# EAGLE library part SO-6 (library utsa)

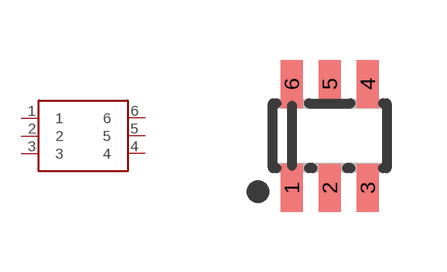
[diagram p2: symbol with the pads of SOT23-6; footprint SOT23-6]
Designator prefix -

## SO-6  [SOT23-6]
1  1
2  2
3  3
4  4
5  5
6  6

## Footprint SOT23-6 (pad centres in mm)
smd 0.55 x 1.2: 1 -0.95,-1.3; 2 0,-1.3; 3 0.95,-1.3; 4 0.95,1.3; 5 0,1.3; 6 -0.95,1.3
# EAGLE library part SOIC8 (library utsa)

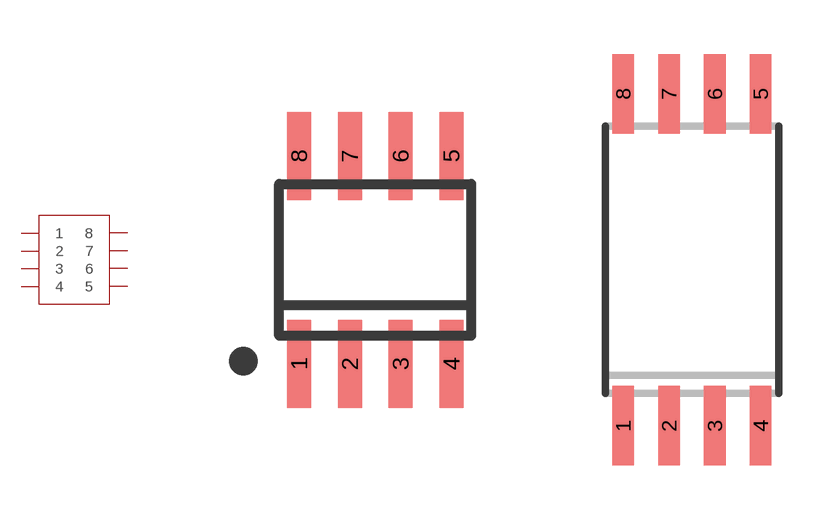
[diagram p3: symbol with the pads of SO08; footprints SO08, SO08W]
Designator prefix -

## SOIC8SO08  [SO08]
1  1
2  2
3  3
4  4
5  5
6  6
7  7
8  8

## SOIC8SO08W  [SO08W]
Pads as for SO08

## Footprint SO08 (pad centres in mm)
SMALL OUTLINE INTEGRATED CIRCUIT body 3.9 mm/JEDEC MS-012AA
smd 0.6 x 2.2: 1 -1.905,-2.6; 2 -0.635,-2.6; 3 0.635,-2.6; 4 1.905,-2.6; 5 1.905,2.6; 6 0.635,2.6; 7 -0.635,2.6; 8 -1.905,2.6

## Footprint SO08W (pad centres in mm)
SMALL OUTLINE INTEGRATED CIRCUIT wide body 7.5 mm/JEDEC MA-012AB
smd 0.6 x 2.2: 1 -1.905,-4.6; 2 -0.635,-4.6; 3 0.635,-4.6; 4 1.905,-4.6; 5 1.905,4.6; 6 0.635,4.6; 7 -0.635,4.6; 8 -1.905,4.6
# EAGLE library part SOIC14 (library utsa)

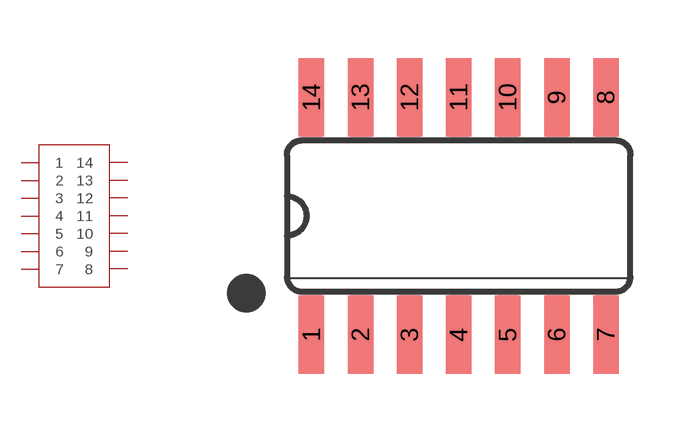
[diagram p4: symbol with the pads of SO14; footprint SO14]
Designator prefix -

## SOIC14  [SO14]
1  1
2  2
3  3
4  4
5  5
6  6
7  7
8  8
9  9
10  10
11  11
12  12
13  13
14  14

## Footprint SO14 (pad centres in mm)
Small Outline package 150 mil
smd 0.66 x 2.032: 1 -3.81,-3.073; 2 -2.54,-3.073; 3 -1.27,-3.073; 4 0,-3.073; 5 1.27,-3.073; 6 2.54,-3.073; 7 3.81,-3.073; 8 3.81,3.073; 9 2.54,3.073; 10 1.27,3.073; 11 0,3.073; 12 -1.27,3.073; 13 -2.54,3.073; 14 -3.81,3.073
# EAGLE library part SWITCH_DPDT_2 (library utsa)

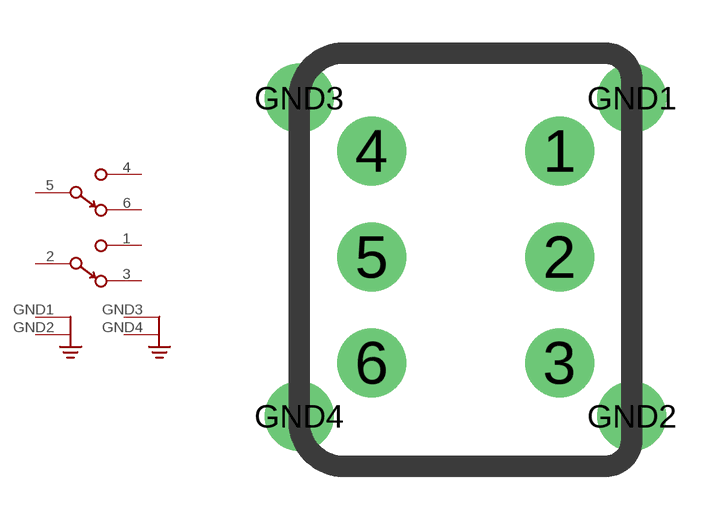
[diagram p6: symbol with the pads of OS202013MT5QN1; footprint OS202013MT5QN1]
Designator prefix -

## SWITCH_DPDT_2  [OS202013MT5QN1]
1  1
2  2
3  3
4  4
5  5
6  6
GND1  GND1
GND2  GND2
GND3  GND3
GND4  GND4

## Footprint OS202013MT5QN1 (pad centres in mm)
drill 1.3: 1 2.653,3.001; 2 2.653,0.004; 3 2.653,-2.993; 4 -2.655,3.001; 5 -2.655,0.004; 6 -2.655,-2.993; GND1 4.698,4.5; GND2 4.698,-4.492; GND3 -4.7,4.5; GND4 -4.7,-4.492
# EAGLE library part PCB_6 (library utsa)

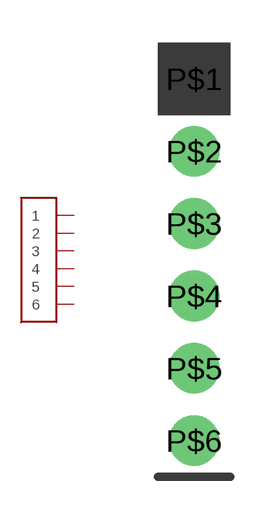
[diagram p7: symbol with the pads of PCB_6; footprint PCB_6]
Designator prefix -

## PCB_6  [PCB_6]
P$1  1
P$2  2
P$3  3
P$4  4
P$5  5
P$6  6

## Footprint PCB_6 (pad centres in mm)
drill 1.1 pad 1.778: P$1 0,0; P$2 0,-2.54; P$3 0,-5.08; P$4 0,-7.62; P$5 0,-10.16; P$6 0,-12.7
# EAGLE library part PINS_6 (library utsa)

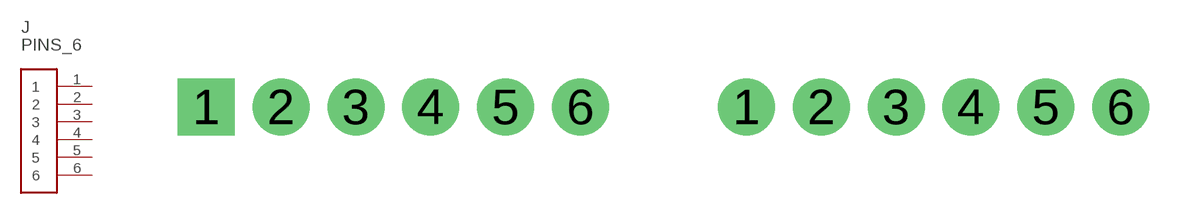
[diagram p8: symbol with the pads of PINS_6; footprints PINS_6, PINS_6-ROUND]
Designator prefix J

## PINS_6SQUARE  [PINS_6]
1  1
2  2
3  3
4  4
5  5
6  6

## PINS_6ROUND  [PINS_6-ROUND]
Pads as for PINS_6

## PINS_6SILK  [PCB_6]
P$1  1
P$2  2
P$3  3
P$4  4
P$5  5
P$6  6

## PINS_6-NANOFIT  [PINS_6_NANOFIT_RA]
Pads as for PINS_6

## PINS_6/1.27  [PINS_6_1MM27]
Pads as for PINS_6

## PINS_6105309-1106  [PINS_6-NANOFIT-V]
Pads as for PINS_6

## Footprint PINS_6 (pad centres in mm)
drill 1.1 pad 1.93 square: 1 0,0
drill 1.1 pad 1.93: 2 2.54,0; 3 5.08,0; 4 7.62,0; 5 10.16,0; 6 12.7,0

## Footprint PINS_6-ROUND (pad centres in mm)
drill 1.1 pad 1.93: 1 0,0; 2 2.54,0; 3 5.08,0; 4 7.62,0; 5 10.16,0; 6 12.7,0

## Footprint PCB_6 (pad centres in mm)
drill 1.1 pad 1.778: P$1 0,0; P$2 0,-2.54; P$3 0,-5.08; P$4 0,-7.62; P$5 0,-10.16; P$6 0,-12.7

## Footprint PINS_6_NANOFIT_RA (pad centres in mm)
drill 1.2 square: 1 2.5,0
drill 1.2: 2 0,0; 3 -2.5,0; 4 2.5,-2.5; 5 0,-2.5; 6 -2.5,-2.5
hole 1.7 at -2.5,-9.68
hole 1.7 at 2.5,-9.68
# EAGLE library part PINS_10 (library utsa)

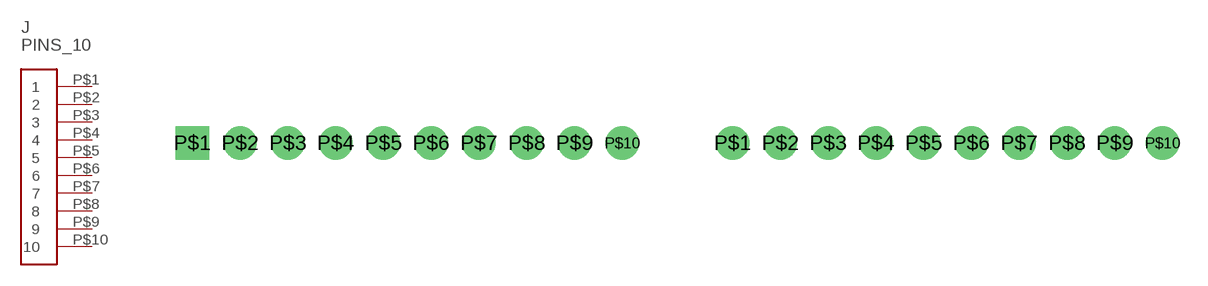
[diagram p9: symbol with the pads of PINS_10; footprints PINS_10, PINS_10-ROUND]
Designator prefix J

## PINS_10SQUARE  [PINS_10]
P$1  1
P$2  2
P$3  3
P$4  4
P$5  5
P$6  6
P$7  7
P$8  8
P$9  9
P$10  10

## PINS_10CIRCLE  [PINS_10-ROUND]
Pads as for PINS_10

## Footprint PINS_10 (pad centres in mm)
drill 1.1 pad 1.778 square: P$1 0,0
drill 1.1 pad 1.778: P$2 2.54,0; P$3 5.08,0; P$4 7.62,0; P$5 10.16,0; P$6 12.7,0; P$7 15.24,0; P$8 17.78,0; P$9 20.32,0; P$10 22.86,0

## Footprint PINS_10-ROUND (pad centres in mm)
drill 1.1 pad 1.778: P$1 0,0; P$2 2.54,0; P$3 5.08,0; P$4 7.62,0; P$5 10.16,0; P$6 12.7,0; P$7 15.24,0; P$8 17.78,0; P$9 20.32,0; P$10 22.86,0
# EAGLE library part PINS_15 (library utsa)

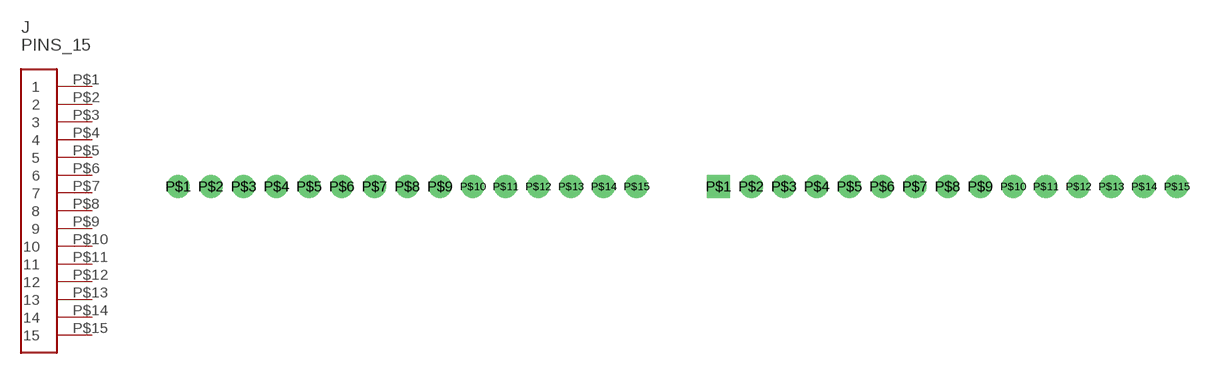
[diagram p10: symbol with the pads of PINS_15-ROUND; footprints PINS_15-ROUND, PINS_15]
Designator prefix J

## PINS_15ROUND  [PINS_15-ROUND]
P$1  1
P$2  2
P$3  3
P$4  4
P$5  5
P$6  6
P$7  7
P$8  8
P$9  9
P$10  10
P$11  11
P$12  12
P$13  13
P$14  14
P$15  15

## PINS_15SQUARE  [PINS_15]
Pads as for PINS_15-ROUND

## Footprint PINS_15-ROUND (pad centres in mm)
drill 1.1 pad 1.778: P$1 0,0; P$2 2.54,0; P$3 5.08,0; P$4 7.62,0; P$5 10.16,0; P$6 12.7,0; P$7 15.24,0; P$8 17.78,0; P$9 20.32,0; P$10 22.86,0; P$11 25.4,0; P$12 27.94,0; P$13 30.48,0; P$14 33.02,0; P$15 35.56,0

## Footprint PINS_15 (pad centres in mm)
drill 1.1 pad 1.778 square: P$1 0,0
drill 1.1 pad 1.778: P$2 2.54,0; P$3 5.08,0; P$4 7.62,0; P$5 10.16,0; P$6 12.7,0; P$7 15.24,0; P$8 17.78,0; P$9 20.32,0; P$10 22.86,0; P$11 25.4,0; P$12 27.94,0; P$13 30.48,0; P$14 33.02,0; P$15 35.56,0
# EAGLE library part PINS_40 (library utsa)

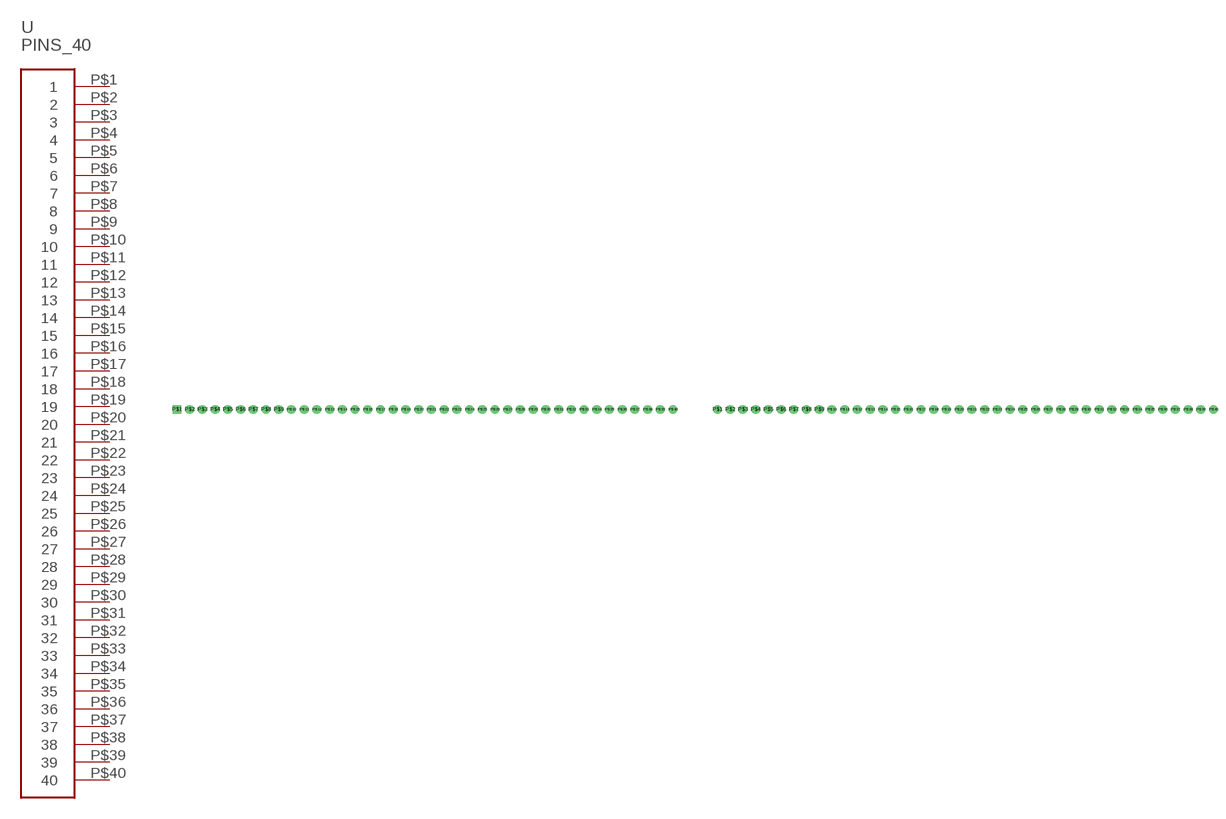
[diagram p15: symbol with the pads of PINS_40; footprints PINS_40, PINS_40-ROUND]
Designator prefix -

## PINS_40SQUARE  [PINS_40]
P$1  1
P$2  2
P$3  3
P$4  4
P$5  5
P$6  6
P$7  7
P$8  8
P$9  9
P$10  10
P$11  11
P$12  12
P$13  13
P$14  14
P$15  15
P$16  16
P$17  17
P$18  18
P$19  19
P$20  20
P$21  21
P$22  22
P$23  23
P$24  24
P$25  25
P$26  26
P$27  27
P$28  28
P$29  29
P$30  30
P$31  31
P$32  32
P$33  33
P$34  34
P$35  35
P$36  36
P$37  37
P$38  38
P$39  39
P$40  40

## PINS_40ROUND  [PINS_40-ROUND]
Pads as for PINS_40

## Footprint PINS_40 (pad centres in mm)
drill 1.1 pad 1.778 square: P$1 0,0
drill 1.1 pad 1.778: P$2 2.54,0; P$3 5.08,0; P$4 7.62,0; P$5 10.16,0; P$6 12.7,0; P$7 15.24,0; P$8 17.78,0; P$9 20.32,0; P$10 22.86,0; P$11 25.4,0; P$12 27.94,0; P$13 30.48,0; P$14 33.02,0; P$15 35.56,0; P$16 38.1,0; P$17 40.64,0; P$18 43.18,0; P$19 45.72,0; P$20 48.26,0; P$21 50.8,0; P$22 53.34,0; P$23 55.88,0; P$24 58.42,0; P$25 60.96,0; P$26 63.5,0; P$27 66.04,0; P$28 68.58,0; P$29 71.12,0; P$30 73.66,0; P$31 76.2,0; P$32 78.74,0; P$33 81.28,0; P$34 83.82,0; P$35 86.36,0; P$36 88.9,0; P$37 91.44,0; P$38 93.98,0; P$39 96.52,0; P$40 99.06,0

## Footprint PINS_40-ROUND (pad centres in mm)
drill 1.1 pad 1.778: P$1 0,0; P$2 2.54,0; P$3 5.08,0; P$4 7.62,0; P$5 10.16,0; P$6 12.7,0; P$7 15.24,0; P$8 17.78,0; P$9 20.32,0; P$10 22.86,0; P$11 25.4,0; P$12 27.94,0; P$13 30.48,0; P$14 33.02,0; P$15 35.56,0; P$16 38.1,0; P$17 40.64,0; P$18 43.18,0; P$19 45.72,0; P$20 48.26,0; P$21 50.8,0; P$22 53.34,0; P$23 55.88,0; P$24 58.42,0; P$25 60.96,0; P$26 63.5,0; P$27 66.04,0; P$28 68.58,0; P$29 71.12,0; P$30 73.66,0; P$31 76.2,0; P$32 78.74,0; P$33 81.28,0; P$34 83.82,0; P$35 86.36,0; P$36 88.9,0; P$37 91.44,0; P$38 93.98,0; P$39 96.52,0; P$40 99.06,0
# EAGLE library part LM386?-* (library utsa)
Low Voltage Audio Power Amplifier Source: http://cache.national.com/ds/LM/LM386.pdf

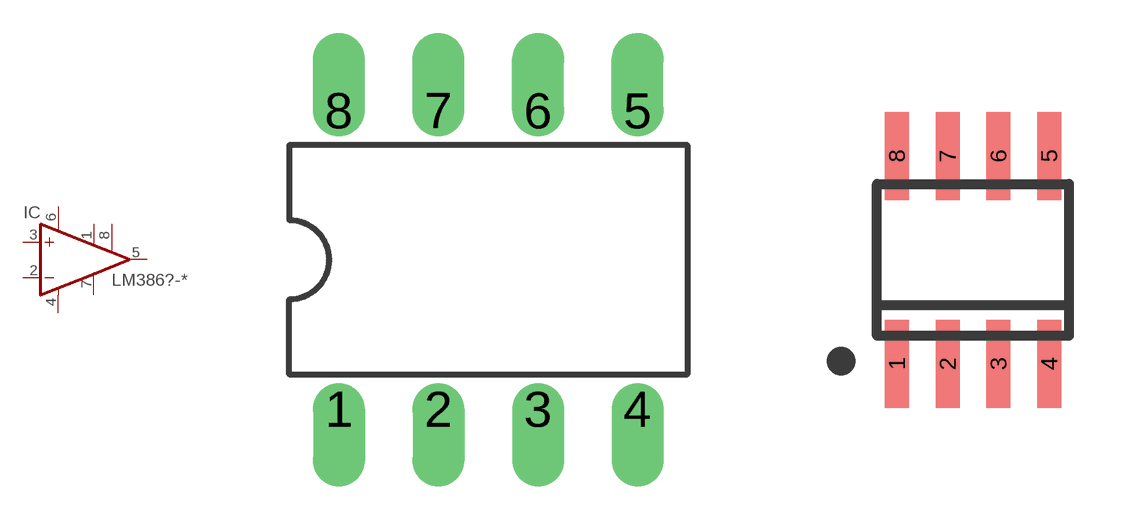
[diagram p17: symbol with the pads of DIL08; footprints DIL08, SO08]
Designator prefix IC

## LM386N-1, LM386N-3, LM386N-4  [DIL08]
1  GAIN  pas
2  -IN  in
3  +IN  in
4  GND  pwr
5  OUT  out
6  VS  pwr
7  BYPASS  pas
8  GAIN  pas

## LM386M-1  [SO08]
Pads as for DIL08

## LM386MM-1  [MMSOP08]
Pads as for DIL08

## Footprint DIL08 (pad centres in mm)
Dual In Line Package
drill 0.813 offset: 1 -3.81,-3.81; 2 -1.27,-3.81; 3 1.27,-3.81; 4 3.81,-3.81; 5 3.81,3.81; 6 1.27,3.81; 7 -1.27,3.81; 8 -3.81,3.81

## Footprint SO08 (pad centres in mm)
SMALL OUTLINE INTEGRATED CIRCUIT body 3.9 mm/JEDEC MS-012AA
smd 0.6 x 2.2: 1 -1.905,-2.6; 2 -0.635,-2.6; 3 0.635,-2.6; 4 1.905,-2.6; 5 1.905,2.6; 6 0.635,2.6; 7 -0.635,2.6; 8 -1.905,2.6

## Footprint MMSOP08 (pad centres in mm)
Molded Mini Small Outline Package 8 - Lead (0.118" Wide) NS Package Number MUA08A Source: http://cache.national.com/ds/LM/LM386.pdf
smd 0.41 x 1.02: 1 -0.975,-2.4; 2 -0.325,-2.4; 3 0.325,-2.4; 4 0.975,-2.4; 5 0.975,2.4; 6 0.325,2.4; 7 -0.325,2.4; 8 -0.975,2.4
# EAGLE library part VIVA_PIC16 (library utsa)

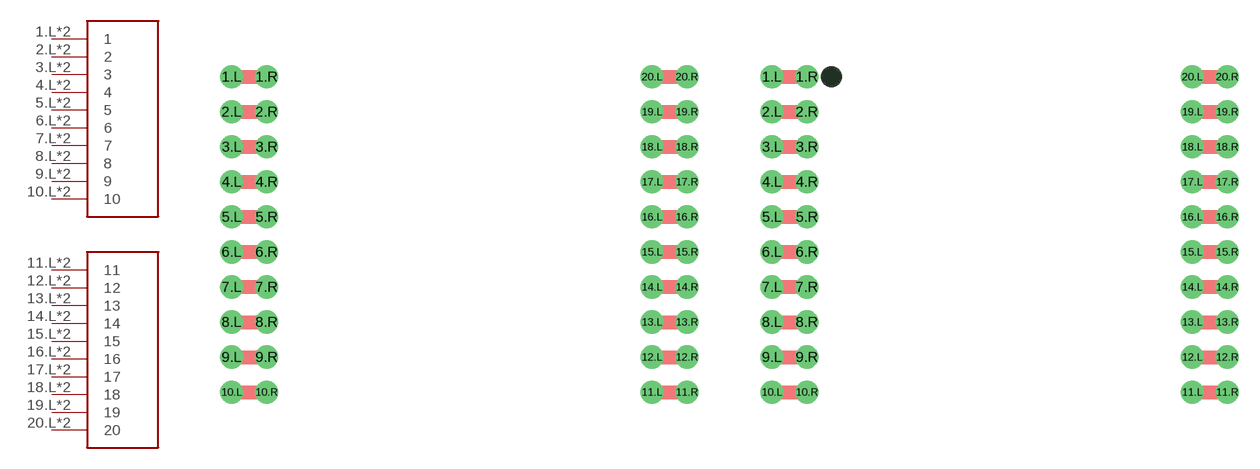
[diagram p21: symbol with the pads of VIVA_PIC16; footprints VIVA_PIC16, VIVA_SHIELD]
Designator prefix -

## VIVA_PIC16BOARD  [VIVA_PIC16]
1.L  1
1.R  1
2.L  2
2.R  2
3.L  3
3.R  3
4.L  4
4.R  4
5.L  5
5.R  5
6.L  6
6.R  6
7.L  7
7.R  7
8.L  8
8.R  8
9.L  9
9.R  9
10.L  10
10.R  10
11.L  11
11.R  11
12.L  12
12.R  12
13.L  13
13.R  13
14.L  14
14.R  14
15.L  15
15.R  15
16.L  16
16.R  16
17.L  17
17.R  17
18.L  18
18.R  18
19.L  19
19.R  19
20.L  20
20.R  20

## VIVA_PIC16SHIELD  [VIVA_SHIELD]
Pads as for VIVA_PIC16

## Footprint VIVA_PIC16 (pad centres in mm)
drill 1.1 pad 1.676: 1.L 0,0; 1.R 2.54,0; 2.L 0,-2.54; 2.R 2.54,-2.54; 3.L 0,-5.08; 3.R 2.54,-5.08; 4.L 0,-7.62; 4.R 2.54,-7.62; 5.L 0,-10.16; 5.R 2.54,-10.16; 6.L 0,-12.7; 6.R 2.54,-12.7; 7.L 0,-15.24; 7.R 2.54,-15.24; 8.L 0,-17.78; 8.R 2.54,-17.78; 9.L 0,-20.32; 9.R 2.54,-20.32; 10.L 0,-22.86; 10.R 2.54,-22.86; 11.L 30.48,-22.86; 11.R 33.02,-22.86; 12.L 30.48,-20.32; 12.R 33.02,-20.32; 13.L 30.48,-17.78; 13.R 33.02,-17.78; 14.L 30.48,-15.24; 14.R 33.02,-15.24; 15.L 30.48,-12.7; 15.R 33.02,-12.7; 16.L 30.48,-10.16; 16.R 33.02,-10.16; 17.L 30.48,-7.62; 17.R 33.02,-7.62; 18.L 30.48,-5.08; 18.R 33.02,-5.08; 19.L 30.48,-2.54; 19.R 33.02,-2.54; 20.L 30.48,0; 20.R 33.02,0

## Footprint VIVA_SHIELD (pad centres in mm)
drill 1.1 pad 1.676: 1.L 0,22.86; 1.R 2.54,22.86; 2.L 0,20.32; 2.R 2.54,20.32; 3.L 0,17.78; 3.R 2.54,17.78; 4.L 0,15.24; 4.R 2.54,15.24; 5.L 0,12.7; 5.R 2.54,12.7; 6.L 0,10.16; 6.R 2.54,10.16; 7.L 0,7.62; 7.R 2.54,7.62; 8.L 0,5.08; 8.R 2.54,5.08; 9.L 0,2.54; 9.R 2.54,2.54; 10.L 0,0; 10.R 2.54,0; 11.L 30.48,0; 11.R 33.02,0; 12.L 30.48,2.54; 12.R 33.02,2.54; 13.L 30.48,5.08; 13.R 33.02,5.08; 14.L 30.48,7.62; 14.R 33.02,7.62; 15.L 30.48,10.16; 15.R 33.02,10.16; 16.L 30.48,12.7; 16.R 33.02,12.7; 17.L 30.48,15.24; 17.R 33.02,15.24; 18.L 30.48,17.78; 18.R 33.02,17.78; 19.L 30.48,20.32; 19.R 33.02,20.32; 20.L 30.48,22.86; 20.R 33.02,22.86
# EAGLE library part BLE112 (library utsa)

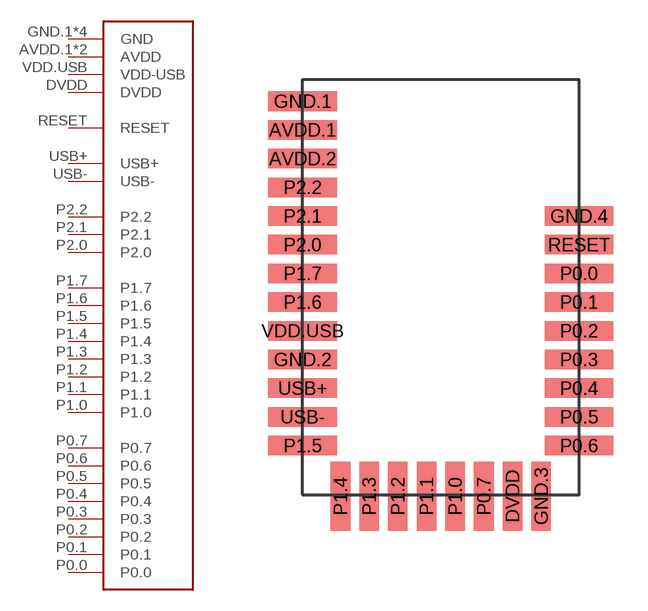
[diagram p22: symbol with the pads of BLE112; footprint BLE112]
Designator prefix -

## BLE112  [BLE112]
AVDD.1  AVDD
AVDD.2  AVDD
DVDD  DVDD
GND.1  GND
GND.2  GND
GND.3  GND
GND.4  GND
P0.0  P0.0
P0.1  P0.1
P0.2  P0.2
P0.3  P0.3
P0.4  P0.4
P0.5  P0.5
P0.6  P0.6
P0.7  P0.7
P1.0  P1.0
P1.1  P1.1
P1.2  P1.2
P1.3  P1.3
P1.4  P1.4
P1.5  P1.5
P1.6  P1.6
P1.7  P1.7
P2.0  P2.0
P2.1  P2.1
P2.2  P2.2
RESET  RESET
USB+  USB+
USB-  USB-
VDD.USB  VDD-USB

## Footprint BLE112 (pad centres in mm)
smd 3 x 0.85: AVDD.1 -5.8,7; AVDD.2 -5.8,5.75; GND.1 -5.8,8.25; GND.2 -5.8,-3; GND.4 6.25,3.25; P0.0 6.25,0.75; P0.1 6.25,-0.5; P0.2 6.25,-1.75; P0.3 6.25,-3; P0.4 6.25,-4.25; P0.5 6.25,-5.5; P0.6 6.25,-6.75; P1.5 -5.8,-6.75; P1.6 -5.8,-0.5; P1.7 -5.8,0.75; P2.0 -5.8,2; P2.1 -5.8,3.25; P2.2 -5.8,4.5; RESET 6.25,2; USB+ -5.8,-4.25; USB- -5.8,-5.5; VDD.USB -5.8,-1.75
smd 0.85 x 3: DVDD 3.35,-8.95; GND.3 4.6,-8.95; P0.7 2.1,-8.95; P1.0 0.85,-8.95; P1.1 -0.4,-8.95; P1.2 -1.65,-8.95; P1.3 -2.9,-8.95; P1.4 -4.15,-8.95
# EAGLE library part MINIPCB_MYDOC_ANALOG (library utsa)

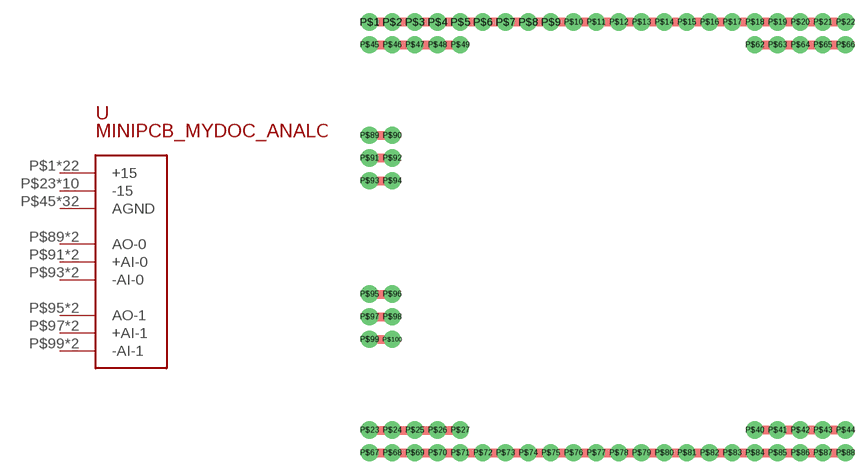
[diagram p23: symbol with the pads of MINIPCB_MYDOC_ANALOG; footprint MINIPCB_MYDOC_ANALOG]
Designator prefix -

## MINIPCB_MYDOC_ANALOG  [MINIPCB_MYDOC_ANALOG]
P$1  +15
P$2  +15
P$3  +15
P$4  +15
P$5  +15
P$6  +15
P$7  +15
P$8  +15
P$9  +15
P$10  +15
P$11  +15
P$12  +15
P$13  +15
P$14  +15
P$15  +15
P$16  +15
P$17  +15
P$18  +15
P$19  +15
P$20  +15
P$21  +15
P$22  +15
P$23  -15
P$24  -15
P$25  -15
P$26  -15
P$27  -15
P$40  -15
P$41  -15
P$42  -15
P$43  -15
P$44  -15
P$45  AGND
P$46  AGND
P$47  AGND
P$48  AGND
P$49  AGND
P$62  AGND
P$63  AGND
P$64  AGND
P$65  AGND
P$66  AGND
P$67  AGND
P$68  AGND
P$69  AGND
P$70  AGND
P$71  AGND
P$72  AGND
P$73  AGND
P$74  AGND
P$75  AGND
P$76  AGND
P$77  AGND
P$78  AGND
P$79  AGND
P$80  AGND
P$81  AGND
P$82  AGND
P$83  AGND
P$84  AGND
P$85  AGND
P$86  AGND
P$87  AGND
P$88  AGND
P$89  AO-0
P$90  AO-0
P$91  +AI-0
P$92  +AI-0
P$93  -AI-0
P$94  -AI-0
P$95  AO-1
P$96  AO-1
P$97  +AI-1
P$98  +AI-1
P$99  -AI-1
P$100  -AI-1

## Footprint MINIPCB_MYDOC_ANALOG (pad centres in mm)
drill 1.1 pad 1.93: P$1 0,45.72; P$2 2.54,45.72; P$3 5.08,45.72; P$4 7.62,45.72; P$5 10.16,45.72; P$6 12.7,45.72; P$7 15.24,45.72; P$8 17.78,45.72; P$9 20.32,45.72; P$10 22.86,45.72; P$11 25.4,45.72; P$12 27.94,45.72; P$13 30.48,45.72; P$14 33.02,45.72; P$15 35.56,45.72; P$16 38.1,45.72; P$17 40.64,45.72; P$18 43.18,45.72; P$19 45.72,45.72; P$20 48.26,45.72; P$21 50.8,45.72; P$22 53.34,45.72; P$23 0,0; P$24 2.54,0; P$25 5.08,0; P$26 7.62,0; P$27 10.16,0; P$40 43.18,0; P$41 45.72,0; P$42 48.26,0; P$43 50.8,0; P$44 53.34,0; P$45 0,43.18; P$46 2.54,43.18; P$47 5.08,43.18; P$48 7.62,43.18; P$49 10.16,43.18; P$62 43.18,43.18; P$63 45.72,43.18; P$64 48.26,43.18; P$65 50.8,43.18; P$66 53.34,43.18; P$67 0,-2.54; P$68 2.54,-2.54; P$69 5.08,-2.54; P$70 7.62,-2.54; P$71 10.16,-2.54; P$72 12.7,-2.54; P$73 15.24,-2.54; P$74 17.78,-2.54; P$75 20.32,-2.54; P$76 22.86,-2.54; P$77 25.4,-2.54; P$78 27.94,-2.54; P$79 30.48,-2.54; P$80 33.02,-2.54; P$81 35.56,-2.54; P$82 38.1,-2.54; P$83 40.64,-2.54; P$84 43.18,-2.54; P$85 45.72,-2.54; P$86 48.26,-2.54; P$87 50.8,-2.54; P$88 53.34,-2.54; P$89 0,33.02; P$90 2.54,33.02; P$91 0,30.48; P$92 2.54,30.48; P$93 0,27.94; P$94 2.54,27.94; P$95 0,15.24; P$96 2.54,15.24; P$97 0,12.7; P$98 2.54,12.7; P$99 0,10.16; P$100 2.54,10.16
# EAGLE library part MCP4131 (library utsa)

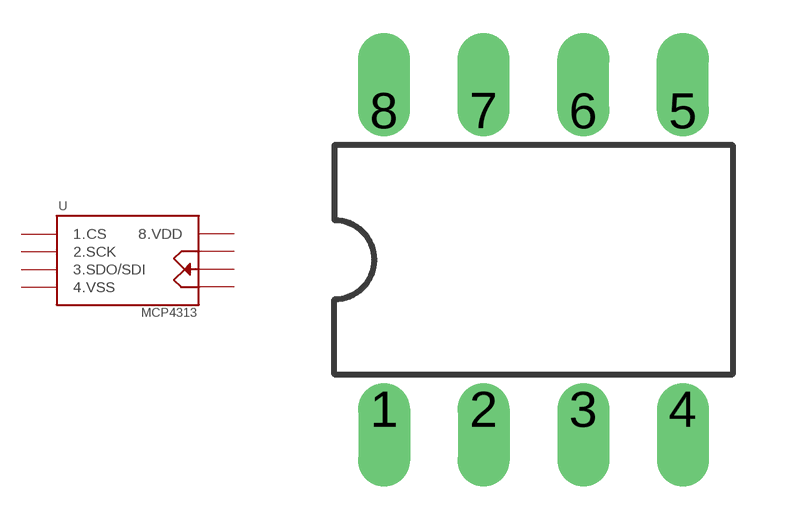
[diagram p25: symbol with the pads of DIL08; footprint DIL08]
Designator prefix -

## MCP4131  [DIL08]
1  1.CS
2  2.SCK
3  3.SDO/SDI
4  4.VSS
5  5.P0A
6  6.P0W
7  7.P0B
8  8.VDD

## Footprint DIL08 (pad centres in mm)
Dual In Line Package
drill 0.813 offset: 1 -3.81,-3.81; 2 -1.27,-3.81; 3 1.27,-3.81; 4 3.81,-3.81; 5 3.81,3.81; 6 1.27,3.81; 7 -1.27,3.81; 8 -3.81,3.81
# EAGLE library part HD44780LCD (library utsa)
HD44780 LCD Standard character type LCDs, available in sizes from 8x1 to 40x4!

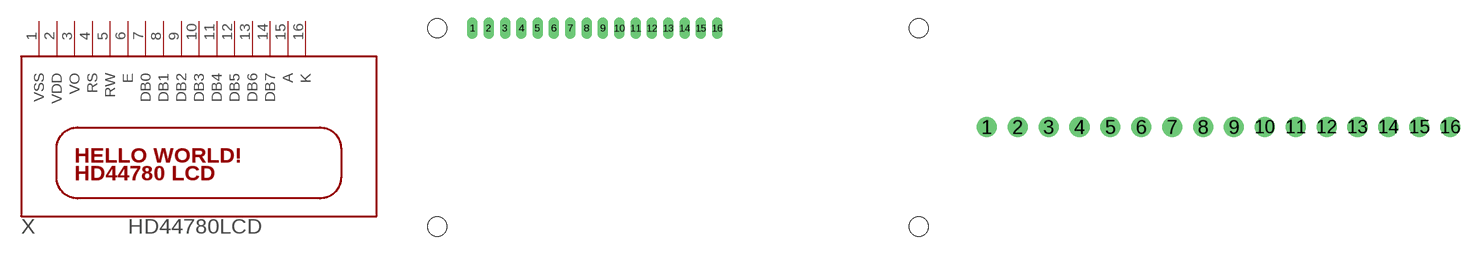
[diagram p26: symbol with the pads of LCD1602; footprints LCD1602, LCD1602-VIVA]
Designator prefix X

## HD44780LCD-1602  [LCD1602]
1  VSS  sup
2  VDD  sup
3  VO  in
4  RS  in
5  RW  in
6  E  in
7  DB0
8  DB1
9  DB2
10  DB3
11  DB4
12  DB5
13  DB6
14  DB7
15  A  in
16  K  in

## HD44780LCD-VIVA  [LCD1602-VIVA]
Pads as for LCD1602

## Footprint LCD1602 (pad centres in mm)
drill 1.1 long: 1 8,33.46; 2 10.54,33.46; 3 13.08,33.46; 4 15.62,33.46; 5 18.16,33.46; 6 20.7,33.46; 7 23.24,33.46; 8 25.78,33.46; 9 28.32,33.46; 10 30.86,33.46; 11 33.4,33.46; 12 35.94,33.46; 13 38.48,33.46; 14 41.02,33.46; 15 43.56,33.46; 16 46.1,33.46
hole 3 at 2.54,2.54
hole 3 at 2.54,33.46
hole 3 at 77.46,33.46
hole 3 at 77.46,2.54

## Footprint LCD1602-VIVA (pad centres in mm)
drill 1.1: 1 8,33.46; 2 10.54,33.46; 3 13.08,33.46; 4 15.62,33.46; 5 18.16,33.46; 6 20.7,33.46; 7 23.24,33.46; 8 25.78,33.46; 9 28.32,33.46; 10 30.86,33.46; 11 33.4,33.46; 12 35.94,33.46; 13 38.48,33.46; 14 41.02,33.46; 15 43.56,33.46; 16 46.1,33.46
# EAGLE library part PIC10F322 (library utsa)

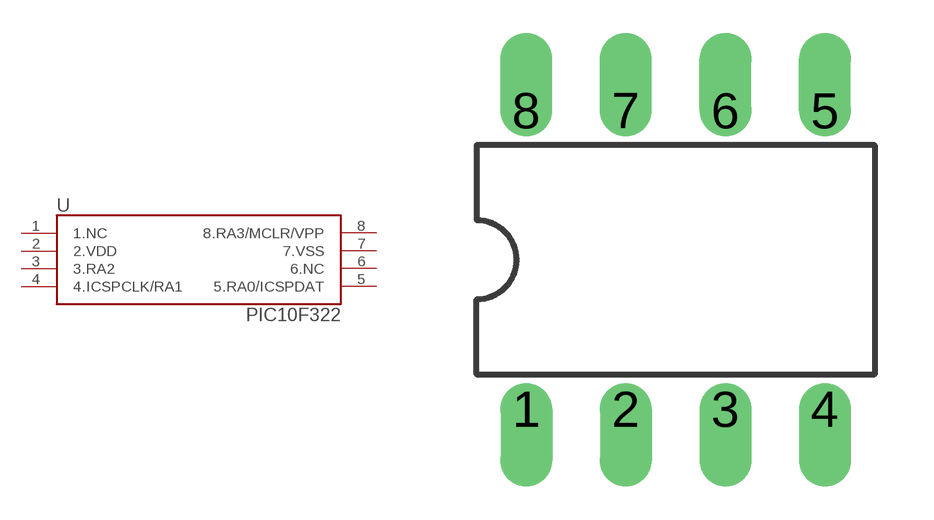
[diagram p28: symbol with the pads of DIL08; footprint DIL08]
Designator prefix -

## PIC10F322DIP  [DIL08]
1  1.NC
2  2.VDD
3  3.RA2
4  4.ICSPCLK/RA1
5  5.RA0/ICSPDAT
6  6.NC
7  7.VSS
8  8.RA3/MCLR/VPP

## Footprint DIL08 (pad centres in mm)
Dual In Line Package
drill 0.813 offset: 1 -3.81,-3.81; 2 -1.27,-3.81; 3 1.27,-3.81; 4 3.81,-3.81; 5 3.81,3.81; 6 1.27,3.81; 7 -1.27,3.81; 8 -3.81,3.81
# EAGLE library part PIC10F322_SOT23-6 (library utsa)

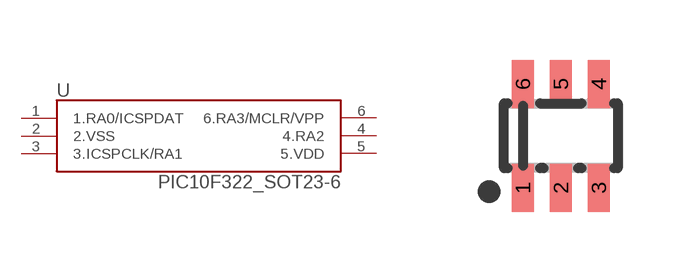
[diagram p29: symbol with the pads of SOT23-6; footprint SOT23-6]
Designator prefix -

## PIC10F322_SOT23-6  [SOT23-6]
1  1.RA0/ICSPDAT
2  2.VSS
3  3.ICSPCLK/RA1
4  4.RA2
5  5.VDD
6  6.RA3/MCLR/VPP

## Footprint SOT23-6 (pad centres in mm)
smd 0.55 x 1.2: 1 -0.95,-1.3; 2 0,-1.3; 3 0.95,-1.3; 4 0.95,1.3; 5 0,1.3; 6 -0.95,1.3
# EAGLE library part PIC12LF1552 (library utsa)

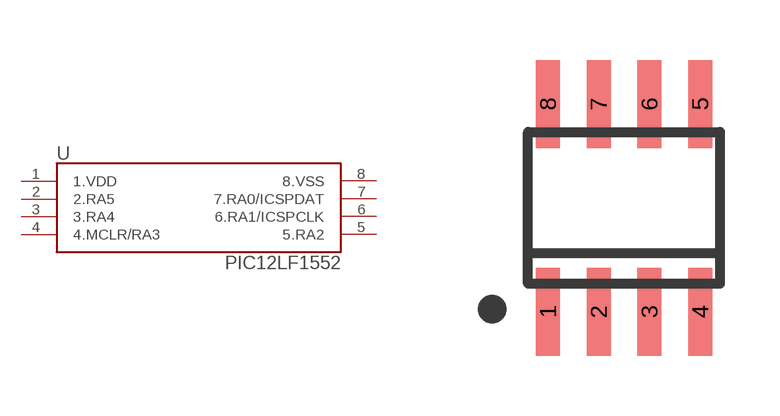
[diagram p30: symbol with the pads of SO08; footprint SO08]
Designator prefix -

## PIC12LF1552  [SO08]
1  1.VDD
2  2.RA5
3  3.RA4
4  4.MCLR/RA3
5  5.RA2
6  6.RA1/ICSPCLK
7  7.RA0/ICSPDAT
8  8.VSS

## Footprint SO08 (pad centres in mm)
SMALL OUTLINE INTEGRATED CIRCUIT body 3.9 mm/JEDEC MS-012AA
smd 0.6 x 2.2: 1 -1.905,-2.6; 2 -0.635,-2.6; 3 0.635,-2.6; 4 1.905,-2.6; 5 1.905,2.6; 6 0.635,2.6; 7 -0.635,2.6; 8 -1.905,2.6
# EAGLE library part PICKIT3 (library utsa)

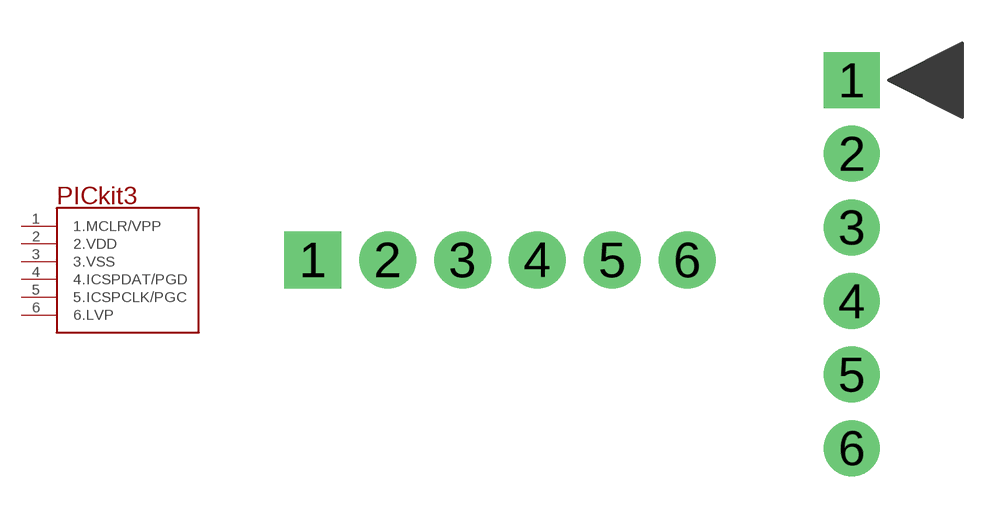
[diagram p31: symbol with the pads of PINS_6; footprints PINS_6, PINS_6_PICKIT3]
Designator prefix -

## PICKIT3PLAIN  [PINS_6]
1  1.MCLR/VPP
2  2.VDD
3  3.VSS
4  4.ICSPDAT/PGD
5  5.ICSPCLK/PGC
6  6.LVP

## PICKIT3ARROW  [PINS_6_PICKIT3]
Pads as for PINS_6

## PICKIT3TEXT  [PINS_6_PICKIT3_TEXT]
Pads as for PINS_6

## PICKIT3SMALL  [PINS_6_PICKIT3-SMALL]
Pads as for PINS_6

## PICKIT3/1.27  [PINS_6_1MM27]
Pads as for PINS_6

## Footprint PINS_6 (pad centres in mm)
drill 1.1 pad 1.93 square: 1 0,0
drill 1.1 pad 1.93: 2 2.54,0; 3 5.08,0; 4 7.62,0; 5 10.16,0; 6 12.7,0

## Footprint PINS_6_PICKIT3 (pad centres in mm)
drill 1.1 pad 1.93 square: 1 0,0
drill 1.1 pad 1.93: 2 0,-2.54; 3 0,-5.08; 4 0,-7.62; 5 0,-10.16; 6 0,-12.7

## Footprint PINS_6_PICKIT3_TEXT (pad centres in mm)
drill 1.1 pad 1.93 square: 1 0,0
drill 1.1 pad 1.93: 2 0,-2.54; 3 0,-5.08; 4 0,-7.62; 5 0,-10.16; 6 0,-12.7

## Footprint PINS_6_PICKIT3-SMALL (pad centres in mm)
drill 0.9 square: 1 0,0
drill 0.9: 2 0,-2.54; 3 0,-5.08; 4 0,-7.62; 5 0,-10.16; 6 0,-12.7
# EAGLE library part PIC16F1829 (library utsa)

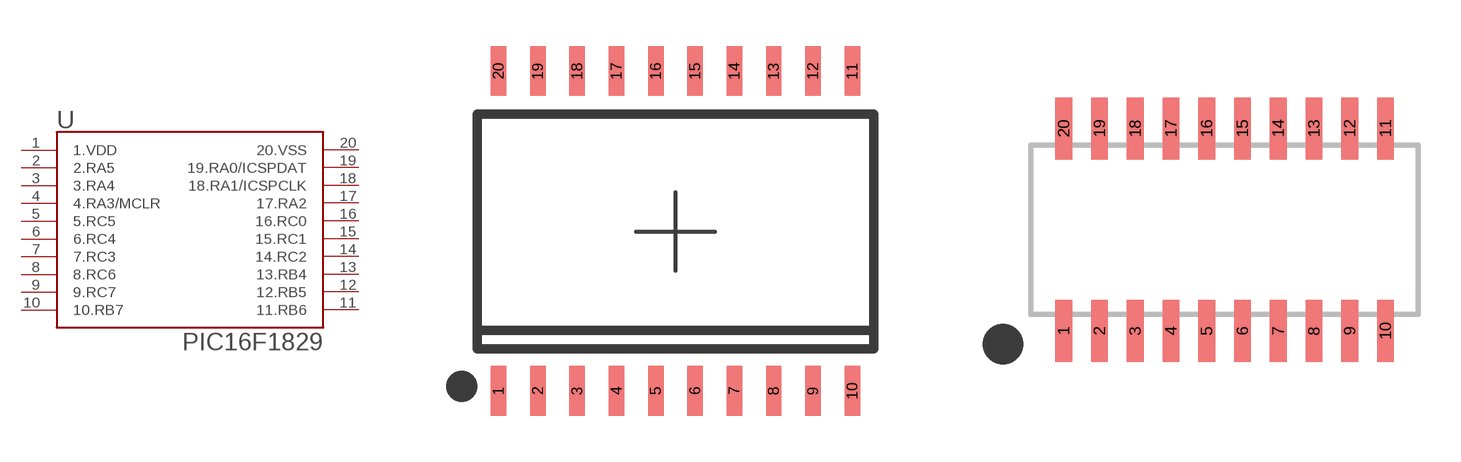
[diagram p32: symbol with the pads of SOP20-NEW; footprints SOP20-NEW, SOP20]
Designator prefix U

## PIC16F1829300  [SOP20-NEW]
1  1.VDD
2  2.RA5
3  3.RA4
4  4.RA3/MCLR
5  5.RC5
6  6.RC4
7  7.RC3
8  8.RC6
9  9.RC7
10  10.RB7
11  11.RB6
12  12.RB5
13  13.RB4
14  14.RC2
15  15.RC1
16  16.RC0
17  17.RA2
18  18.RA1/ICSPCLK
19  19.RA0/ICSPDAT
20  20.VSS

## PIC16F1829150  [SOP20]
Pads as for SOP20-NEW

## Footprint SOP20-NEW (pad centres in mm)
smd 0.5 x 1.6: 1 -5.715,-5.152; 2 -4.445,-5.152; 3 -3.175,-5.152; 4 -1.905,-5.152; 5 -0.635,-5.152; 6 0.635,-5.152; 7 1.905,-5.152; 8 3.175,-5.152; 9 4.445,-5.152; 10 5.715,-5.152; 11 5.715,5.188; 12 4.445,5.188; 13 3.175,5.188; 14 1.905,5.188; 15 0.635,5.188; 16 -0.635,5.188; 17 -1.905,5.188; 18 -3.175,5.188; 19 -4.445,5.188; 20 -5.715,5.188

## Footprint SOP20 (pad centres in mm)
SMALL OUTLINE PACKAGE
smd 0.6 x 2.2: 1 -5.715,-3.6; 2 -4.445,-3.6; 3 -3.175,-3.6; 4 -1.905,-3.6; 5 -0.635,-3.6; 6 0.635,-3.6; 7 1.905,-3.6; 8 3.175,-3.6; 9 4.445,-3.6; 10 5.715,-3.6; 11 5.715,3.6; 12 4.445,3.6; 13 3.175,3.6; 14 1.905,3.6; 15 0.635,3.6; 16 -0.635,3.6; 17 -1.905,3.6; 18 -3.175,3.6; 19 -4.445,3.6; 20 -5.715,3.6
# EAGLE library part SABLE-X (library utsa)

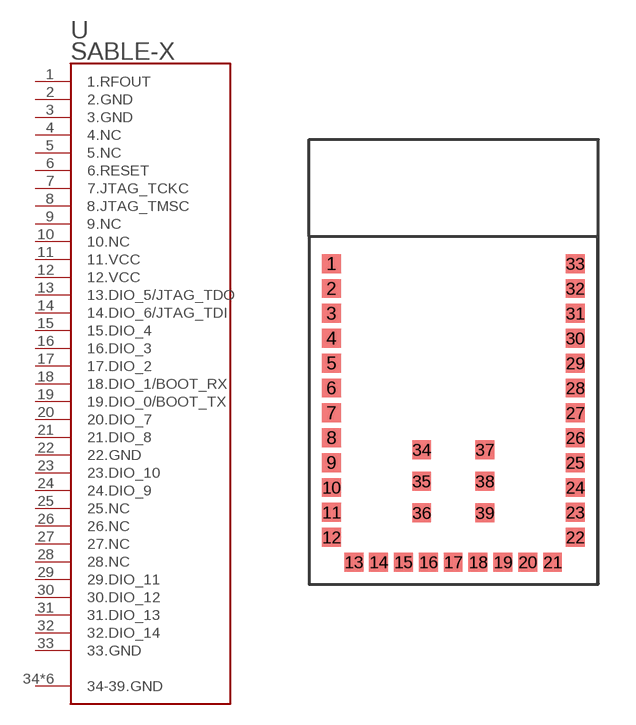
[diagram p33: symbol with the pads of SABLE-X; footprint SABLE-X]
Designator prefix -

## SABLE-X  [SABLE-X]
1  1.RFOUT
2  2.GND
3  3.GND
4  4.NC
5  5.NC
6  6.RESET
7  7.JTAG_TCKC
8  8.JTAG_TMSC
9  9.NC
10  10.NC
11  11.VCC
12  12.VCC
13  13.DIO_5/JTAG_TDO
14  14.DIO_6/JTAG_TDI
15  15.DIO_4
16  16.DIO_3
17  17.DIO_2
18  18.DIO_1/BOOT_RX
19  19.DIO_0/BOOT_TX
20  20.DIO_7
21  21.DIO_8
22  22.GND
23  23.DIO_10
24  24.DIO_9
25  25.NC
26  26.NC
27  27.NC
28  28.NC
29  29.DIO_11
30  30.DIO_12
31  31.DIO_13
32  32.DIO_14
33  33.GND
34  34-39.GND
35  34-39.GND
36  34-39.GND
37  34-39.GND
38  34-39.GND
39  34-39.GND

## Footprint SABLE-X (pad centres in mm)
smd 0.76 x 0.76: 1 0,0; 2 0,-1; 3 0,-2; 4 0,-3; 5 0,-4; 6 0,-5; 7 0,-6; 8 0,-7; 9 0,-8; 10 0,-9; 11 0,-10; 12 0,-11; 13 0.9,-12; 14 1.9,-12; 15 2.9,-12; 16 3.9,-12; 17 4.9,-12; 18 5.9,-12; 19 6.9,-12; 20 7.9,-12; 21 8.9,-12; 22 9.81,-11; 23 9.81,-10; 24 9.81,-9; 25 9.81,-8; 26 9.81,-7; 27 9.81,-6; 28 9.81,-5; 29 9.81,-4; 30 9.81,-3; 31 9.81,-2; 32 9.81,-1; 33 9.81,0; 34 3.63,-7.48; 35 3.63,-8.75; 36 3.63,-10.02; 37 6.17,-7.48; 38 6.17,-8.75; 39 6.17,-10.02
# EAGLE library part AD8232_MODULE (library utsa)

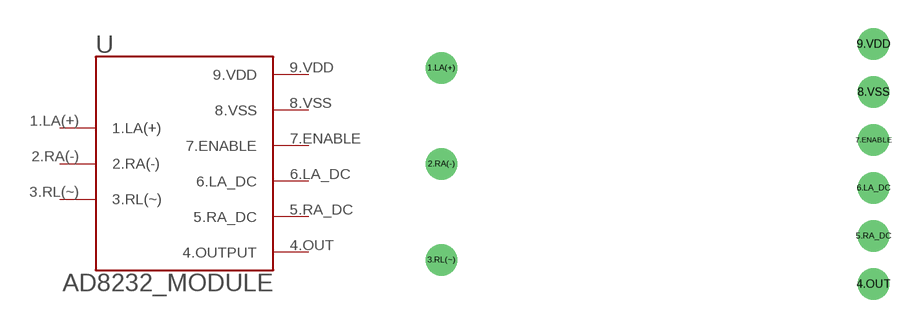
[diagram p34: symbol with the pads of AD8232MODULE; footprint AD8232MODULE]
Designator prefix -

## AD8232_MODULE  [AD8232MODULE]
1.LA(+)  1.LA(+)
2.RA(-)  2.RA(-)
3.RL(~)  3.RL(~)
4.OUT  4.OUTPUT
5.RA_DC  5.RA_DC
6.LA_DC  6.LA_DC
7.ENABLE  7.ENABLE
8.VSS  8.VSS
9.VDD  9.VDD

## Footprint AD8232MODULE (pad centres in mm)
drill 1.1: 1.LA(+) 0,0; 2.RA(-) 0,-5.08; 3.RL(~) 0,-10.16; 4.OUT 22.86,-11.43; 5.RA_DC 22.86,-8.89; 6.LA_DC 22.86,-6.35; 7.ENABLE 22.86,-3.81; 8.VSS 22.86,-1.27; 9.VDD 22.86,1.27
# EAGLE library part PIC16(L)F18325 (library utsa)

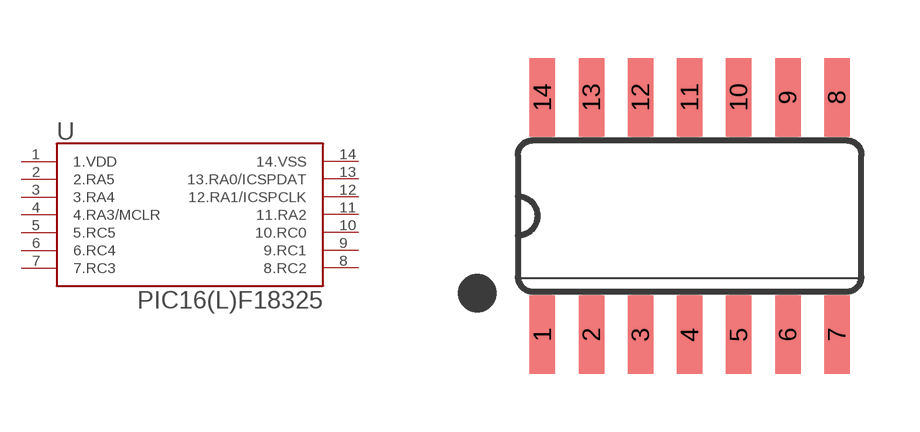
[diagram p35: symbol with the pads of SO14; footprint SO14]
Designator prefix U

## PIC16(L)F18325  [SO14]
1  1.VDD
2  2.RA5
3  3.RA4
4  4.RA3/MCLR
5  5.RC5
6  6.RC4
7  7.RC3
8  8.RC2
9  9.RC1
10  10.RC0
11  11.RA2
12  12.RA1/ICSPCLK
13  13.RA0/ICSPDAT
14  14.VSS

## Footprint SO14 (pad centres in mm)
Small Outline package 150 mil
smd 0.66 x 2.032: 1 -3.81,-3.073; 2 -2.54,-3.073; 3 -1.27,-3.073; 4 0,-3.073; 5 1.27,-3.073; 6 2.54,-3.073; 7 3.81,-3.073; 8 3.81,3.073; 9 2.54,3.073; 10 1.27,3.073; 11 0,3.073; 12 -1.27,3.073; 13 -2.54,3.073; 14 -3.81,3.073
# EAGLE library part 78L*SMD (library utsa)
Positive VOLTAGE REGULATOR

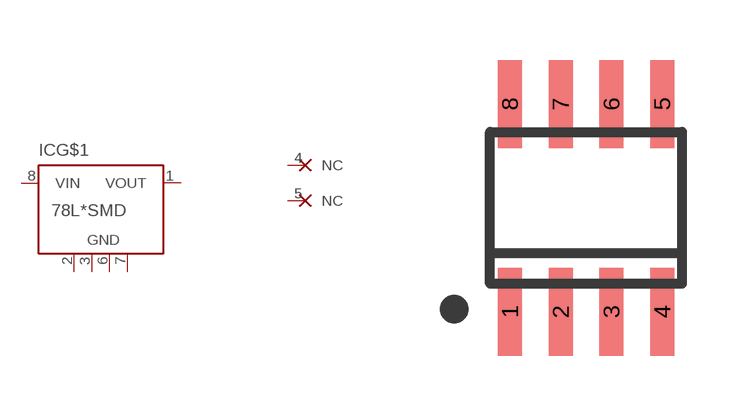
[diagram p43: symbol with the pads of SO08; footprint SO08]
Designator prefix IC; gates G$1=LM78LXX NC4=NC NC5=NC

## 78L05SMD, 78L06SMD, 78L08SMD, 78L12SMD, 78L15SMD, 78L18SMD, 78L24SMD  [SO08]
1  G$1:VOUT  out
2  G$1:GND  pwr
3  G$1:GND  pwr
4  NC4:NC  nc
5  NC5:NC  nc
6  G$1:GND  pwr
7  G$1:GND  pwr
8  G$1:VIN  pas

## Footprint SO08 (pad centres in mm)
SMALL OUTLINE INTEGRATED CIRCUIT body 3.9 mm/JEDEC MS-012AA
smd 0.6 x 2.2: 1 -1.905,-2.6; 2 -0.635,-2.6; 3 0.635,-2.6; 4 1.905,-2.6; 5 1.905,2.6; 6 0.635,2.6; 7 -0.635,2.6; 8 -1.905,2.6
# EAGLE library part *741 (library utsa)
OP AMP

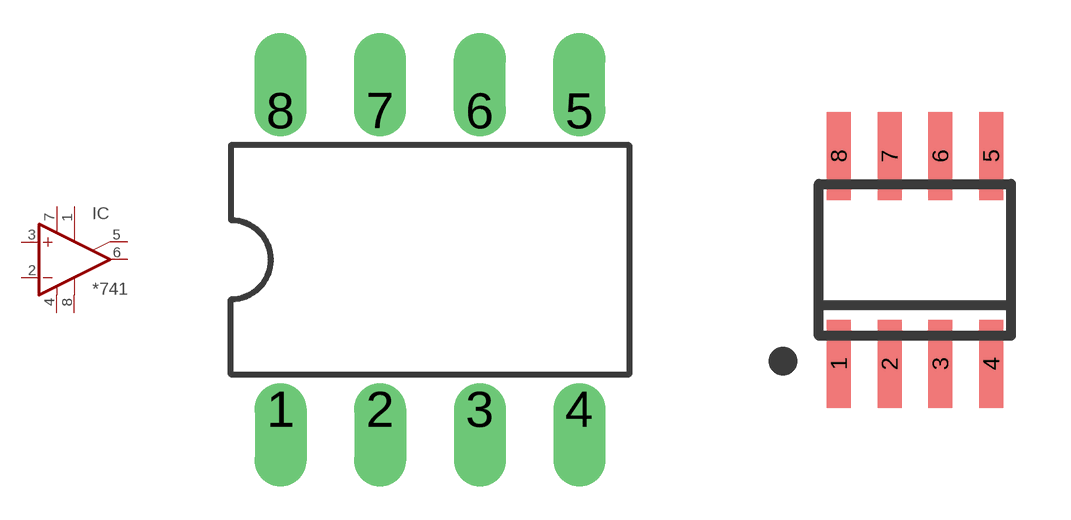
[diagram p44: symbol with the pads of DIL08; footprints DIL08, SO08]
Designator prefix IC

## LM741P, UA741P  [DIL08]
1  ON1  pas
2  -IN  in
3  +IN  in
4  V-  pwr
5  ON2  pas
6  OUT  out
7  V+  pwr
8  OPT  pas

## LM741D, UA741D  [SO08]
Pads as for DIL08

## Footprint DIL08 (pad centres in mm)
Dual In Line Package
drill 0.813 offset: 1 -3.81,-3.81; 2 -1.27,-3.81; 3 1.27,-3.81; 4 3.81,-3.81; 5 3.81,3.81; 6 1.27,3.81; 7 -1.27,3.81; 8 -3.81,3.81

## Footprint SO08 (pad centres in mm)
SMALL OUTLINE INTEGRATED CIRCUIT body 3.9 mm/JEDEC MS-012AA
smd 0.6 x 2.2: 1 -1.905,-2.6; 2 -0.635,-2.6; 3 0.635,-2.6; 4 1.905,-2.6; 5 1.905,2.6; 6 0.635,2.6; 7 -0.635,2.6; 8 -1.905,2.6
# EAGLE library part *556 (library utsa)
Dual TIMER

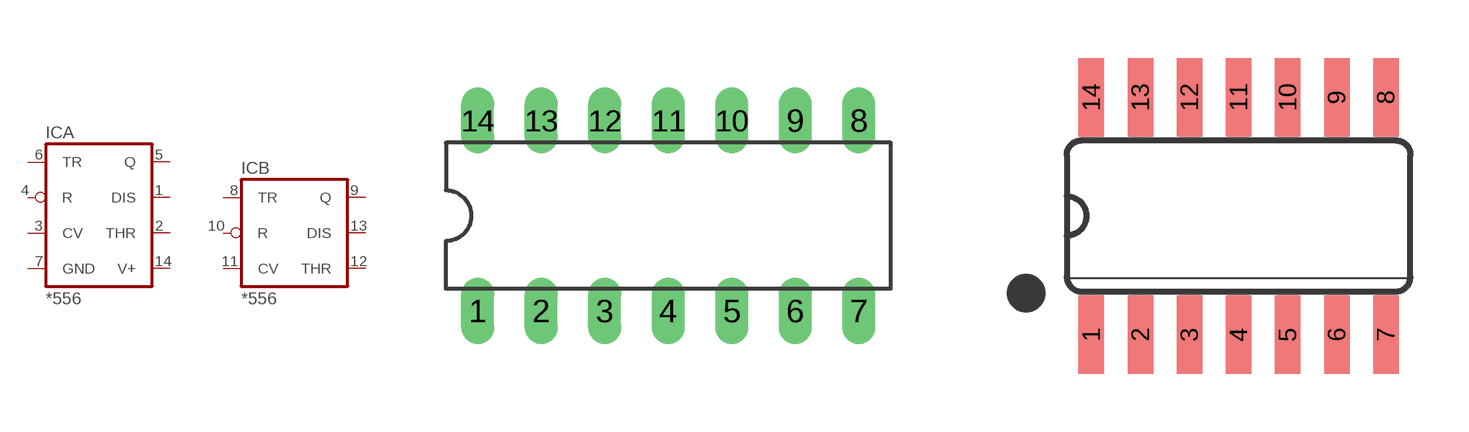
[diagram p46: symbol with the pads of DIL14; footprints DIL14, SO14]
Designator prefix IC; gates A=555 B=556

## LM556N, NE556N, SE556N  [DIL14]
1  A:DIS  in
2  A:THR  in
3  A:CV  in
4  A:R  in
5  A:Q  out
6  A:TR  in
7  A:GND  pwr
8  B:TR  in
9  B:Q  out
10  B:R  in
11  B:CV  in
12  B:THR  in
13  B:DIS  in
14  A:V+  pwr

## LM556D, NE556D, SE556D, UA556D  [SO14]
Pads as for DIL14

## Footprint DIL14 (pad centres in mm)
Dual In Line Package
drill 0.813 long: 1 -7.62,-3.81; 2 -5.08,-3.81; 3 -2.54,-3.81; 4 0,-3.81; 5 2.54,-3.81; 6 5.08,-3.81; 7 7.62,-3.81; 8 7.62,3.81; 9 5.08,3.81; 10 2.54,3.81; 11 0,3.81; 12 -2.54,3.81; 13 -5.08,3.81; 14 -7.62,3.81

## Footprint SO14 (pad centres in mm)
Small Outline package 150 mil
smd 0.66 x 2.032: 1 -3.81,-3.073; 2 -2.54,-3.073; 3 -1.27,-3.073; 4 0,-3.073; 5 1.27,-3.073; 6 2.54,-3.073; 7 3.81,-3.073; 8 3.81,3.073; 9 2.54,3.073; 10 1.27,3.073; 11 0,3.073; 12 -1.27,3.073; 13 -2.54,3.073; 14 -3.81,3.073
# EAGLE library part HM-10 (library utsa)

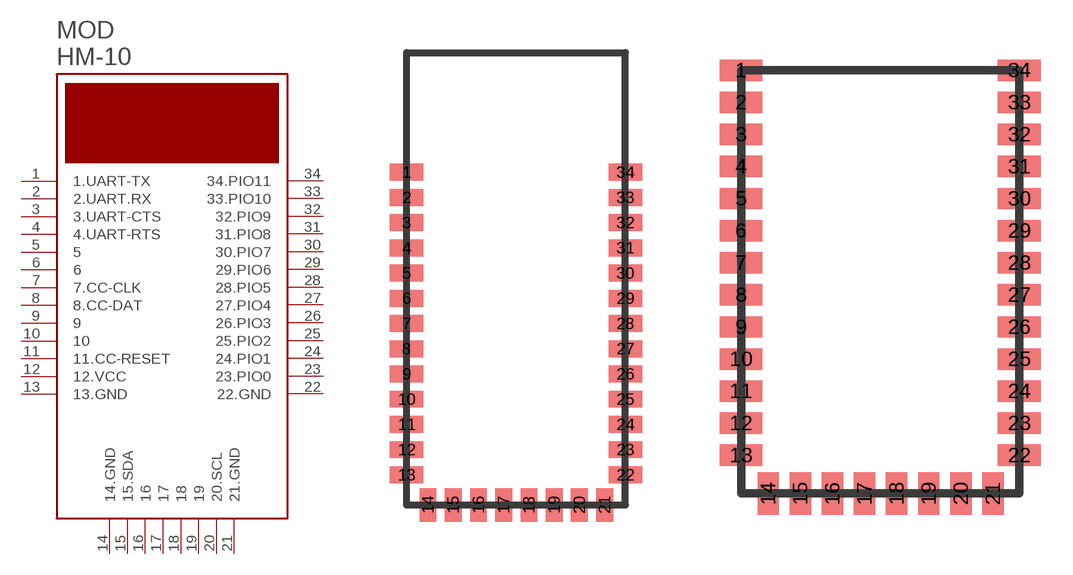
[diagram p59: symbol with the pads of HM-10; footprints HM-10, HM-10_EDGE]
Designator prefix MOD

## HM-10SMD  [HM-10]
1  1.UART-TX
2  2.UART.RX
3  3.UART-CTS
4  4.UART-RTS
5  5
6  6
7  7.CC-CLK
8  8.CC-DAT
9  9
10  10
11  11.CC-RESET
12  12.VCC
13  13.GND
14  14.GND
15  15.SDA
16  16
17  17
18  18
19  19
20  20.SCL
21  21.GND
22  22.GND
23  23.PIO0
24  24.PIO1
25  25.PIO2
26  26.PIO3
27  27.PIO4
28  28.PIO5
29  29.PIO6
30  30.PIO7
31  31.PIO8
32  32.PIO9
33  33.PIO10
34  34.PIO11

## HM-10EDGE  [HM-10_EDGE]
Pads as for HM-10

## Footprint HM-10 (pad centres in mm)
smd 2 x 1: 1 -6.5,6.34; 2 -6.5,4.84; 3 -6.5,3.34; 4 -6.5,1.84; 5 -6.5,0.34; 6 -6.5,-1.16; 7 -6.5,-2.66; 8 -6.5,-4.16; 9 -6.5,-5.66; 10 -6.5,-7.16; 11 -6.5,-8.66; 12 -6.5,-10.16; 13 -6.5,-11.66; 22 6.5,-11.66; 23 6.5,-10.16; 24 6.5,-8.66; 25 6.5,-7.16; 26 6.5,-5.66; 27 6.5,-4.16; 28 6.5,-2.66; 29 6.5,-1.16; 30 6.5,0.34; 31 6.5,1.84; 32 6.5,3.34; 33 6.5,4.84; 34 6.5,6.34
smd 1 x 2: 14 -5.23,-13.45; 15 -3.73,-13.45; 16 -2.23,-13.45; 17 -0.73,-13.45; 18 0.77,-13.45; 19 2.27,-13.45; 20 3.77,-13.45; 21 5.27,-13.45

## Footprint HM-10_EDGE (pad centres in mm)
smd 2 x 1: 1 -6.5,6.34; 2 -6.5,4.84; 3 -6.5,3.34; 4 -6.5,1.84; 5 -6.5,0.34; 6 -6.5,-1.16; 7 -6.5,-2.66; 8 -6.5,-4.16; 9 -6.5,-5.66; 10 -6.5,-7.16; 11 -6.5,-8.66; 12 -6.5,-10.16; 13 -6.5,-11.66; 22 6.5,-11.66; 23 6.5,-10.16; 24 6.5,-8.66; 25 6.5,-7.16; 26 6.5,-5.66; 27 6.5,-4.16; 28 6.5,-2.66; 29 6.5,-1.16; 30 6.5,0.34; 31 6.5,1.84; 32 6.5,3.34; 33 6.5,4.84; 34 6.5,6.34
smd 1 x 2: 14 -5.23,-13.45; 15 -3.73,-13.45; 16 -2.23,-13.45; 17 -0.73,-13.45; 18 0.77,-13.45; 19 2.27,-13.45; 20 3.77,-13.45; 21 5.27,-13.45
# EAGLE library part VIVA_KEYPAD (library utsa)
Capacitance keypad for the VIVA PIC16

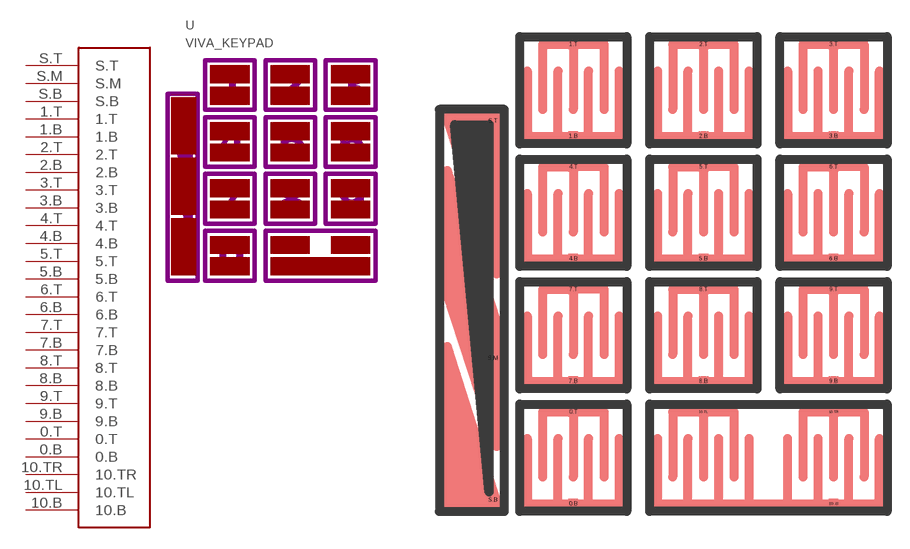
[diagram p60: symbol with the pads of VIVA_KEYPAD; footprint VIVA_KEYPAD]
Designator prefix -

## VIVA_KEYPAD  [VIVA_KEYPAD]
0.B  0.B
0.T  0.T
1.B  1.B
1.T  1.T
2.B  2.B
2.T  2.T
3.B  3.B
3.T  3.T
4.B  4.B
4.T  4.T
5.B  5.B
5.T  5.T
6.B  6.B
6.T  6.T
7.B  7.B
7.T  7.T
8.B  8.B
8.T  8.T
9.B  9.B
9.T  9.T
10.B  10.B
10.TL  10.TL
10.TR  10.TR
S.B  S.B
S.M  S.M
S.T  S.T

## Footprint VIVA_KEYPAD (pad centres in mm)
smd 0.635 x 0.635: 0.B 8.89,0.254; 0.T 8.89,6.35; 1.B 8.89,24.638; 1.T 8.89,30.734; 2.B 17.526,24.638; 2.T 17.526,30.734; 3.B 26.162,24.638; 3.T 26.162,30.734; 4.B 8.89,16.51; 4.T 8.89,22.606; 5.B 17.526,16.51; 5.T 17.526,22.606; 6.B 26.162,16.51; 6.T 26.162,22.606; 7.B 8.89,8.382; 7.T 8.89,14.478; 8.B 17.526,8.382; 8.T 17.526,14.478; 9.B 26.162,8.382; 9.T 26.162,14.478; 10.B 26.162,0.254; 10.TL 17.526,6.35; 10.TR 26.162,6.35; S.B 3.556,0.508; S.M 3.556,9.906; S.T 3.556,25.654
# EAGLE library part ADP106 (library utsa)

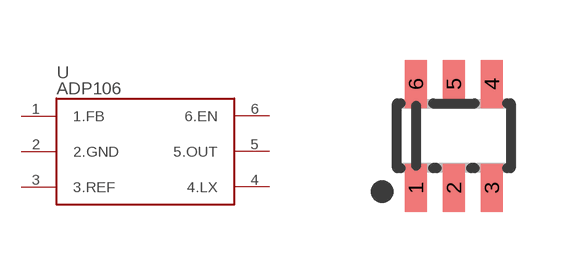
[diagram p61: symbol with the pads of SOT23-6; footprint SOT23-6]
Designator prefix U

## ADP106  [SOT23-6]
1  1.FB
2  2.GND
3  3.REF
4  4.LX
5  5.OUT
6  6.EN

## Footprint SOT23-6 (pad centres in mm)
smd 0.55 x 1.2: 1 -0.95,-1.3; 2 0,-1.3; 3 0.95,-1.3; 4 0.95,1.3; 5 0,1.3; 6 -0.95,1.3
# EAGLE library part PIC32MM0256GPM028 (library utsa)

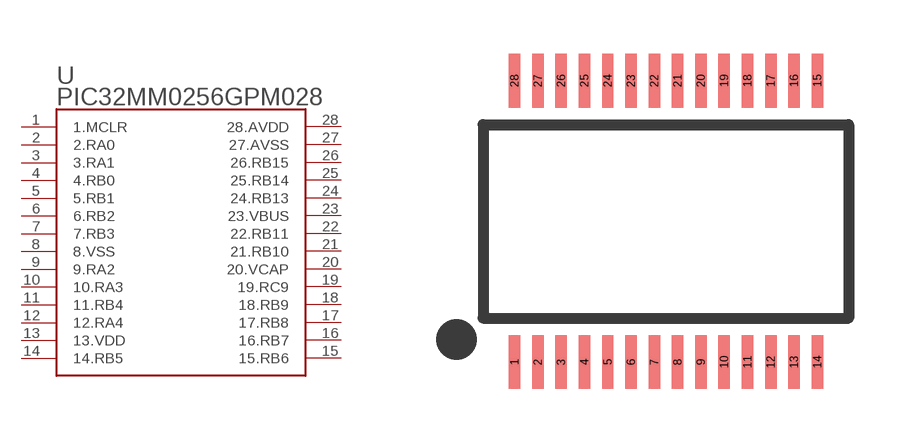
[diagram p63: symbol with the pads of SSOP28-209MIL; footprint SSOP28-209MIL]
Designator prefix -

## PIC32MM0256GPM028  [SSOP28-209MIL]
1  1.MCLR
2  2.RA0
3  3.RA1
4  4.RB0
5  5.RB1
6  6.RB2
7  7.RB3
8  8.VSS
9  9.RA2
10  10.RA3
11  11.RB4
12  12.RA4
13  13.VDD
14  14.RB5
15  15.RB6
16  16.RB7
17  17.RB8
18  18.RB9
19  19.RC9
20  20.VCAP
21  21.RB10
22  22.RB11
23  23.VBUS
24  24.RB13
25  25.RB14
26  26.RB15
27  27.AVSS
28  28.AVDD

## Footprint SSOP28-209MIL (pad centres in mm)
smd 0.32 x 1.5: 1 -4.225,-3.925; 2 -3.575,-3.925; 3 -2.925,-3.925; 4 -2.275,-3.925; 5 -1.625,-3.925; 6 -0.975,-3.925; 7 -0.325,-3.925; 8 0.325,-3.925; 9 0.975,-3.925; 10 1.625,-3.925; 11 2.275,-3.925; 12 2.925,-3.925; 13 3.575,-3.925; 14 4.225,-3.925; 15 4.225,3.925; 16 3.575,3.925; 17 2.925,3.925; 18 2.275,3.925; 19 1.625,3.925; 20 0.975,3.925; 21 0.325,3.925; 22 -0.325,3.925; 23 -0.975,3.925; 24 -1.625,3.925; 25 -2.275,3.925; 26 -2.925,3.925; 27 -3.575,3.925; 28 -4.225,3.925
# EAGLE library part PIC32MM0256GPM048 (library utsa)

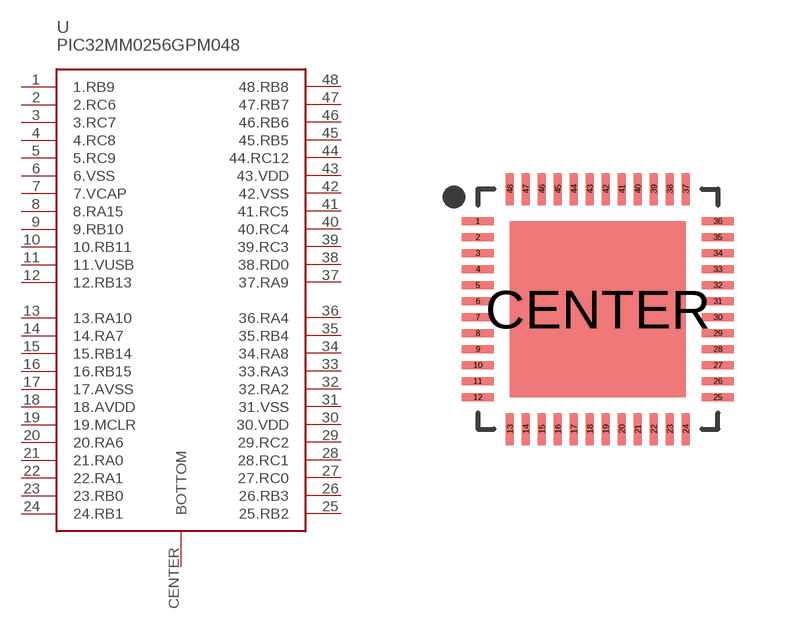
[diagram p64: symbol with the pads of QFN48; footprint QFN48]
Designator prefix -

## PIC32MM0256GPM048  [QFN48]
1  1.RB9
2  2.RC6
3  3.RC7
4  4.RC8
5  5.RC9
6  6.VSS
7  7.VCAP
8  8.RA15
9  9.RB10
10  10.RB11
11  11.VUSB
12  12.RB13
13  13.RA10
14  14.RA7
15  15.RB14
16  16.RB15
17  17.AVSS
18  18.AVDD
19  19.MCLR
20  20.RA6
21  21.RA0
22  22.RA1
23  23.RB0
24  24.RB1
25  25.RB2
26  26.RB3
27  27.RC0
28  28.RC1
29  29.RC2
30  30.VDD
31  31.VSS
32  32.RA2
33  33.RA3
34  34.RA8
35  35.RB4
36  36.RA4
37  37.RA9
38  38.RD0
39  39.RC3
40  40.RC4
41  41.RC5
42  42.VSS
43  43.VDD
44  44.RC12
45  45.RB5
46  46.RB6
47  47.RB7
48  48.RB8
CENTER  BOTTOM

## Footprint QFN48 (pad centres in mm)
smd 0.8 x 0.2: 1 -3,2.2; 2 -3,1.8; 3 -3,1.4; 4 -3,1; 5 -3,0.6; 6 -3,0.2; 7 -3,-0.2; 8 -3,-0.6; 9 -3,-1; 10 -3,-1.4; 11 -3,-1.8; 12 -3,-2.2; 25 3,-2.2; 26 3,-1.8; 27 3,-1.4; 28 3,-1; 29 3,-0.6; 30 3,-0.2; 31 3,0.2; 32 3,0.6; 33 3,1; 34 3,1.4; 35 3,1.8; 36 3,2.2
smd 0.2 x 0.8: 13 -2.2,-3; 14 -1.8,-3; 15 -1.4,-3; 16 -1,-3; 17 -0.6,-3; 18 -0.2,-3; 19 0.2,-3; 20 0.6,-3; 21 1,-3; 22 1.4,-3; 23 1.8,-3; 24 2.2,-3; 37 2.2,3; 38 1.8,3; 39 1.4,3; 40 1,3; 41 0.6,3; 42 0.2,3; 43 -0.2,3; 44 -0.6,3; 45 -1,3; 46 -1.4,3; 47 -1.8,3; 48 -2.2,3
smd 4.4 x 4.4: CENTER 0,0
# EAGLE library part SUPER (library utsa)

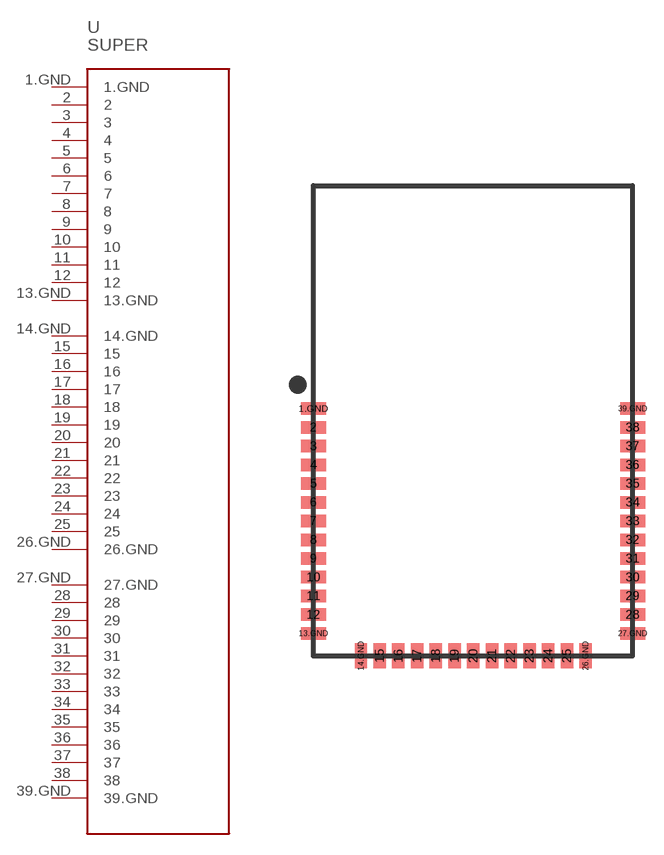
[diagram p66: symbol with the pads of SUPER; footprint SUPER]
Designator prefix -

## SUPER  [SUPER]
1.GND  1.GND
2  2
3  3
4  4
5  5
6  6
7  7
8  8
9  9
10  10
11  11
12  12
13.GND  13.GND
14.GND  14.GND
15  15
16  16
17  17
18  18
19  19
20  20
21  21
22  22
23  23
24  24
25  25
26.GND  26.GND
27.GND  27.GND
28  28
29  29
30  30
31  31
32  32
33  33
34  34
35  35
36  36
37  37
38  38
39.GND  39.GND

## Footprint SUPER (pad centres in mm)
smd 2 x 1: 1.GND -12.79,8.59; 2 -12.79,7.09; 3 -12.79,5.59; 4 -12.79,4.09; 5 -12.79,2.59; 6 -12.79,1.09; 7 -12.79,-0.41; 8 -12.79,-1.91; 9 -12.79,-3.41; 10 -12.79,-4.91; 11 -12.79,-6.41; 12 -12.79,-7.91; 13.GND -12.79,-9.41; 27.GND 12.79,-9.41; 28 12.79,-7.91; 29 12.79,-6.41; 30 12.79,-4.91; 31 12.79,-3.41; 32 12.79,-1.91; 33 12.79,-0.41; 34 12.79,1.09; 35 12.79,2.59; 36 12.79,4.09; 37 12.79,5.59; 38 12.79,7.09; 39.GND 12.79,8.59
smd 1 x 2: 14.GND -8.98,-11.2; 15 -7.48,-11.2; 16 -5.98,-11.2; 17 -4.48,-11.2; 18 -2.98,-11.2; 19 -1.48,-11.2; 20 0.02,-11.2; 21 1.52,-11.2; 22 3.02,-11.2; 23 4.52,-11.2; 24 6.02,-11.2; 25 7.52,-11.2; 26.GND 9.02,-11.2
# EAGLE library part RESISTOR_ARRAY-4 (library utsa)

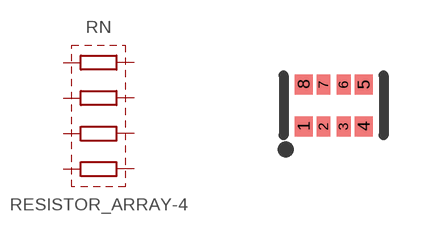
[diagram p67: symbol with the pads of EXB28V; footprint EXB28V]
Designator prefix RN

## RESISTOR_ARRAY-4  [EXB28V]
1  1
2  2
3  3
4  4
5  5
6  6
7  7
8  8

## Footprint EXB28V (pad centres in mm)
smd 0.45 x 0.5: 1 -0.75,-0.525; 4 0.75,-0.525; 5 0.75,0.525; 8 -0.75,0.525
smd 0.35 x 0.5: 2 -0.25,-0.525; 3 0.25,-0.525; 6 0.25,0.525; 7 -0.25,0.525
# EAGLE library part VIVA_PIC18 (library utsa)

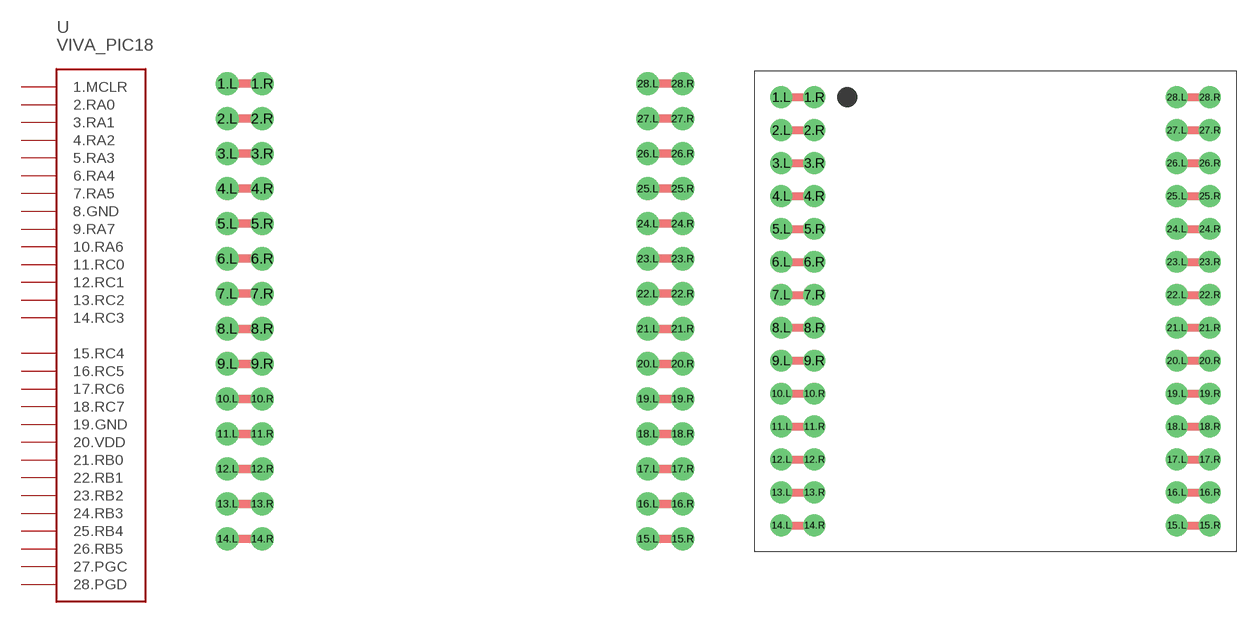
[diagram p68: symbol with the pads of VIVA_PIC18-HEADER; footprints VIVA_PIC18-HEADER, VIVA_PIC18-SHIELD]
Designator prefix -

## VIVA_PIC18BRD  [VIVA_PIC18-HEADER]
1.L  1.MCLR
1.R  1.MCLR
2.L  2.RA0
2.R  2.RA0
3.L  3.RA1
3.R  3.RA1
4.L  4.RA2
4.R  4.RA2
5.L  5.RA3
5.R  5.RA3
6.L  6.RA4
6.R  6.RA4
7.L  7.RA5
7.R  7.RA5
8.L  8.GND
8.R  8.GND
9.L  9.RA7
9.R  9.RA7
10.L  10.RA6
10.R  10.RA6
11.L  11.RC0
11.R  11.RC0
12.L  12.RC1
12.R  12.RC1
13.L  13.RC2
13.R  13.RC2
14.L  14.RC3
14.R  14.RC3
15.L  15.RC4
15.R  15.RC4
16.L  16.RC5
16.R  16.RC5
17.L  17.RC6
17.R  17.RC6
18.L  18.RC7
18.R  18.RC7
19.L  19.GND
19.R  19.GND
20.L  20.VDD
20.R  20.VDD
21.L  21.RB0
21.R  21.RB0
22.L  22.RB1
22.R  22.RB1
23.L  23.RB2
23.R  23.RB2
24.L  24.RB3
24.R  24.RB3
25.L  25.RB4
25.R  25.RB4
26.L  26.RB5
26.R  26.RB5
27.L  27.PGC
27.R  27.PGC
28.L  28.PGD
28.R  28.PGD

## VIVA_PIC18SHD  [VIVA_PIC18-SHIELD]
Pads as for VIVA_PIC18-HEADER

## Footprint VIVA_PIC18-HEADER (pad centres in mm)
drill 1.1 pad 1.676: 1.L -2.54,0; 1.R 0,0; 2.L -2.54,-2.54; 2.R 0,-2.54; 3.L -2.54,-5.08; 3.R 0,-5.08; 4.L -2.54,-7.62; 4.R 0,-7.62; 5.L -2.54,-10.16; 5.R 0,-10.16; 6.L -2.54,-12.7; 6.R 0,-12.7; 7.L -2.54,-15.24; 7.R 0,-15.24; 8.L -2.54,-17.78; 8.R 0,-17.78; 9.L -2.54,-20.32; 9.R 0,-20.32; 10.L -2.54,-22.86; 10.R 0,-22.86; 11.L -2.54,-25.4; 11.R 0,-25.4; 12.L -2.54,-27.94; 12.R 0,-27.94; 13.L -2.54,-30.48; 13.R 0,-30.48; 14.L -2.54,-33.02; 14.R 0,-33.02; 15.L 27.94,-33.02; 15.R 30.48,-33.02; 16.L 27.94,-30.48; 16.R 30.48,-30.48; 17.L 27.94,-27.94; 17.R 30.48,-27.94; 18.L 27.94,-25.4; 18.R 30.48,-25.4; 19.L 27.94,-22.86; 19.R 30.48,-22.86; 20.L 27.94,-20.32; 20.R 30.48,-20.32; 21.L 27.94,-17.78; 21.R 30.48,-17.78; 22.L 27.94,-15.24; 22.R 30.48,-15.24; 23.L 27.94,-12.7; 23.R 30.48,-12.7; 24.L 27.94,-10.16; 24.R 30.48,-10.16; 25.L 27.94,-7.62; 25.R 30.48,-7.62; 26.L 27.94,-5.08; 26.R 30.48,-5.08; 27.L 27.94,-2.54; 27.R 30.48,-2.54; 28.L 27.94,0; 28.R 30.48,0

## Footprint VIVA_PIC18-SHIELD (pad centres in mm)
drill 1.1 pad 1.676: 1.L -2.54,0; 1.R 0,0; 2.L -2.54,-2.54; 2.R 0,-2.54; 3.L -2.54,-5.08; 3.R 0,-5.08; 4.L -2.54,-7.62; 4.R 0,-7.62; 5.L -2.54,-10.16; 5.R 0,-10.16; 6.L -2.54,-12.7; 6.R 0,-12.7; 7.L -2.54,-15.24; 7.R 0,-15.24; 8.L -2.54,-17.78; 8.R 0,-17.78; 9.L -2.54,-20.32; 9.R 0,-20.32; 10.L -2.54,-22.86; 10.R 0,-22.86; 11.L -2.54,-25.4; 11.R 0,-25.4; 12.L -2.54,-27.94; 12.R 0,-27.94; 13.L -2.54,-30.48; 13.R 0,-30.48; 14.L -2.54,-33.02; 14.R 0,-33.02; 15.L 27.94,-33.02; 15.R 30.48,-33.02; 16.L 27.94,-30.48; 16.R 30.48,-30.48; 17.L 27.94,-27.94; 17.R 30.48,-27.94; 18.L 27.94,-25.4; 18.R 30.48,-25.4; 19.L 27.94,-22.86; 19.R 30.48,-22.86; 20.L 27.94,-20.32; 20.R 30.48,-20.32; 21.L 27.94,-17.78; 21.R 30.48,-17.78; 22.L 27.94,-15.24; 22.R 30.48,-15.24; 23.L 27.94,-12.7; 23.R 30.48,-12.7; 24.L 27.94,-10.16; 24.R 30.48,-10.16; 25.L 27.94,-7.62; 25.R 30.48,-7.62; 26.L 27.94,-5.08; 26.R 30.48,-5.08; 27.L 27.94,-2.54; 27.R 30.48,-2.54; 28.L 27.94,0; 28.R 30.48,0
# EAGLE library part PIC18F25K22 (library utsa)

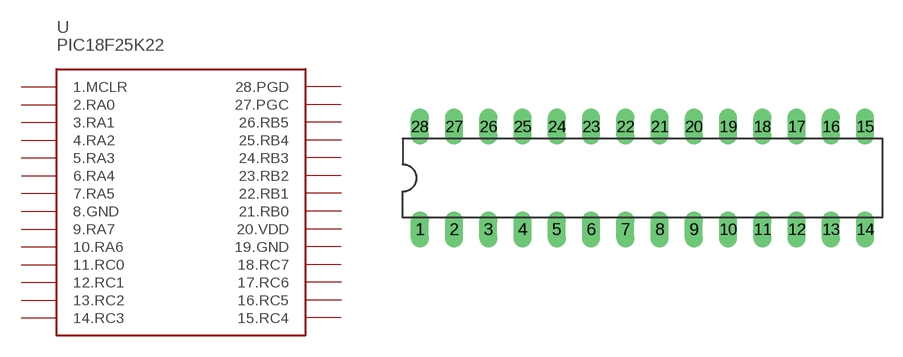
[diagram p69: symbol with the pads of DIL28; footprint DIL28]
Designator prefix -

## PIC18F25K22  [DIL28]
1  1.MCLR
2  2.RA0
3  3.RA1
4  4.RA2
5  5.RA3
6  6.RA4
7  7.RA5
8  8.GND
9  9.RA7
10  10.RA6
11  11.RC0
12  12.RC1
13  13.RC2
14  14.RC3
15  15.RC4
16  16.RC5
17  17.RC6
18  18.RC7
19  19.GND
20  20.VDD
21  21.RB0
22  22.RB1
23  23.RB2
24  24.RB3
25  25.RB4
26  26.RB5
27  27.PGC
28  28.PGD

## Footprint DIL28 (pad centres in mm)
drill 0.813 long: 1 -16.51,-3.81; 2 -13.97,-3.81; 3 -11.43,-3.81; 4 -8.89,-3.81; 5 -6.35,-3.81; 6 -3.81,-3.81; 7 -1.27,-3.81; 8 1.27,-3.81; 9 3.81,-3.81; 10 6.35,-3.81; 11 8.89,-3.81; 12 11.43,-3.81; 13 13.97,-3.81; 14 16.51,-3.81; 15 16.51,3.81; 16 13.97,3.81; 17 11.43,3.81; 18 8.89,3.81; 19 6.35,3.81; 20 3.81,3.81; 21 1.27,3.81; 22 -1.27,3.81; 23 -3.81,3.81; 24 -6.35,3.81; 25 -8.89,3.81; 26 -11.43,3.81; 27 -13.97,3.81; 28 -16.51,3.81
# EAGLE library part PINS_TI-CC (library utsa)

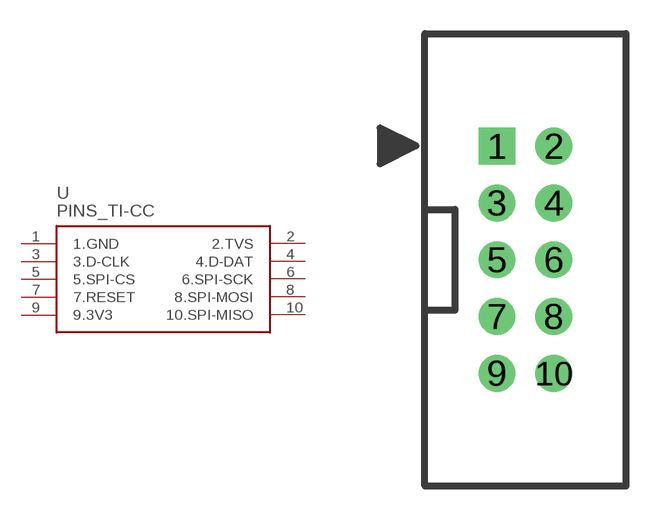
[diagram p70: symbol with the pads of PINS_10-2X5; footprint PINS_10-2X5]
Designator prefix -

## PINS_TI-CC  [PINS_10-2X5]
1  1.GND
2  2.TVS
3  3.D-CLK
4  4.D-DAT
5  5.SPI-CS
6  6.SPI-SCK
7  7.RESET
8  8.SPI-MOSI
9  9.3V3
10  10.SPI-MISO

## Footprint PINS_10-2X5 (pad centres in mm)
drill 1.1 square: 1 -1.27,5.08
drill 1.1: 2 1.27,5.08; 3 -1.27,2.54; 4 1.27,2.54; 5 -1.27,0; 6 1.27,0; 7 -1.27,-2.54; 8 1.27,-2.54; 9 -1.27,-5.08; 10 1.27,-5.08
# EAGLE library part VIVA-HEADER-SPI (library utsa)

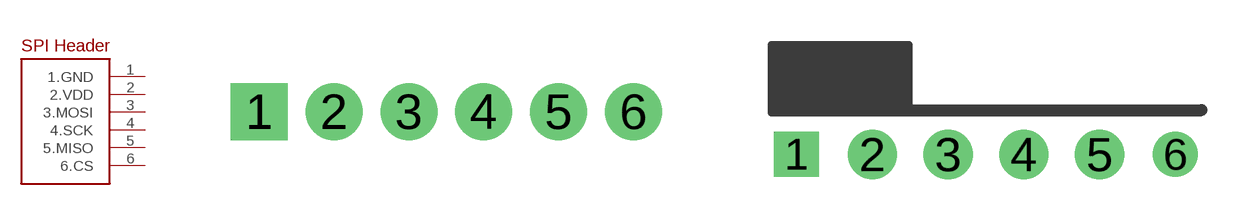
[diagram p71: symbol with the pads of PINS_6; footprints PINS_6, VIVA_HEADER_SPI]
Designator prefix -

## VIVA-HEADER-SPI-XS  [PINS_6]
1  1.GND
2  2.VDD
3  3.MOSI
4  4.SCK
5  5.MISO
6  6.CS

## VIVA-HEADER-SPI-S  [VIVA_HEADER_SPI]
Pads as for PINS_6

## VIVA-HEADER-SPI-RA  [VIVA-HEADER-SPI-RA]
Pads as for PINS_6

## Footprint PINS_6 (pad centres in mm)
drill 1.1 pad 1.93 square: 1 0,0
drill 1.1 pad 1.93: 2 2.54,0; 3 5.08,0; 4 7.62,0; 5 10.16,0; 6 12.7,0

## Footprint VIVA_HEADER_SPI (pad centres in mm)
drill 1 square: 1 0,0
drill 1.1: 2 2.54,0; 3 5.08,0; 4 7.62,0; 5 10.16,0
drill 1: 6 12.7,0

## Footprint VIVA-HEADER-SPI-RA (pad centres in mm)
drill 1 square: 1 0,0
drill 1.1: 2 2.54,0; 3 5.08,0; 4 7.62,0; 5 10.16,0
drill 1: 6 12.7,0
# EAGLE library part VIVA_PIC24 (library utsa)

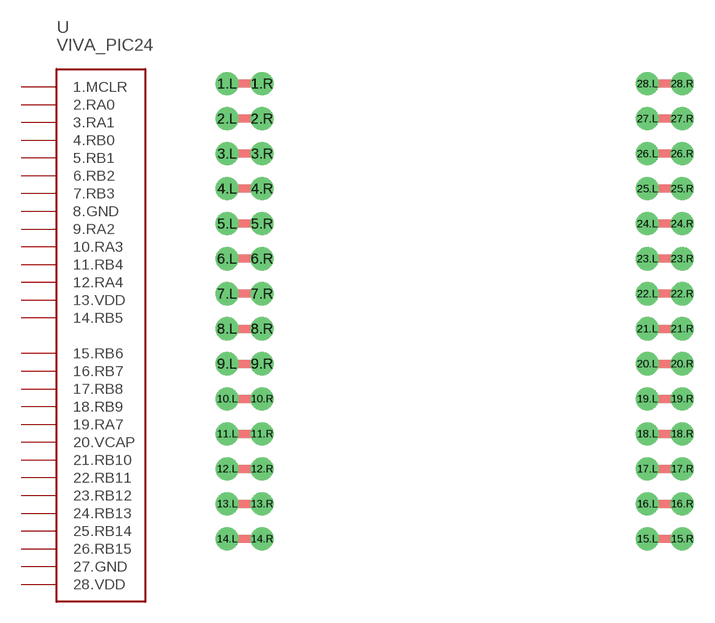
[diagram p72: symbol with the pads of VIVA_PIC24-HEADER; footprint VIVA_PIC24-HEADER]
Designator prefix -

## VIVA_PIC24  [VIVA_PIC24-HEADER]
1.L  1.MCLR
1.R  1.MCLR
2.L  2.RA0
2.R  2.RA0
3.L  3.RA1
3.R  3.RA1
4.L  4.RB0
4.R  4.RB0
5.L  5.RB1
5.R  5.RB1
6.L  6.RB2
6.R  6.RB2
7.L  7.RB3
7.R  7.RB3
8.L  8.GND
8.R  8.GND
9.L  9.RA2
9.R  9.RA2
10.L  10.RA3
10.R  10.RA3
11.L  11.RB4
11.R  11.RB4
12.L  12.RA4
12.R  12.RA4
13.L  13.VDD
13.R  13.VDD
14.L  14.RB5
14.R  14.RB5
15.L  15.RB6
15.R  15.RB6
16.L  16.RB7
16.R  16.RB7
17.L  17.RB8
17.R  17.RB8
18.L  18.RB9
18.R  18.RB9
19.L  19.RA7
19.R  19.RA7
20.L  20.VCAP
20.R  20.VCAP
21.L  21.RB10
21.R  21.RB10
22.L  22.RB11
22.R  22.RB11
23.L  23.RB12
23.R  23.RB12
24.L  24.RB13
24.R  24.RB13
25.L  25.RB14
25.R  25.RB14
26.L  26.RB15
26.R  26.RB15
27.L  27.GND
27.R  27.GND
28.L  28.VDD
28.R  28.VDD

## Footprint VIVA_PIC24-HEADER (pad centres in mm)
drill 1.1 pad 1.676: 1.L -2.54,0; 1.R 0,0; 2.L -2.54,-2.54; 2.R 0,-2.54; 3.L -2.54,-5.08; 3.R 0,-5.08; 4.L -2.54,-7.62; 4.R 0,-7.62; 5.L -2.54,-10.16; 5.R 0,-10.16; 6.L -2.54,-12.7; 6.R 0,-12.7; 7.L -2.54,-15.24; 7.R 0,-15.24; 8.L -2.54,-17.78; 8.R 0,-17.78; 9.L -2.54,-20.32; 9.R 0,-20.32; 10.L -2.54,-22.86; 10.R 0,-22.86; 11.L -2.54,-25.4; 11.R 0,-25.4; 12.L -2.54,-27.94; 12.R 0,-27.94; 13.L -2.54,-30.48; 13.R 0,-30.48; 14.L -2.54,-33.02; 14.R 0,-33.02; 15.L 27.94,-33.02; 15.R 30.48,-33.02; 16.L 27.94,-30.48; 16.R 30.48,-30.48; 17.L 27.94,-27.94; 17.R 30.48,-27.94; 18.L 27.94,-25.4; 18.R 30.48,-25.4; 19.L 27.94,-22.86; 19.R 30.48,-22.86; 20.L 27.94,-20.32; 20.R 30.48,-20.32; 21.L 27.94,-17.78; 21.R 30.48,-17.78; 22.L 27.94,-15.24; 22.R 30.48,-15.24; 23.L 27.94,-12.7; 23.R 30.48,-12.7; 24.L 27.94,-10.16; 24.R 30.48,-10.16; 25.L 27.94,-7.62; 25.R 30.48,-7.62; 26.L 27.94,-5.08; 26.R 30.48,-5.08; 27.L 27.94,-2.54; 27.R 30.48,-2.54; 28.L 27.94,0; 28.R 30.48,0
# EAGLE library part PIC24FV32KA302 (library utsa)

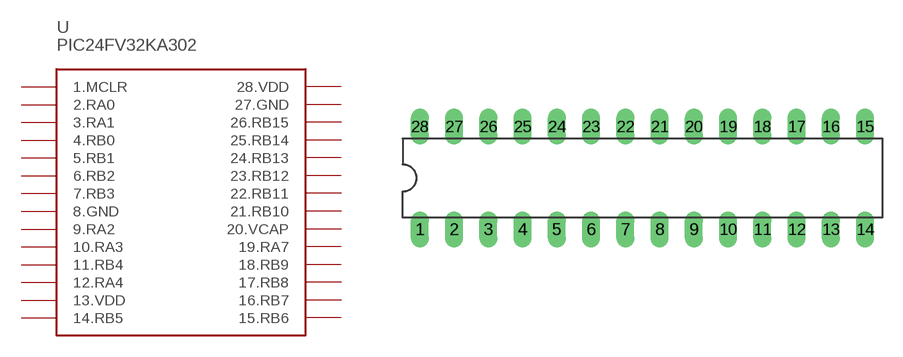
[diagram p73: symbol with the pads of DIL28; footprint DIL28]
Designator prefix -

## PIC24FV32KA302  [DIL28]
1  1.MCLR
2  2.RA0
3  3.RA1
4  4.RB0
5  5.RB1
6  6.RB2
7  7.RB3
8  8.GND
9  9.RA2
10  10.RA3
11  11.RB4
12  12.RA4
13  13.VDD
14  14.RB5
15  15.RB6
16  16.RB7
17  17.RB8
18  18.RB9
19  19.RA7
20  20.VCAP
21  21.RB10
22  22.RB11
23  23.RB12
24  24.RB13
25  25.RB14
26  26.RB15
27  27.GND
28  28.VDD

## Footprint DIL28 (pad centres in mm)
drill 0.813 long: 1 -16.51,-3.81; 2 -13.97,-3.81; 3 -11.43,-3.81; 4 -8.89,-3.81; 5 -6.35,-3.81; 6 -3.81,-3.81; 7 -1.27,-3.81; 8 1.27,-3.81; 9 3.81,-3.81; 10 6.35,-3.81; 11 8.89,-3.81; 12 11.43,-3.81; 13 13.97,-3.81; 14 16.51,-3.81; 15 16.51,3.81; 16 13.97,3.81; 17 11.43,3.81; 18 8.89,3.81; 19 6.35,3.81; 20 3.81,3.81; 21 1.27,3.81; 22 -1.27,3.81; 23 -3.81,3.81; 24 -6.35,3.81; 25 -8.89,3.81; 26 -11.43,3.81; 27 -13.97,3.81; 28 -16.51,3.81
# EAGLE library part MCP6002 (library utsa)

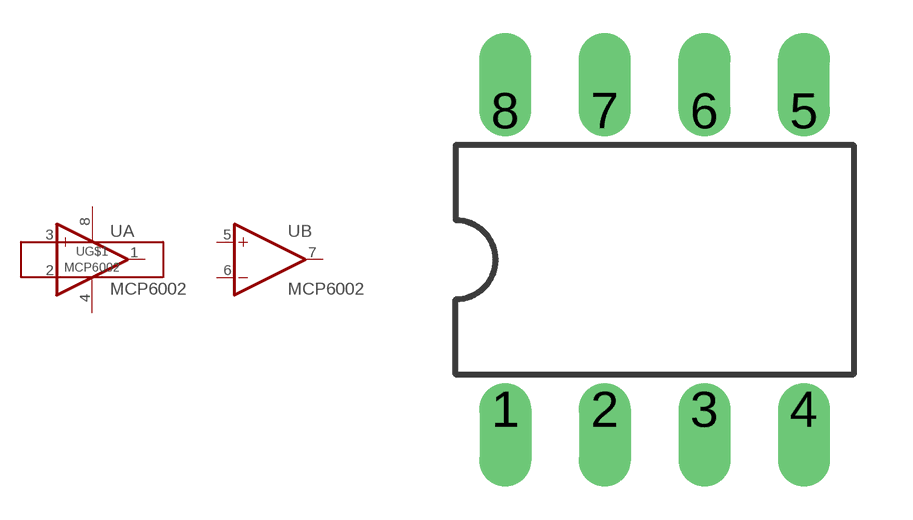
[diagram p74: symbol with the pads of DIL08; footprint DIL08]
Designator prefix -; gates A=OPAMP B=OPAMP G$1=PWR+-

## MCP6002  [DIL08]
1  A:OUT  out
2  A:-IN  in
3  A:+IN  in
4  G$1:V-  pwr
5  B:+IN  in
6  B:-IN  in
7  B:OUT  out
8  G$1:V+  pwr

## Footprint DIL08 (pad centres in mm)
Dual In Line Package
drill 0.813 offset: 1 -3.81,-3.81; 2 -1.27,-3.81; 3 1.27,-3.81; 4 3.81,-3.81; 5 3.81,3.81; 6 1.27,3.81; 7 -1.27,3.81; 8 -3.81,3.81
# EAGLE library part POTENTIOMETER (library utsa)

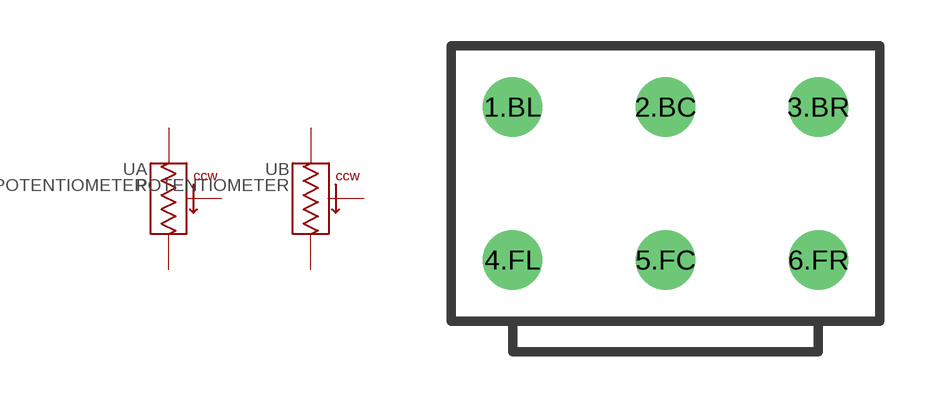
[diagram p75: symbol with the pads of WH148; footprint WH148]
Designator prefix -; gates A=POT B=POT

## POTENTIOMETER  [WH148]
1.BL  B:1.L
2.BC  B:2.C
3.BR  B:3.R
4.FL  A:1.L
5.FC  A:2.C
6.FR  A:3.R

## Footprint WH148 (pad centres in mm)
drill 1.3: 1.BL -5,5; 2.BC 0,5; 3.BR 5,5; 4.FL -5,0; 5.FC 0,0; 6.FR 5,0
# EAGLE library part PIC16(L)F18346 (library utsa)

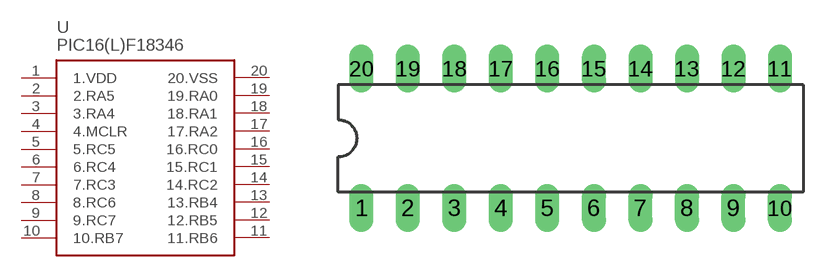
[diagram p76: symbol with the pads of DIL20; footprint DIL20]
Designator prefix -

## PIC16(L)F18346  [DIL20]
1  1.VDD
2  2.RA5
3  3.RA4
4  4.MCLR
5  5.RC5
6  6.RC4
7  7.RC3
8  8.RC6
9  9.RC7
10  10.RB7
11  11.RB6
12  12.RB5
13  13.RB4
14  14.RC2
15  15.RC1
16  16.RC0
17  17.RA2
18  18.RA1
19  19.RA0
20  20.VSS

## Footprint DIL20 (pad centres in mm)
drill 0.813 long: 1 -11.43,-3.81; 2 -8.89,-3.81; 3 -6.35,-3.81; 4 -3.81,-3.81; 5 -1.27,-3.81; 6 1.27,-3.81; 7 3.81,-3.81; 8 6.35,-3.81; 9 8.89,-3.81; 10 11.43,-3.81; 11 11.43,3.81; 12 8.89,3.81; 13 6.35,3.81; 14 3.81,3.81; 15 1.27,3.81; 16 -1.27,3.81; 17 -3.81,3.81; 18 -6.35,3.81; 19 -8.89,3.81; 20 -11.43,3.81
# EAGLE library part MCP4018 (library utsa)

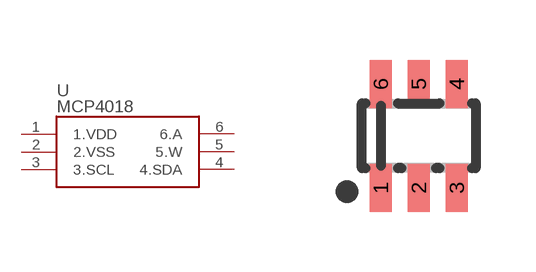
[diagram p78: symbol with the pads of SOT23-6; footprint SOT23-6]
Designator prefix -

## MCP4018  [SOT23-6]
1  1.VDD
2  2.VSS
3  3.SCL
4  4.SDA
5  5.W
6  6.A

## Footprint SOT23-6 (pad centres in mm)
smd 0.55 x 1.2: 1 -0.95,-1.3; 2 0,-1.3; 3 0.95,-1.3; 4 0.95,1.3; 5 0,1.3; 6 -0.95,1.3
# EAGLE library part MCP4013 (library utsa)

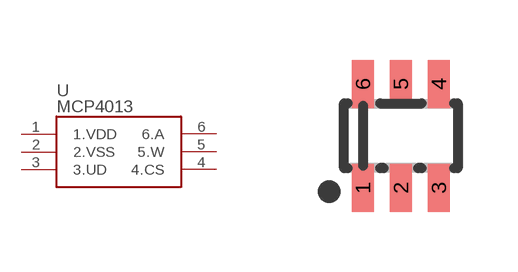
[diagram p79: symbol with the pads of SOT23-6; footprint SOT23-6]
Designator prefix -

## MCP4013  [SOT23-6]
1  1.VDD
2  2.VSS
3  3.UD
4  4.CS
5  5.W
6  6.A

## Footprint SOT23-6 (pad centres in mm)
smd 0.55 x 1.2: 1 -0.95,-1.3; 2 0,-1.3; 3 0.95,-1.3; 4 0.95,1.3; 5 0,1.3; 6 -0.95,1.3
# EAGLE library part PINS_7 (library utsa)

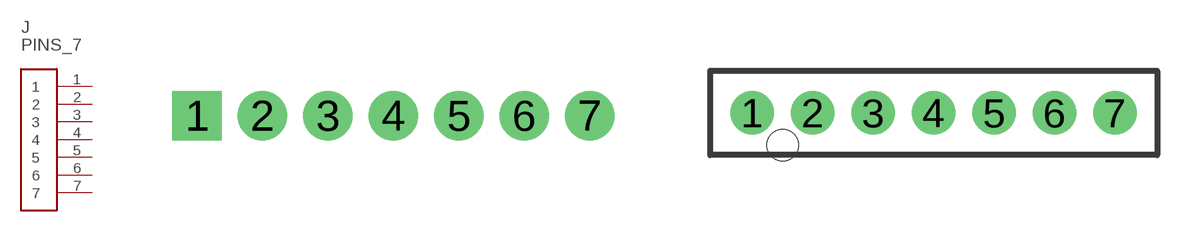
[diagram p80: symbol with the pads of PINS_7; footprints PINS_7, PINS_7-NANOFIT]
Designator prefix J

## PINS_70100  [PINS_7]
1  1
2  2
3  3
4  4
5  5
6  6
7  7

## PINS_7105309-1107  [PINS_7-NANOFIT]
Pads as for PINS_7

## Footprint PINS_7 (pad centres in mm)
drill 1.1 pad 1.93 square: 1 0,0
drill 1.1 pad 1.93: 2 2.54,0; 3 5.08,0; 4 7.62,0; 5 10.16,0; 6 12.7,0; 7 15.24,0

## Footprint PINS_7-NANOFIT (pad centres in mm)
drill 1.2: 1 -7.5,0; 2 -5,0; 3 -2.5,0; 4 0,0; 5 2.5,0; 6 5,0; 7 7.5,0
hole 1.3 at -6.25,-1.34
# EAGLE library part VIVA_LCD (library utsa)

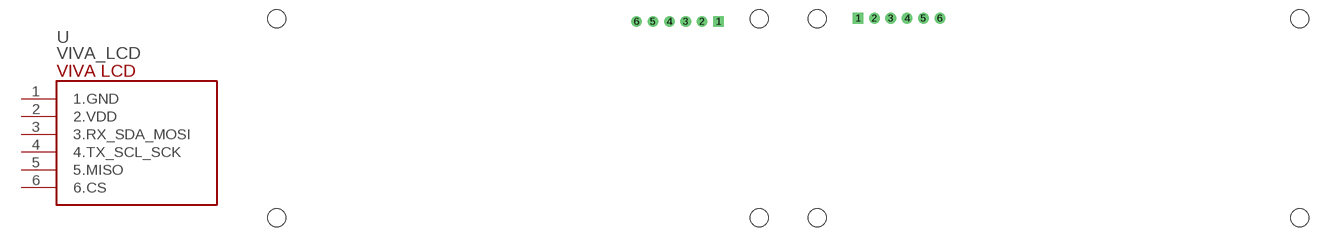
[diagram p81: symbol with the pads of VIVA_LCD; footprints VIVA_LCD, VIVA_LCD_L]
Designator prefix -

## VIVA_LCDR  [VIVA_LCD]
1  1.GND
2  2.VDD
3  3.RX_SDA_MOSI
4  4.TX_SCL_SCK
5  5.MISO
6  6.CS

## VIVA_LCD  [VIVA_LCD_L]
Pads as for VIVA_LCD

## Footprint VIVA_LCD (pad centres in mm)
drill 1.1 square: 1 68.58,30.48
drill 1.1: 2 66.04,30.48; 3 63.5,30.48; 4 60.96,30.48; 5 58.42,30.48; 6 55.88,30.48
hole 2.8 at 0,0
hole 2.8 at 0,30.92
hole 2.8 at 74.92,30.92
hole 2.8 at 74.92,0

## Footprint VIVA_LCD_L (pad centres in mm)
drill 1.1 square: 1 6.35,30.988
drill 1.1: 2 8.89,30.988; 3 11.43,30.988; 4 13.97,30.988; 5 16.51,30.988; 6 19.05,30.988
hole 2.8 at 0,0
hole 2.8 at 0,30.92
hole 2.8 at 74.92,30.92
hole 2.8 at 74.92,0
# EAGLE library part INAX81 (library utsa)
INAx181 Bidirectional, Low- and High-Side Voltage Output, Current-Sense Amplifier

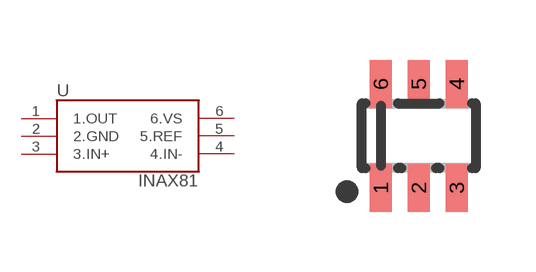
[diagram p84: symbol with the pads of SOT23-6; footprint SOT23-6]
Designator prefix U

## INAX81  [SOT23-6]
1  1.OUT
2  2.GND
3  3.IN+
4  4.IN-
5  5.REF
6  6.VS

## Footprint SOT23-6 (pad centres in mm)
smd 0.55 x 1.2: 1 -0.95,-1.3; 2 0,-1.3; 3 0.95,-1.3; 4 0.95,1.3; 5 0,1.3; 6 -0.95,1.3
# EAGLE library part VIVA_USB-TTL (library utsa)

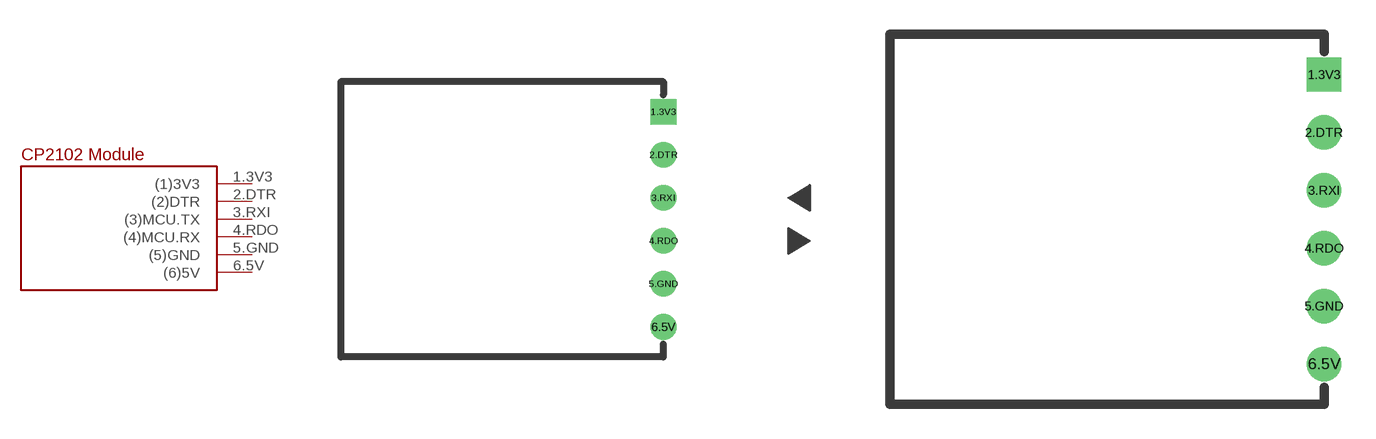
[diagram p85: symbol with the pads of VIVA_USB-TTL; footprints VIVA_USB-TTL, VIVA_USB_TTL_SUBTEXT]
Designator prefix -

## VIVA_USB-TTLTEXT  [VIVA_USB-TTL]
1.3V3  (1)3V3
2.DTR  (2)DTR
3.RXI  (3)MCU.TX
4.RDO  (4)MCU.RX
5.GND  (5)GND
6.5V  (6)5V

## VIVA_USB-TTL  [VIVA_USB_TTL_SUBTEXT]
Pads as for VIVA_USB-TTL

## Footprint VIVA_USB-TTL (pad centres in mm)
drill 1 square: 1.3V3 0,0
drill 1: 2.DTR 0,-2.54; 3.RXI 0,-5.08; 4.RDO 0,-7.62; 5.GND 0,-10.16; 6.5V 0,-12.7

## Footprint VIVA_USB_TTL_SUBTEXT (pad centres in mm)
drill 1 square: 1.3V3 0,0
drill 1: 2.DTR 0,-2.54; 3.RXI 0,-5.08; 4.RDO 0,-7.62; 5.GND 0,-10.16; 6.5V 0,-12.7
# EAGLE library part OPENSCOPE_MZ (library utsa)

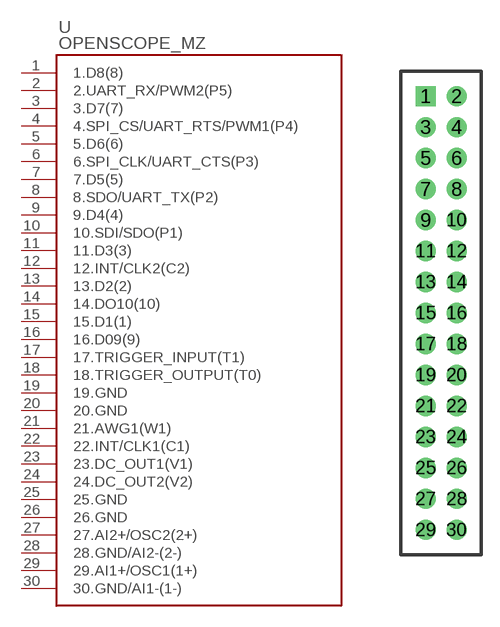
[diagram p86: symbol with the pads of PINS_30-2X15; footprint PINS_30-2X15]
Designator prefix -

## OPENSCOPE_MZ  [PINS_30-2X15]
1  1.D8(8)
2  2.UART_RX/PWM2(P5)
3  3.D7(7)
4  4.SPI_CS/UART_RTS/PWM1(P4)
5  5.D6(6)
6  6.SPI_CLK/UART_CTS(P3)
7  7.D5(5)
8  8.SDO/UART_TX(P2)
9  9.D4(4)
10  10.SDI/SDO(P1)
11  11.D3(3)
12  12.INT/CLK2(C2)
13  13.D2(2)
14  14.DO10(10)
15  15.D1(1)
16  16.D09(9)
17  17.TRIGGER_INPUT(T1)
18  18.TRIGGER_OUTPUT(T0)
19  19.GND
20  20.GND
21  21.AWG1(W1)
22  22.INT/CLK1(C1)
23  23.DC_OUT1(V1)
24  24.DC_OUT2(V2)
25  25.GND
26  26.GND
27  27.AI2+/OSC2(2+)
28  28.GND/AI2-(2-)
29  29.AI1+/OSC1(1+)
30  30.GND/AI1-(1-)

## Footprint PINS_30-2X15 (pad centres in mm)
drill 1.1 square: 1 0,0
drill 1.1: 2 2.54,0; 3 0,-2.54; 4 2.54,-2.54; 5 0,-5.08; 6 2.54,-5.08; 7 0,-7.62; 8 2.54,-7.62; 9 0,-10.16; 10 2.54,-10.16; 11 0,-12.7; 12 2.54,-12.7; 13 0,-15.24; 14 2.54,-15.24; 15 0,-17.78; 16 2.54,-17.78; 17 0,-20.32; 18 2.54,-20.32; 19 0,-22.86; 20 2.54,-22.86; 21 0,-25.4; 22 2.54,-25.4; 23 0,-27.94; 24 2.54,-27.94; 25 0,-30.48; 26 2.54,-30.48; 27 0,-33.02; 28 2.54,-33.02; 29 0,-35.56; 30 2.54,-35.56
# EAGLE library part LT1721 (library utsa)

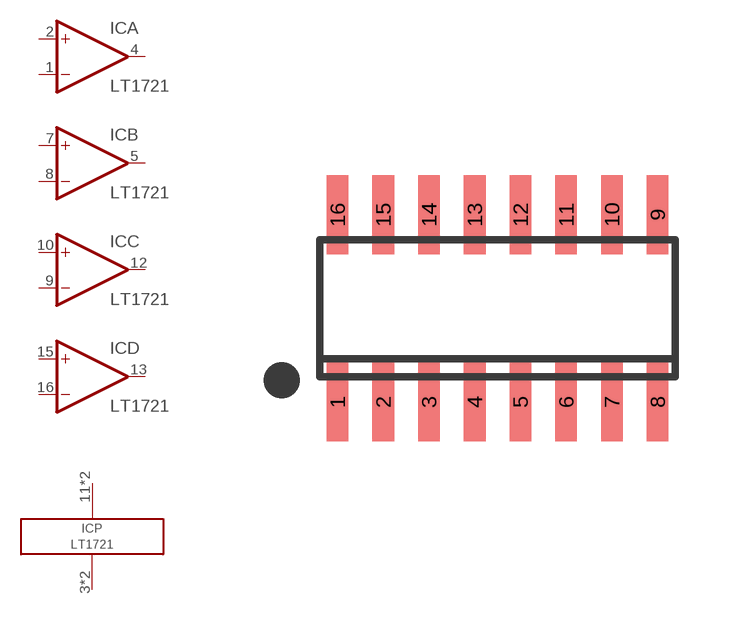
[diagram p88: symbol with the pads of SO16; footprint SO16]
Designator prefix IC; gates A=COMPARATOR B=COMPARATOR C=COMPARATOR D=COMPARATOR P=PWR+-

## LT1721  [SO16]
1  A:-IN  in
2  A:+IN  in
3  P:V-  pwr
4  A:OUT  out
5  B:OUT  out
6  P:V-  pwr
7  B:+IN  in
8  B:-IN  in
9  C:-IN  in
10  C:+IN  in
11  P:V+  pwr
12  C:OUT  out
13  D:OUT  out
14  P:V+  pwr
15  D:+IN  in
16  D:-IN  in

## Footprint SO16 (pad centres in mm)
SMALL OUTLINE INTEGRATED CIRCUIT body 3.9 mm/JEDEC MS-012AC
smd 0.6 x 2.2: 1 -4.445,-2.6; 2 -3.175,-2.6; 3 -1.905,-2.6; 4 -0.635,-2.6; 5 0.635,-2.6; 6 1.905,-2.6; 7 3.175,-2.6; 8 4.445,-2.6; 9 4.445,2.6; 10 3.175,2.6; 11 1.905,2.6; 12 0.635,2.6; 13 -0.635,2.6; 14 -1.905,2.6; 15 -3.175,2.6; 16 -4.445,2.6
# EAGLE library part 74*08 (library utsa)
Quad 2-input AND gate

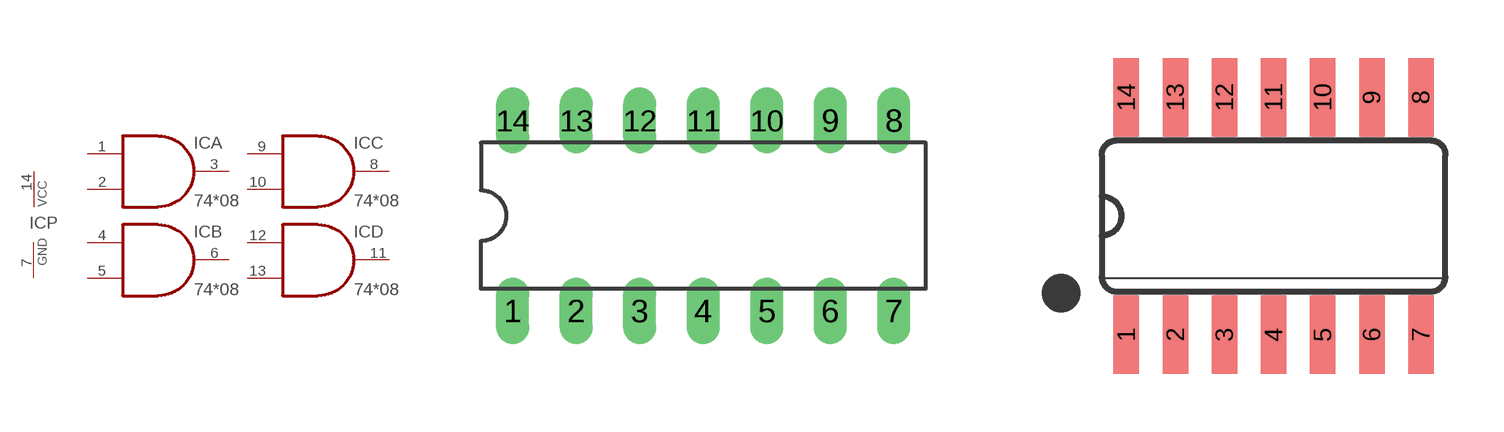
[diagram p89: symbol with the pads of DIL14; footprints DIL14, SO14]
Designator prefix IC; gates A=7408 B=7408 C=7408 D=7408 P=PWRN

## 74AC08N, 74ACT08N, 74ALS08N, 74AS08N, 74HC08N, 74HCT08N, 74LS08N, 74S08N  [DIL14]
1  A:A0  in
2  A:B0  in
3  A:Y0  out
4  B:A0  in
5  B:B0  in
6  B:Y0  out
7  P:GND  pwr
8  C:Y0  out
9  C:A0  in
10  C:B0  in
11  D:Y0  out
12  D:A0  in
13  D:B0  in
14  P:VCC  pwr

## 74AC08D, 74ACT08D, 74ALS08D, 74AS08D, 74HC08D, 74HCT08D, 74LS08D, 74S08D  [SO14]
Pads as for DIL14

## 74AC08FK, 74ACT08FK, 74ALS08FK, 74AS08FK, 74HC08FK, 74HCT08FK, 74LS08FK, 74S08FK  [LCC20]
2  A:A0  in
3  A:B0  in
4  A:Y0  out
6  B:A0  in
8  B:B0  in
9  B:Y0  out
10  P:GND  pwr
12  C:Y0  out
13  C:A0  in
14  C:B0  in
16  D:Y0  out
18  D:A0  in
19  D:B0  in
20  P:VCC  pwr

## Footprint DIL14 (pad centres in mm)
Dual In Line Package
drill 0.813 long: 1 -7.62,-3.81; 2 -5.08,-3.81; 3 -2.54,-3.81; 4 0,-3.81; 5 2.54,-3.81; 6 5.08,-3.81; 7 7.62,-3.81; 8 7.62,3.81; 9 5.08,3.81; 10 2.54,3.81; 11 0,3.81; 12 -2.54,3.81; 13 -5.08,3.81; 14 -7.62,3.81

## Footprint SO14 (pad centres in mm)
Small Outline package 150 mil
smd 0.66 x 2.032: 1 -3.81,-3.073; 2 -2.54,-3.073; 3 -1.27,-3.073; 4 0,-3.073; 5 1.27,-3.073; 6 2.54,-3.073; 7 3.81,-3.073; 8 3.81,3.073; 9 2.54,3.073; 10 1.27,3.073; 11 0,3.073; 12 -1.27,3.073; 13 -2.54,3.073; 14 -3.81,3.073

## Footprint LCC20 (pad centres in mm)
Leadless Chip Carrier Ceramic Package
smd 0.8 x 3.4: 1 0,3.8
smd 0.8 x 2: 2 -1.27,4.5; 3 -2.54,4.5; 9 -2.54,-4.5; 10 -1.27,-4.5; 11 0,-4.5; 12 1.27,-4.5; 13 2.54,-4.5; 19 2.54,4.5; 20 1.27,4.5
smd 2 x 0.8: 4 -4.5,2.54; 5 -4.5,1.27; 6 -4.5,0; 7 -4.5,-1.27; 8 -4.5,-2.54; 14 4.5,-2.54; 15 4.5,-1.27; 16 4.5,0; 17 4.5,1.27; 18 4.5,2.54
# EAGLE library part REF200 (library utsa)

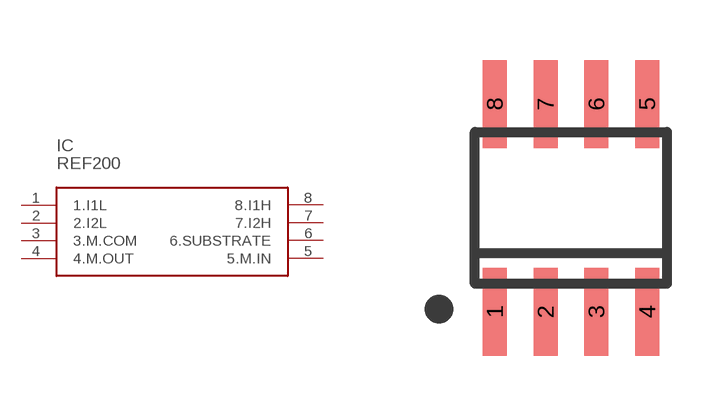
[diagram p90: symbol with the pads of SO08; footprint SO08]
Designator prefix IC

## REF200  [SO08]
1  1.I1L
2  2.I2L
3  3.M.COM
4  4.M.OUT
5  5.M.IN
6  6.SUBSTRATE
7  7.I2H
8  8.I1H

## Footprint SO08 (pad centres in mm)
SMALL OUTLINE INTEGRATED CIRCUIT body 3.9 mm/JEDEC MS-012AA
smd 0.6 x 2.2: 1 -1.905,-2.6; 2 -0.635,-2.6; 3 0.635,-2.6; 4 1.905,-2.6; 5 1.905,2.6; 6 0.635,2.6; 7 -0.635,2.6; 8 -1.905,2.6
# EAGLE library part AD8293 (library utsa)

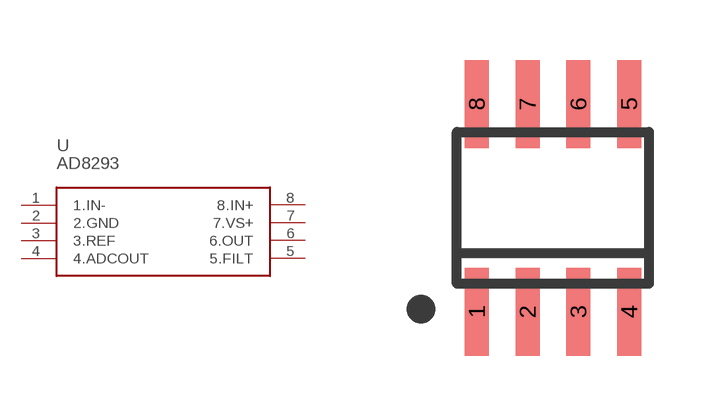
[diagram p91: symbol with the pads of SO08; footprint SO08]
Designator prefix -

## AD8293  [SO08]
1  1.IN-
2  2.GND
3  3.REF
4  4.ADCOUT
5  5.FILT
6  6.OUT
7  7.VS+
8  8.IN+

## Footprint SO08 (pad centres in mm)
SMALL OUTLINE INTEGRATED CIRCUIT body 3.9 mm/JEDEC MS-012AA
smd 0.6 x 2.2: 1 -1.905,-2.6; 2 -0.635,-2.6; 3 0.635,-2.6; 4 1.905,-2.6; 5 1.905,2.6; 6 0.635,2.6; 7 -0.635,2.6; 8 -1.905,2.6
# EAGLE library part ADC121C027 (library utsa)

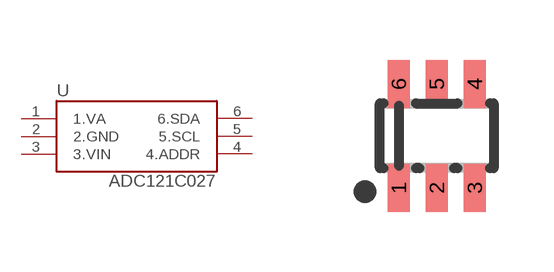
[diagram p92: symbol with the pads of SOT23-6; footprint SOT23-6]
Designator prefix U

## ADC121C027CIMK  [SOT23-6]
1  1.VA
2  2.GND
3  3.VIN
4  4.ADDR
5  5.SCL
6  6.SDA

## Footprint SOT23-6 (pad centres in mm)
smd 0.55 x 1.2: 1 -0.95,-1.3; 2 0,-1.3; 3 0.95,-1.3; 4 0.95,1.3; 5 0,1.3; 6 -0.95,1.3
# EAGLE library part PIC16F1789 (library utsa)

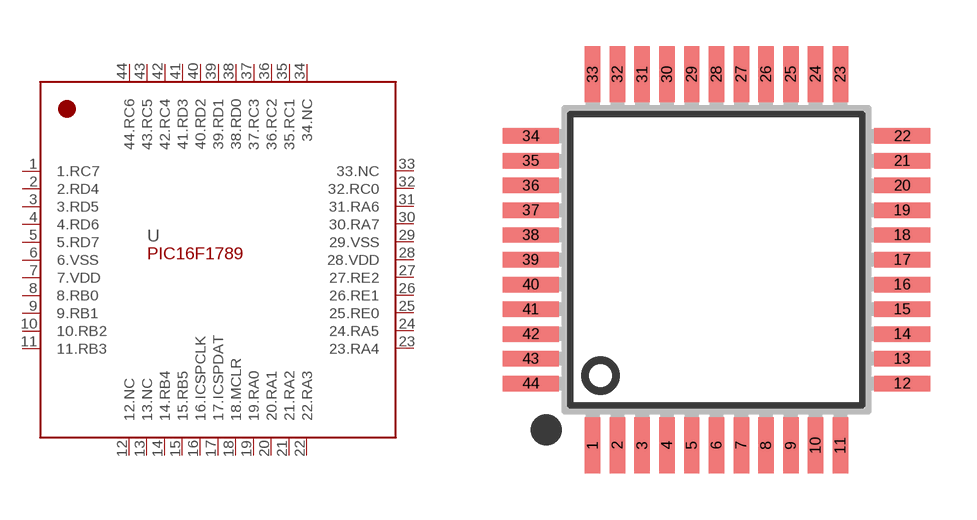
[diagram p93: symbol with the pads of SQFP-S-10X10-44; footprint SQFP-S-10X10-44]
Designator prefix -

## PIC16F1789  [SQFP-S-10X10-44]
1  1.RC7
2  2.RD4
3  3.RD5
4  4.RD6
5  5.RD7
6  6.VSS
7  7.VDD
8  8.RB0
9  9.RB1
10  10.RB2
11  11.RB3
12  12.NC
13  13.NC
14  14.RB4
15  15.RB5
16  16.ICSPCLK
17  17.ICSPDAT
18  18.MCLR
19  19.RA0
20  20.RA1
21  21.RA2
22  22.RA3
23  23.RA4
24  24.RA5
25  25.RE0
26  26.RE1
27  27.RE2
28  28.VDD
29  29.VSS
30  30.RA7
31  31.RA6
32  32.RC0
33  33.NC
34  34.NC
35  35.RC1
36  36.RC2
37  37.RC3
38  38.RD0
39  39.RD1
40  40.RD2
41  41.RD3
42  42.RC4
43  43.RC5
44  44.RC6

## Footprint SQFP-S-10X10-44 (pad centres in mm)
QFP44 shrink quad flat pack, square
smd 0.5 x 1.8: 1 -4,-6; 2 -3.2,-6; 3 -2.4,-6; 4 -1.6,-6; 5 -0.8,-6; 6 0,-6; 7 0.8,-6; 8 1.6,-6; 9 2.4,-6; 10 3.2,-6; 11 4,-6; 23 4,6; 24 3.2,6; 25 2.4,6; 26 1.6,6; 27 0.8,6; 28 0,6; 29 -0.8,6; 30 -1.6,6; 31 -2.4,6; 32 -3.2,6; 33 -4,6
smd 1.8 x 0.5: 12 6,-4; 13 6,-3.2; 14 6,-2.4; 15 6,-1.6; 16 6,-0.8; 17 6,0; 18 6,0.8; 19 6,1.6; 20 6,2.4; 21 6,3.2; 22 6,4; 34 -6,4; 35 -6,3.2; 36 -6,2.4; 37 -6,1.6; 38 -6,0.8; 39 -6,0; 40 -6,-0.8; 41 -6,-1.6; 42 -6,-2.4; 43 -6,-3.2; 44 -6,-4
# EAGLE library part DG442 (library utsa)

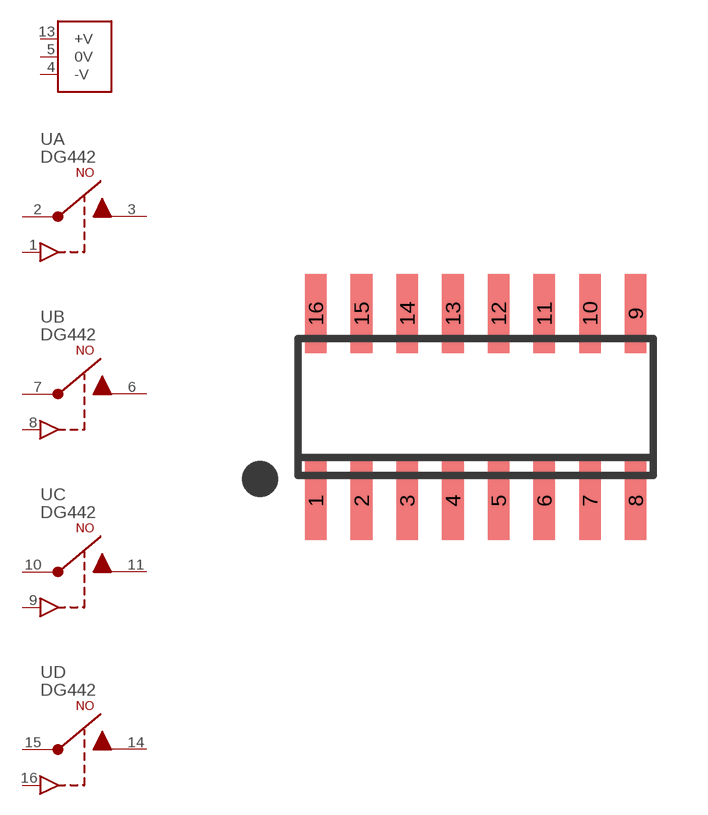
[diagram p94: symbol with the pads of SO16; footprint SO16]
Designator prefix U; gates A=DG442 B=DG442 C=DG442 D=DG442 G$5=PWR-GND-NEG

## DG442  [SO16]
1  A:IN
2  A:A
3  A:B
4  G$5:-V
5  G$5:0V
6  B:B
7  B:A
8  B:IN
9  C:IN
10  C:A
11  C:B
13  G$5:+V
14  D:B
15  D:A
16  D:IN

## Footprint SO16 (pad centres in mm)
SMALL OUTLINE INTEGRATED CIRCUIT body 3.9 mm/JEDEC MS-012AC
smd 0.6 x 2.2: 1 -4.445,-2.6; 2 -3.175,-2.6; 3 -1.905,-2.6; 4 -0.635,-2.6; 5 0.635,-2.6; 6 1.905,-2.6; 7 3.175,-2.6; 8 4.445,-2.6; 9 4.445,2.6; 10 3.175,2.6; 11 1.905,2.6; 12 0.635,2.6; 13 -0.635,2.6; 14 -1.905,2.6; 15 -3.175,2.6; 16 -4.445,2.6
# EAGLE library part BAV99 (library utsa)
Dual high-speed switching diode

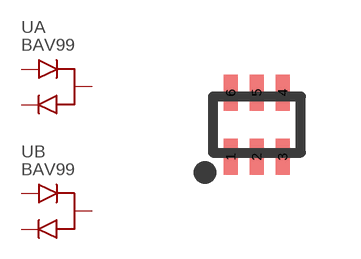
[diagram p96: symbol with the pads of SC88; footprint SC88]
Designator prefix -; gates A=BAV99 B=BAV99

## BAV99"  [SC88]
1  A:A(+)  pas
2  A:BC(-)  pas
3  B:AC(-)BA(+)  pas
4  B:A(+)  pas
5  B:BC(-)  pas
6  A:AC(-)BA(+)  pas

## Footprint SC88 (pad centres in mm)
smd 0.35 x 0.9: 1 -0.65,-0.8; 2 0,-0.8; 3 0.65,-0.8; 4 0.65,0.8; 5 0,0.8; 6 -0.65,0.8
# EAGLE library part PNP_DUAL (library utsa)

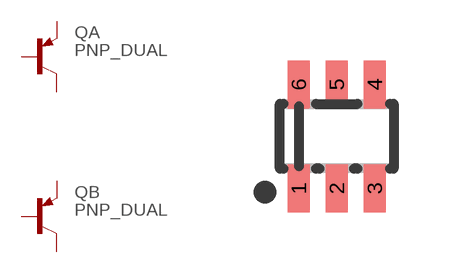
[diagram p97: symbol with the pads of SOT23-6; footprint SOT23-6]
Designator prefix Q; gates A=PNP-1 B=PNP-1

## PNP_DUAL  [SOT23-6]
1  A:C  pas
2  A:B  pas
3  B:B  pas
4  B:C  pas
5  B:E  pas
6  A:E  pas

## Footprint SOT23-6 (pad centres in mm)
smd 0.55 x 1.2: 1 -0.95,-1.3; 2 0,-1.3; 3 0.95,-1.3; 4 0.95,1.3; 5 0,1.3; 6 -0.95,1.3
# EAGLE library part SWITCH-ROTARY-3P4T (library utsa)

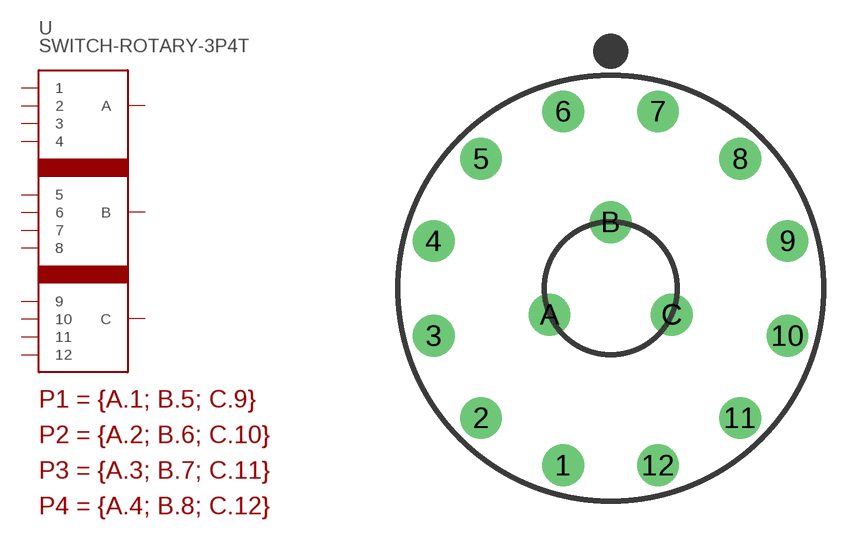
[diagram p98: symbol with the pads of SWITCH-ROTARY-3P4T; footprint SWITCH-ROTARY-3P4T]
Designator prefix -

## SWITCH-ROTARY-3P4T  [SWITCH-ROTARY-3P4T]
1  1
2  2
3  3
4  4
5  5
6  6
7  7
8  8
9  9
10  10
11  11
12  12
A  A
B  B
C  C

## Footprint SWITCH-ROTARY-3P4T (pad centres in mm)
drill 1.6: 1 -2.718,-10.142; 2 -7.425,-7.425; 3 -10.142,-2.718; 4 -10.142,2.718; 5 -7.425,7.425; 6 -2.718,10.142; 7 2.718,10.142; 8 7.425,7.425; 9 10.142,2.718; 10 10.142,-2.718; 11 7.425,-7.425; 12 2.718,-10.142; A -3.5,-1.5; B 0,3.8; C 3.5,-1.5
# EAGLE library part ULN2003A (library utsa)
DRIVER ARRAY

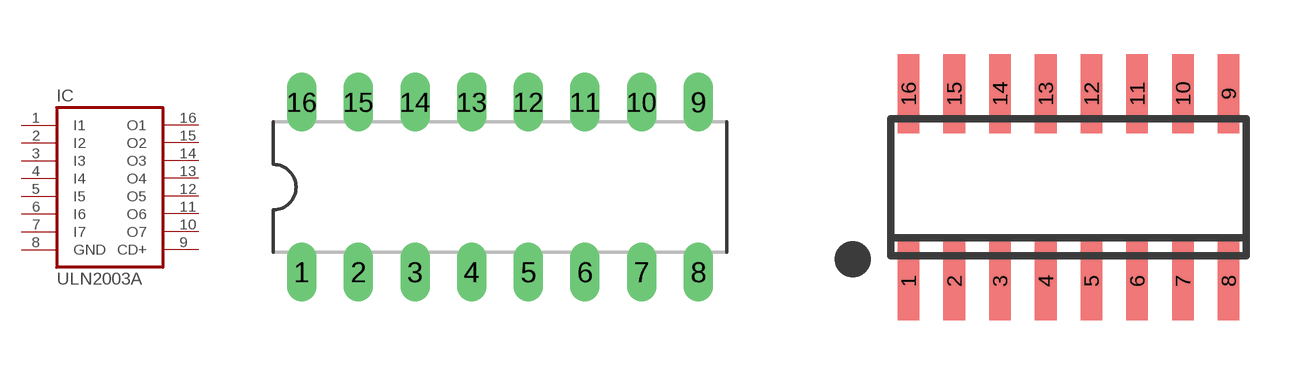
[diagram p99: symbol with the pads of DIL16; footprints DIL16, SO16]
Designator prefix IC

## ULN2003AN  [DIL16]
1  I1  in
2  I2  in
3  I3  in
4  I4  in
5  I5  in
6  I6  in
7  I7  in
8  GND  pwr
9  CD+  pas
10  O7  oc
11  O6  oc
12  O5  oc
13  O4  oc
14  O3  oc
15  O2  oc
16  O1  oc

## ULN2003AD  [SO16]
Pads as for DIL16

## Footprint DIL16 (pad centres in mm)
Dual In Line Package
drill 0.813 long: 1 -8.89,-3.81; 2 -6.35,-3.81; 3 -3.81,-3.81; 4 -1.27,-3.81; 5 1.27,-3.81; 6 3.81,-3.81; 7 6.35,-3.81; 8 8.89,-3.81; 9 8.89,3.81; 10 6.35,3.81; 11 3.81,3.81; 12 1.27,3.81; 13 -1.27,3.81; 14 -3.81,3.81; 15 -6.35,3.81; 16 -8.89,3.81

## Footprint SO16 (pad centres in mm)
SMALL OUTLINE INTEGRATED CIRCUIT body 3.9 mm/JEDEC MS-012AC
smd 0.6 x 2.2: 1 -4.445,-2.6; 2 -3.175,-2.6; 3 -1.905,-2.6; 4 -0.635,-2.6; 5 0.635,-2.6; 6 1.905,-2.6; 7 3.175,-2.6; 8 4.445,-2.6; 9 4.445,2.6; 10 3.175,2.6; 11 1.905,2.6; 12 0.635,2.6; 13 -0.635,2.6; 14 -1.905,2.6; 15 -3.175,2.6; 16 -4.445,2.6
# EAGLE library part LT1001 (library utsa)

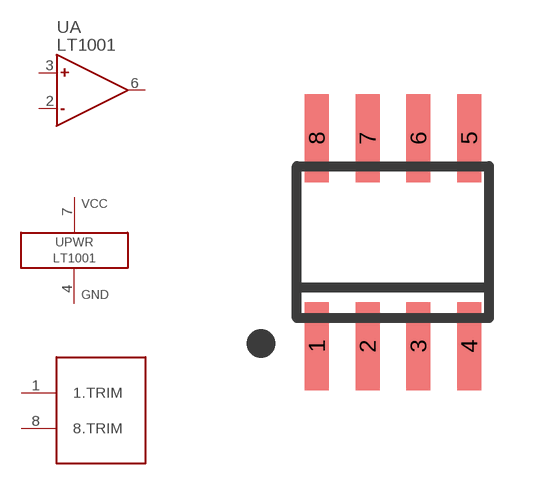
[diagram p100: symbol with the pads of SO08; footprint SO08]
Designator prefix U; gates A=OPAMP-1 PWR=PWRN-1 TRIM=LT1001

## LT1001  [SO08]
1  TRIM:1.TRIM
2  A:-
3  A:+
4  PWR:GND  pwr
6  A:OUT
7  PWR:VCC  pwr
8  TRIM:8.TRIM

## Footprint SO08 (pad centres in mm)
SMALL OUTLINE INTEGRATED CIRCUIT body 3.9 mm/JEDEC MS-012AA
smd 0.6 x 2.2: 1 -1.905,-2.6; 2 -0.635,-2.6; 3 0.635,-2.6; 4 1.905,-2.6; 5 1.905,2.6; 6 0.635,2.6; 7 -0.635,2.6; 8 -1.905,2.6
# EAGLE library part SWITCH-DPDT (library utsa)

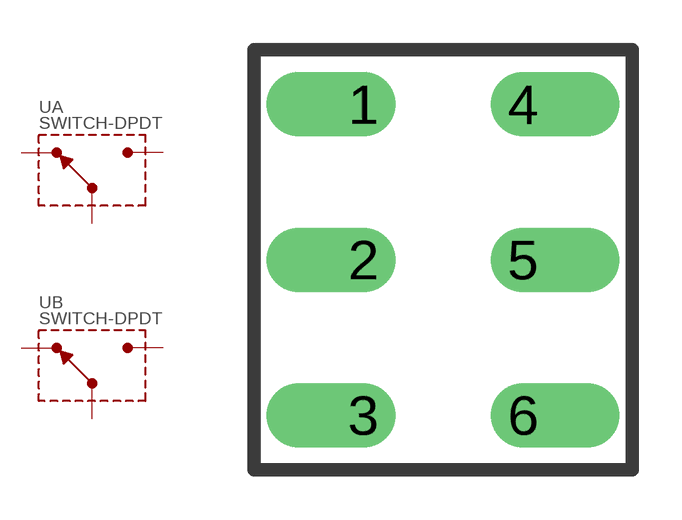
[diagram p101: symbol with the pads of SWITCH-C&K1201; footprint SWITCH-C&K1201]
Designator prefix -; gates A=SWITCH-SPST-2 B=SWITCH-SPST-2

## SWITCH-DPDT  [SWITCH-C&K1201]
1  A:1
2  A:2
3  A:3
4  B:1
5  B:2
6  B:3

## Footprint SWITCH-C&K1201 (pad centres in mm)
drill 1.3 offset: 1 0,4.699; 2 0,0; 3 0,-4.699; 4 4.826,4.699; 5 4.826,0; 6 4.826,-4.699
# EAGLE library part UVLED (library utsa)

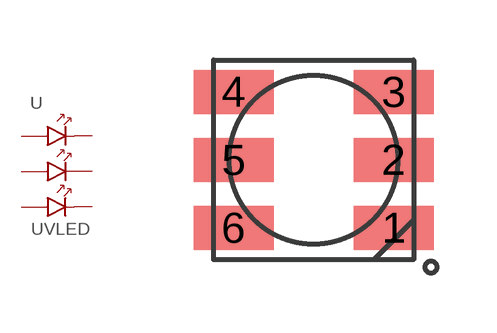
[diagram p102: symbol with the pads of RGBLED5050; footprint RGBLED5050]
Designator prefix -

## UVLED5050  [RGBLED5050]
1  A.C
2  B.C
3  C.C
4  C.A
5  B.A
6  A.A

## Footprint RGBLED5050 (pad centres in mm)
smd 2 x 1.1: 1 2,-1.7; 2 2,0; 3 2,1.7; 4 -2,1.7; 5 -2,0; 6 -2,-1.7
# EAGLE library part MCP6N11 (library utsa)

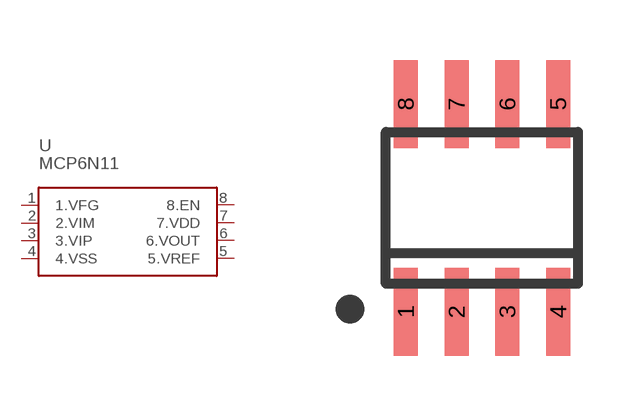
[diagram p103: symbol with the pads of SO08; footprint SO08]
Designator prefix -

## MCP6N11  [SO08]
1  1.VFG
2  2.VIM
3  3.VIP
4  4.VSS
5  5.VREF
6  6.VOUT
7  7.VDD
8  8.EN

## Footprint SO08 (pad centres in mm)
SMALL OUTLINE INTEGRATED CIRCUIT body 3.9 mm/JEDEC MS-012AA
smd 0.6 x 2.2: 1 -1.905,-2.6; 2 -0.635,-2.6; 3 0.635,-2.6; 4 1.905,-2.6; 5 1.905,2.6; 6 0.635,2.6; 7 -0.635,2.6; 8 -1.905,2.6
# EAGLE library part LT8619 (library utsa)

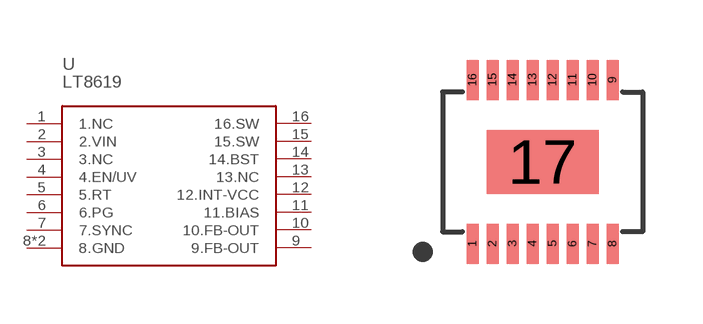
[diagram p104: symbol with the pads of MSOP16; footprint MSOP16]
Designator prefix -

## LT8619  [MSOP16]
1  1.NC
2  2.VIN
3  3.NC
4  4.EN/UV
5  5.RT
6  6.PG
7  7.SYNC
8  8.GND
9  9.FB-OUT
10  10.FB-OUT
11  11.BIAS
12  12.INT-VCC
13  13.NC
14  14.BST
15  15.SW
16  16.SW
17  8.GND

## Footprint MSOP16 (pad centres in mm)
smd 0.3 x 1: 1 -1.75,-2.05; 2 -1.25,-2.05; 3 -0.75,-2.05; 4 -0.25,-2.05; 5 0.25,-2.05; 6 0.75,-2.05; 7 1.25,-2.05; 8 1.75,-2.05; 9 1.75,2.05; 10 1.25,2.05; 11 0.75,2.05; 12 0.25,2.05; 13 -0.25,2.05; 14 -0.75,2.05; 15 -1.25,2.05; 16 -1.75,2.05
smd 2.8 x 1.6: 17 0,0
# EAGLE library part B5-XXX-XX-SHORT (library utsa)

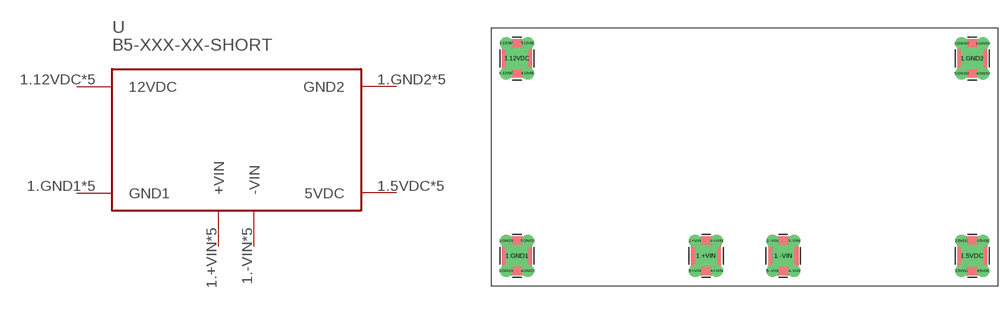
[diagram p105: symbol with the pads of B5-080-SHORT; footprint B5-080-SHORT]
Designator prefix -

## B5-XXX-XX-SHORT  [B5-080-SHORT]
1.5VDC  5VDC
1.12VDC  12VDC
1.+VIN  +VIN
1.-VIN  -VIN
1.GND1  GND1
1.GND2  GND2
2.5VDC  5VDC
2.12VDC  12VDC
2.+VIN  +VIN
2.-VIN  -VIN
2.GND1  GND1
2.GND2  GND2
3.5VDC  5VDC
3.12VDC  12VDC
3.+VIN  +VIN
3.-VIN  -VIN
3.GND1  GND1
3.GND2  GND2
4.5VDC  5VDC
4.12VDC  12VDC
4.+VIN  +VIN
4.-VIN  -VIN
4.GND1  GND1
4.GND2  GND2
5.5VDC  5VDC
5.12VDC  12VDC
5.+VIN  +VIN
5.-VIN  -VIN
5.GND1  GND1
5.GND2  GND2

## Footprint B5-080-SHORT (pad centres in mm)
drill 4 square: 1.5VDC 112,7; 1.12VDC 6,53; 1.+VIN 50,7; 1.-VIN 68,7; 1.GND1 6,7; 1.GND2 112,53
drill 1.9: 2.5VDC 109.5,10.5; 2.12VDC 3.5,56.5; 2.+VIN 47.5,10.5; 2.-VIN 65.5,10.5; 2.GND1 3.5,10.5; 2.GND2 109.5,56.5; 3.5VDC 114.5,10.5; 3.12VDC 8.5,56.5; 3.+VIN 52.5,10.5; 3.-VIN 70.5,10.5; 3.GND1 8.5,10.5; 3.GND2 114.5,56.5; 4.5VDC 114.5,3.5; 4.12VDC 8.5,49.5; 4.+VIN 52.5,3.5; 4.-VIN 70.5,3.5; 4.GND1 8.5,3.5; 4.GND2 114.5,49.5; 5.5VDC 109.5,3.5; 5.12VDC 3.5,49.5; 5.+VIN 47.5,3.5; 5.-VIN 65.5,3.5; 5.GND1 3.5,3.5; 5.GND2 109.5,49.5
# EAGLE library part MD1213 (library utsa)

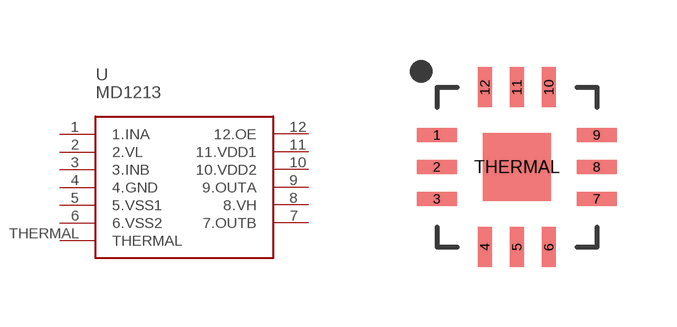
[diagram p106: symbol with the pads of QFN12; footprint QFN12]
Designator prefix -

## MD1213  [QFN12]
1  1.INA
2  2.VL
3  3.INB
4  4.GND
5  5.VSS1
6  6.VSS2
7  7.OUTB
8  8.VH
9  9.OUTA
10  10.VDD2
11  11.VDD1
12  12.OE
THERMAL  THERMAL

## Footprint QFN12 (pad centres in mm)
smd 1 x 0.35: 1 -2,0.8; 2 -2,0; 3 -2,-0.8; 7 2,-0.8; 8 2,0; 9 2,0.8
smd 0.35 x 1: 4 -0.8,-2; 5 0,-2; 6 0.8,-2; 10 0.8,2; 11 0,2; 12 -0.8,2
smd 1.7 x 1.7: THERMAL 0,0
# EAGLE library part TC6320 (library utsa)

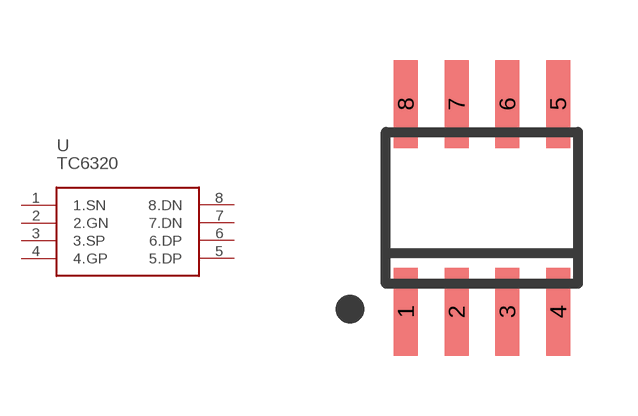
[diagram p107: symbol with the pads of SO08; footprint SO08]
Designator prefix -

## TC6320  [SO08]
1  1.SN
2  2.GN
3  3.SP
4  4.GP
5  5.DP
6  6.DP
7  7.DN
8  8.DN

## Footprint SO08 (pad centres in mm)
SMALL OUTLINE INTEGRATED CIRCUIT body 3.9 mm/JEDEC MS-012AA
smd 0.6 x 2.2: 1 -1.905,-2.6; 2 -0.635,-2.6; 3 0.635,-2.6; 4 1.905,-2.6; 5 1.905,2.6; 6 0.635,2.6; 7 -0.635,2.6; 8 -1.905,2.6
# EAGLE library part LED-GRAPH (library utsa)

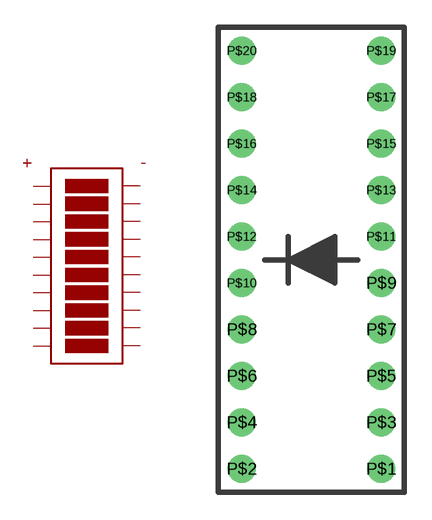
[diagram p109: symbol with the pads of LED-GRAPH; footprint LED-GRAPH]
Designator prefix -

## LED-GRAPH  [LED-GRAPH]
P$1  P$1
P$2  P$2
P$3  P$3
P$4  P$4
P$5  P$5
P$6  P$6
P$7  P$7
P$8  P$8
P$9  P$9
P$10  P$10
P$11  P$11
P$12  P$12
P$13  P$13
P$14  P$14
P$15  P$15
P$16  P$16
P$17  P$17
P$18  P$18
P$19  P$19
P$20  P$20

## Footprint LED-GRAPH (pad centres in mm)
drill 1: P$1 3.81,-11.43; P$2 -3.81,-11.43; P$3 3.81,-8.89; P$4 -3.81,-8.89; P$5 3.81,-6.35; P$6 -3.81,-6.35; P$7 3.81,-3.81; P$8 -3.81,-3.81; P$9 3.81,-1.27; P$10 -3.81,-1.27; P$11 3.81,1.27; P$12 -3.81,1.27; P$13 3.81,3.81; P$14 -3.81,3.81; P$15 3.81,6.35; P$16 -3.81,6.35; P$17 3.81,8.89; P$18 -3.81,8.89; P$19 3.81,11.43; P$20 -3.81,11.43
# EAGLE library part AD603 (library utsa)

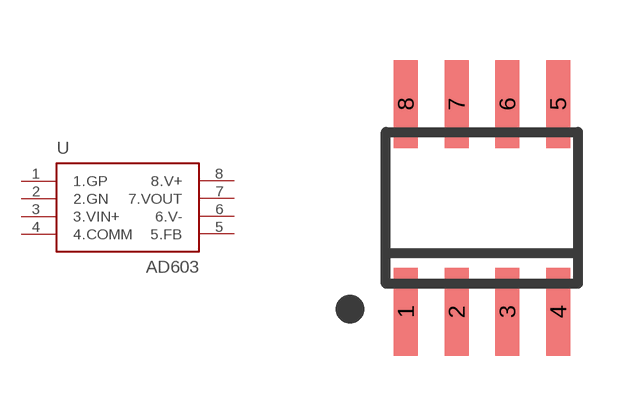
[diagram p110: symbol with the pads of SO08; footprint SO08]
Designator prefix -

## AD603AR  [SO08]
1  1.GP
2  2.GN
3  3.VIN+
4  4.COMM
5  5.FB
6  6.V-
7  7.VOUT
8  8.V+

## Footprint SO08 (pad centres in mm)
SMALL OUTLINE INTEGRATED CIRCUIT body 3.9 mm/JEDEC MS-012AA
smd 0.6 x 2.2: 1 -1.905,-2.6; 2 -0.635,-2.6; 3 0.635,-2.6; 4 1.905,-2.6; 5 1.905,2.6; 6 0.635,2.6; 7 -0.635,2.6; 8 -1.905,2.6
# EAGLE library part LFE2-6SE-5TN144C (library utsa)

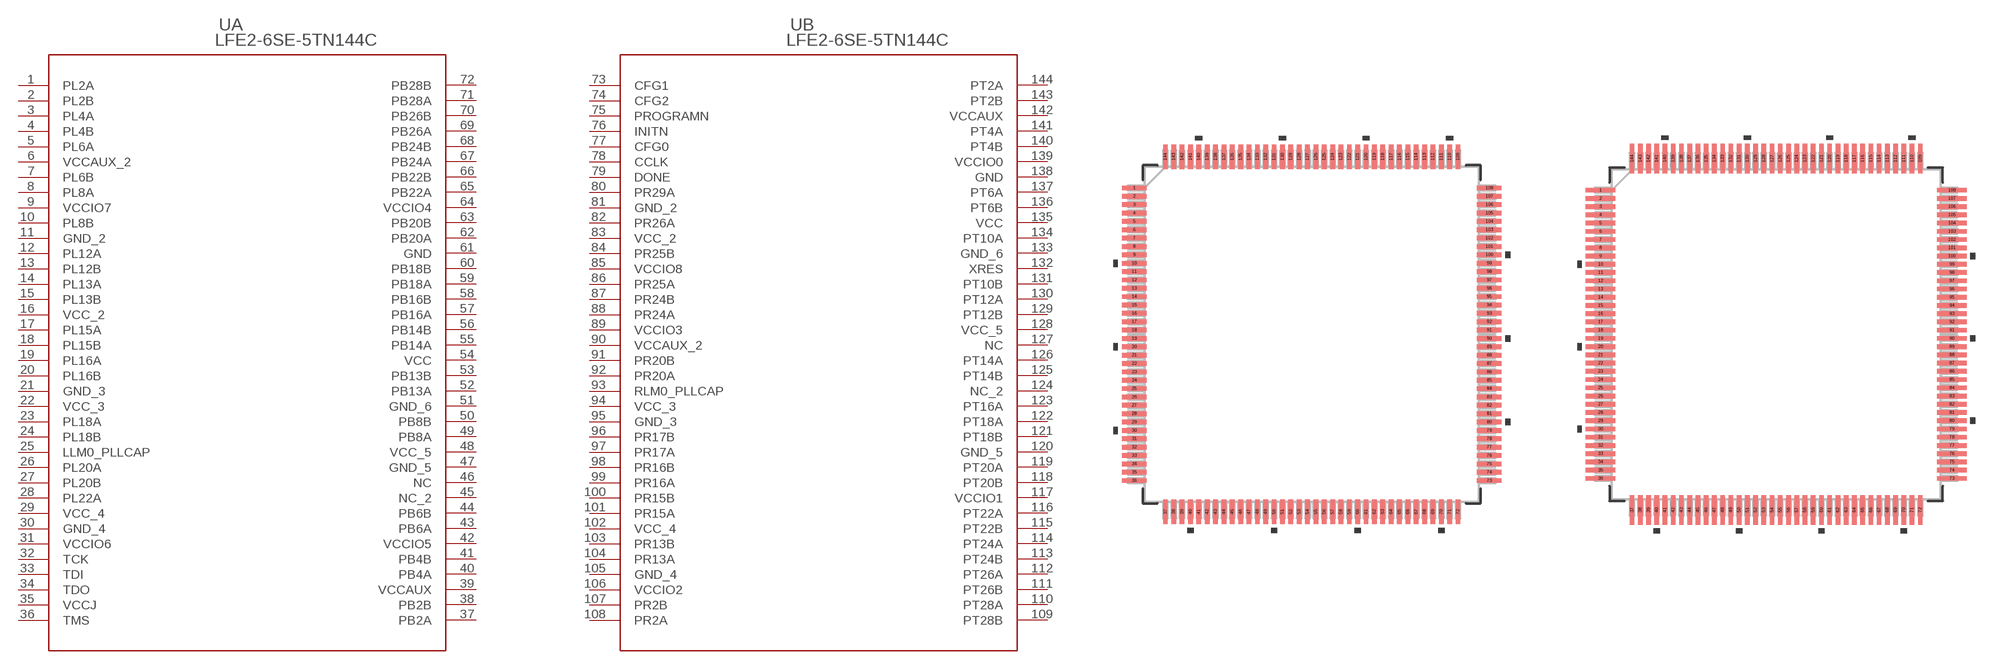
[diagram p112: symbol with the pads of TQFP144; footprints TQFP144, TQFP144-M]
Designator prefix U; gates A=LFE2-6SE-5TN144C_A B=LFE2-6SE-5TN144C_B

## LFE2-6SE-5TN144C (MANUFACTURER_PART_NUMBER: LFE26SE5TN144C; VENDOR: Lattice)  [TQFP144]
1  A:PL2A  pas
2  A:PL2B  pas
3  A:PL4A  pas
4  A:PL4B  pas
5  A:PL6A  pas
6  A:VCCAUX_2  pwr
7  A:PL6B  pas
8  A:PL8A  pas
9  A:VCCIO7  pwr
10  A:PL8B  pas
11  A:GND_2  pwr
12  A:PL12A  pas
13  A:PL12B  pas
14  A:PL13A  pas
15  A:PL13B  pas
16  A:VCC_2  pwr
17  A:PL15A  pas
18  A:PL15B  pas
19  A:PL16A  pas
20  A:PL16B  pas
21  A:GND_3  pwr
22  A:VCC_3  pwr
23  A:PL18A  pas
24  A:PL18B  pas
25  A:LLM0_PLLCAP  pas
26  A:PL20A  pas
27  A:PL20B  pas
28  A:PL22A  pas
29  A:VCC_4  pwr
30  A:GND_4  pwr
31  A:VCCIO6  pwr
32  A:TCK  pas
33  A:TDI  pas
34  A:TDO  pas
35  A:VCCJ  pwr
36  A:TMS  pas
37  A:PB2A  pas
38  A:PB2B  pas
39  A:VCCAUX  pwr
40  A:PB4A  pas
41  A:PB4B  pas
42  A:VCCIO5  pwr
43  A:PB6A  pas
44  A:PB6B  pas
45  A:NC_2  nc
46  A:NC  nc
47  A:GND_5  pwr
48  A:VCC_5  pwr
49  A:PB8A  pas
50  A:PB8B  pas
51  A:GND_6  pwr
52  A:PB13A  pas
53  A:PB13B  pas
54  A:VCC  pwr
55  A:PB14A  pas
56  A:PB14B  pas
57  A:PB16A  pas
58  A:PB16B  pas
59  A:PB18A  pas
60  A:PB18B  pas
61  A:GND  pwr
62  A:PB20A  pas
63  A:PB20B  pas
64  A:VCCIO4  pwr
65  A:PB22A  pas
66  A:PB22B  pas
67  A:PB24A  pas
68  A:PB24B  pas
69  A:PB26A  pas
70  A:PB26B  pas
71  A:PB28A  pas
72  A:PB28B  pas
73  B:CFG1  pas
74  B:CFG2  pas
75  B:PROGRAMN  pas
76  B:INITN  pas
77  B:CFG0  pas
78  B:CCLK  pas
79  B:DONE  pas
80  B:PR29A  pas
81  B:GND_2  pwr
82  B:PR26A  pas
83  B:VCC_2  pwr
84  B:PR25B  pas
85  B:VCCIO8  pwr
86  B:PR25A  pas
87  B:PR24B  pas
88  B:PR24A  pas
89  B:VCCIO3  pwr
90  B:VCCAUX_2  pwr
91  B:PR20B  pas
92  B:PR20A  pas
93  B:RLM0_PLLCAP  pas
94  B:VCC_3  pwr
95  B:GND_3  pwr
96  B:PR17B  pas
97  B:PR17A  pas
98  B:PR16B  pas
99  B:PR16A  pas
100  B:PR15B  pas
101  B:PR15A  pas
102  B:VCC_4  pwr
103  B:PR13B  pas
104  B:PR13A  pas
105  B:GND_4  pwr
106  B:VCCIO2  pwr
107  B:PR2B  pas
108  B:PR2A  pas
109  B:PT28B  pas
110  B:PT28A  pas
111  B:PT26B  pas
112  B:PT26A  pas
113  B:PT24B  pas
114  B:PT24A  pas
115  B:PT22B  pas
116  B:PT22A  pas
117  B:VCCIO1  pwr
118  B:PT20B  pas
119  B:PT20A  pas
120  B:GND_5  pwr
121  B:PT18B  pas
122  B:PT18A  pas
123  B:PT16A  pas
124  B:NC_2  nc
125  B:PT14B  pas
126  B:PT14A  pas
127  B:NC  nc
128  B:VCC_5  pwr
129  B:PT12B  pas
130  B:PT12A  pas
131  B:PT10B  pas
132  B:XRES  pas
133  B:GND_6  pwr
134  B:PT10A  pas
135  B:VCC  pwr
136  B:PT6B  pas
137  B:PT6A  pas
138  B:GND  pwr
139  B:VCCIO0  pwr
140  B:PT4B  pas
141  B:PT4A  pas
142  B:VCCAUX  pwr
143  B:PT2B  pas
144  B:PT2A  pas

## LFE2-6SE-5TN144CTQFP144-M (MANUFACTURER_PART_NUMBER: LFE26SE5TN144C; VENDOR: Lattice)  [TQFP144-M]
Pads as for TQFP144

## LFE2-6SE-5TN144CTQFP144-L (MANUFACTURER_PART_NUMBER: LFE26SE5TN144C; VENDOR: Lattice)  [TQFP144-L]
Pads as for TQFP144

## Footprint TQFP144 (pad centres in mm)
smd 1.473 x 0.279: 1 -10.617,8.75; 2 -10.617,8.25; 3 -10.617,7.75; 4 -10.617,7.25; 5 -10.617,6.75; 6 -10.617,6.25; 7 -10.617,5.75; 8 -10.617,5.25; 9 -10.617,4.75; 10 -10.617,4.25; 11 -10.617,3.75; 12 -10.617,3.25; 13 -10.617,2.75; 14 -10.617,2.25; 15 -10.617,1.75; 16 -10.617,1.25; 17 -10.617,0.75; 18 -10.617,0.25; 19 -10.617,-0.25; 20 -10.617,-0.75; 21 -10.617,-1.25; 22 -10.617,-1.75; 23 -10.617,-2.25; 24 -10.617,-2.75; 25 -10.617,-3.25; 26 -10.617,-3.75; 27 -10.617,-4.25; 28 -10.617,-4.75; 29 -10.617,-5.25; 30 -10.617,-5.75; 31 -10.617,-6.25; 32 -10.617,-6.75; 33 -10.617,-7.25; 34 -10.617,-7.75; 35 -10.617,-8.25; 36 -10.617,-8.75; 73 10.617,-8.75; 74 10.617,-8.25; 75 10.617,-7.75; 76 10.617,-7.25; 77 10.617,-6.75; 78 10.617,-6.25; 79 10.617,-5.75; 80 10.617,-5.25; 81 10.617,-4.75; 82 10.617,-4.25; 83 10.617,-3.75; 84 10.617,-3.25; 85 10.617,-2.75; 86 10.617,-2.25; 87 10.617,-1.75; 88 10.617,-1.25; 89 10.617,-0.75; 90 10.617,-0.25; 91 10.617,0.25; 92 10.617,0.75; 93 10.617,1.25; 94 10.617,1.75; 95 10.617,2.25; 96 10.617,2.75; 97 10.617,3.25; 98 10.617,3.75; 99 10.617,4.25; 100 10.617,4.75; 101 10.617,5.25; 102 10.617,5.75; 103 10.617,6.25; 104 10.617,6.75; 105 10.617,7.25; 106 10.617,7.75; 107 10.617,8.25; 108 10.617,8.75
smd 0.279 x 1.473: 37 -8.75,-10.617; 38 -8.25,-10.617; 39 -7.75,-10.617; 40 -7.25,-10.617; 41 -6.75,-10.617; 42 -6.25,-10.617; 43 -5.75,-10.617; 44 -5.25,-10.617; 45 -4.75,-10.617; 46 -4.25,-10.617; 47 -3.75,-10.617; 48 -3.25,-10.617; 49 -2.75,-10.617; 50 -2.25,-10.617; 51 -1.75,-10.617; 52 -1.25,-10.617; 53 -0.75,-10.617; 54 -0.25,-10.617; 55 0.25,-10.617; 56 0.75,-10.617; 57 1.25,-10.617; 58 1.75,-10.617; 59 2.25,-10.617; 60 2.75,-10.617; 61 3.25,-10.617; 62 3.75,-10.617; 63 4.25,-10.617; 64 4.75,-10.617; 65 5.25,-10.617; 66 5.75,-10.617; 67 6.25,-10.617; 68 6.75,-10.617; 69 7.25,-10.617; 70 7.75,-10.617; 71 8.25,-10.617; 72 8.75,-10.617; 109 8.75,10.617; 110 8.25,10.617; 111 7.75,10.617; 112 7.25,10.617; 113 6.75,10.617; 114 6.25,10.617; 115 5.75,10.617; 116 5.25,10.617; 117 4.75,10.617; 118 4.25,10.617; 119 3.75,10.617; 120 3.25,10.617; 121 2.75,10.617; 122 2.25,10.617; 123 1.75,10.617; 124 1.25,10.617; 125 0.75,10.617; 126 0.25,10.617; 127 -0.25,10.617; 128 -0.75,10.617; 129 -1.25,10.617; 130 -1.75,10.617; 131 -2.25,10.617; 132 -2.75,10.617; 133 -3.25,10.617; 134 -3.75,10.617; 135 -4.25,10.617; 136 -4.75,10.617; 137 -5.25,10.617; 138 -5.75,10.617; 139 -6.25,10.617; 140 -6.75,10.617; 141 -7.25,10.617; 142 -7.75,10.617; 143 -8.25,10.617; 144 -8.75,10.617

## Footprint TQFP144-M (pad centres in mm)
smd 1.778 x 0.279: 1 -10.668,8.75; 2 -10.668,8.25; 3 -10.668,7.75; 4 -10.668,7.25; 5 -10.668,6.75; 6 -10.668,6.25; 7 -10.668,5.75; 8 -10.668,5.25; 9 -10.668,4.75; 10 -10.668,4.25; 11 -10.668,3.75; 12 -10.668,3.25; 13 -10.668,2.75; 14 -10.668,2.25; 15 -10.668,1.75; 16 -10.668,1.25; 17 -10.668,0.75; 18 -10.668,0.25; 19 -10.668,-0.25; 20 -10.668,-0.75; 21 -10.668,-1.25; 22 -10.668,-1.75; 23 -10.668,-2.25; 24 -10.668,-2.75; 25 -10.668,-3.25; 26 -10.668,-3.75; 27 -10.668,-4.25; 28 -10.668,-4.75; 29 -10.668,-5.25; 30 -10.668,-5.75; 31 -10.668,-6.25; 32 -10.668,-6.75; 33 -10.668,-7.25; 34 -10.668,-7.75; 35 -10.668,-8.25; 36 -10.668,-8.75; 73 10.668,-8.75; 74 10.668,-8.25; 75 10.668,-7.75; 76 10.668,-7.25; 77 10.668,-6.75; 78 10.668,-6.25; 79 10.668,-5.75; 80 10.668,-5.25; 81 10.668,-4.75; 82 10.668,-4.25; 83 10.668,-3.75; 84 10.668,-3.25; 85 10.668,-2.75; 86 10.668,-2.25; 87 10.668,-1.75; 88 10.668,-1.25; 89 10.668,-0.75; 90 10.668,-0.25; 91 10.668,0.25; 92 10.668,0.75; 93 10.668,1.25; 94 10.668,1.75; 95 10.668,2.25; 96 10.668,2.75; 97 10.668,3.25; 98 10.668,3.75; 99 10.668,4.25; 100 10.668,4.75; 101 10.668,5.25; 102 10.668,5.75; 103 10.668,6.25; 104 10.668,6.75; 105 10.668,7.25; 106 10.668,7.75; 107 10.668,8.25; 108 10.668,8.75
smd 0.279 x 1.778: 37 -8.75,-10.668; 38 -8.25,-10.668; 39 -7.75,-10.668; 40 -7.25,-10.668; 41 -6.75,-10.668; 42 -6.25,-10.668; 43 -5.75,-10.668; 44 -5.25,-10.668; 45 -4.75,-10.668; 46 -4.25,-10.668; 47 -3.75,-10.668; 48 -3.25,-10.668; 49 -2.75,-10.668; 50 -2.25,-10.668; 51 -1.75,-10.668; 52 -1.25,-10.668; 53 -0.75,-10.668; 54 -0.25,-10.668; 55 0.25,-10.668; 56 0.75,-10.668; 57 1.25,-10.668; 58 1.75,-10.668; 59 2.25,-10.668; 60 2.75,-10.668; 61 3.25,-10.668; 62 3.75,-10.668; 63 4.25,-10.668; 64 4.75,-10.668; 65 5.25,-10.668; 66 5.75,-10.668; 67 6.25,-10.668; 68 6.75,-10.668; 69 7.25,-10.668; 70 7.75,-10.668; 71 8.25,-10.668; 72 8.75,-10.668; 109 8.75,10.668; 110 8.25,10.668; 111 7.75,10.668; 112 7.25,10.668; 113 6.75,10.668; 114 6.25,10.668; 115 5.75,10.668; 116 5.25,10.668; 117 4.75,10.668; 118 4.25,10.668; 119 3.75,10.668; 120 3.25,10.668; 121 2.75,10.668; 122 2.25,10.668; 123 1.75,10.668; 124 1.25,10.668; 125 0.75,10.668; 126 0.25,10.668; 127 -0.25,10.668; 128 -0.75,10.668; 129 -1.25,10.668; 130 -1.75,10.668; 131 -2.25,10.668; 132 -2.75,10.668; 133 -3.25,10.668; 134 -3.75,10.668; 135 -4.25,10.668; 136 -4.75,10.668; 137 -5.25,10.668; 138 -5.75,10.668; 139 -6.25,10.668; 140 -6.75,10.668; 141 -7.25,10.668; 142 -7.75,10.668; 143 -8.25,10.668; 144 -8.75,10.668

## Footprint TQFP144-L (pad centres in mm)
smd 1.168 x 0.279: 1 -10.566,8.75; 2 -10.566,8.25; 3 -10.566,7.75; 4 -10.566,7.25; 5 -10.566,6.75; 6 -10.566,6.25; 7 -10.566,5.75; 8 -10.566,5.25; 9 -10.566,4.75; 10 -10.566,4.25; 11 -10.566,3.75; 12 -10.566,3.25; 13 -10.566,2.75; 14 -10.566,2.25; 15 -10.566,1.75; 16 -10.566,1.25; 17 -10.566,0.75; 18 -10.566,0.25; 19 -10.566,-0.25; 20 -10.566,-0.75; 21 -10.566,-1.25; 22 -10.566,-1.75; 23 -10.566,-2.25; 24 -10.566,-2.75; 25 -10.566,-3.25; 26 -10.566,-3.75; 27 -10.566,-4.25; 28 -10.566,-4.75; 29 -10.566,-5.25; 30 -10.566,-5.75; 31 -10.566,-6.25; 32 -10.566,-6.75; 33 -10.566,-7.25; 34 -10.566,-7.75; 35 -10.566,-8.25; 36 -10.566,-8.75; 73 10.566,-8.75; 74 10.566,-8.25; 75 10.566,-7.75; 76 10.566,-7.25; 77 10.566,-6.75; 78 10.566,-6.25; 79 10.566,-5.75; 80 10.566,-5.25; 81 10.566,-4.75; 82 10.566,-4.25; 83 10.566,-3.75; 84 10.566,-3.25; 85 10.566,-2.75; 86 10.566,-2.25; 87 10.566,-1.75; 88 10.566,-1.25; 89 10.566,-0.75; 90 10.566,-0.25; 91 10.566,0.25; 92 10.566,0.75; 93 10.566,1.25; 94 10.566,1.75; 95 10.566,2.25; 96 10.566,2.75; 97 10.566,3.25; 98 10.566,3.75; 99 10.566,4.25; 100 10.566,4.75; 101 10.566,5.25; 102 10.566,5.75; 103 10.566,6.25; 104 10.566,6.75; 105 10.566,7.25; 106 10.566,7.75; 107 10.566,8.25; 108 10.566,8.75
smd 0.279 x 1.168: 37 -8.75,-10.566; 38 -8.25,-10.566; 39 -7.75,-10.566; 40 -7.25,-10.566; 41 -6.75,-10.566; 42 -6.25,-10.566; 43 -5.75,-10.566; 44 -5.25,-10.566; 45 -4.75,-10.566; 46 -4.25,-10.566; 47 -3.75,-10.566; 48 -3.25,-10.566; 49 -2.75,-10.566; 50 -2.25,-10.566; 51 -1.75,-10.566; 52 -1.25,-10.566; 53 -0.75,-10.566; 54 -0.25,-10.566; 55 0.25,-10.566; 56 0.75,-10.566; 57 1.25,-10.566; 58 1.75,-10.566; 59 2.25,-10.566; 60 2.75,-10.566; 61 3.25,-10.566; 62 3.75,-10.566; 63 4.25,-10.566; 64 4.75,-10.566; 65 5.25,-10.566; 66 5.75,-10.566; 67 6.25,-10.566; 68 6.75,-10.566; 69 7.25,-10.566; 70 7.75,-10.566; 71 8.25,-10.566; 72 8.75,-10.566; 109 8.75,10.566; 110 8.25,10.566; 111 7.75,10.566; 112 7.25,10.566; 113 6.75,10.566; 114 6.25,10.566; 115 5.75,10.566; 116 5.25,10.566; 117 4.75,10.566; 118 4.25,10.566; 119 3.75,10.566; 120 3.25,10.566; 121 2.75,10.566; 122 2.25,10.566; 123 1.75,10.566; 124 1.25,10.566; 125 0.75,10.566; 126 0.25,10.566; 127 -0.25,10.566; 128 -0.75,10.566; 129 -1.25,10.566; 130 -1.75,10.566; 131 -2.25,10.566; 132 -2.75,10.566; 133 -3.25,10.566; 134 -3.75,10.566; 135 -4.25,10.566; 136 -4.75,10.566; 137 -5.25,10.566; 138 -5.75,10.566; 139 -6.25,10.566; 140 -6.75,10.566; 141 -7.25,10.566; 142 -7.75,10.566; 143 -8.25,10.566; 144 -8.75,10.566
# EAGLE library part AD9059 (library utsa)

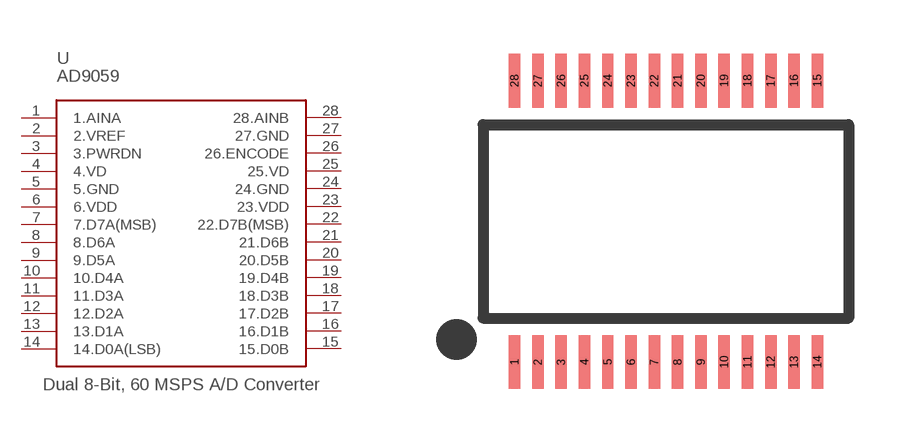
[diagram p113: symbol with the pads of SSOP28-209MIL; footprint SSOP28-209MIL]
Designator prefix -

## AD9059  [SSOP28-209MIL]
1  1.AINA
2  2.VREF
3  3.PWRDN
4  4.VD
5  5.GND
6  6.VDD
7  7.D7A(MSB)
8  8.D6A
9  9.D5A
10  10.D4A
11  11.D3A
12  12.D2A
13  13.D1A
14  14.D0A(LSB)
15  15.D0B
16  16.D1B
17  17.D2B
18  18.D3B
19  19.D4B
20  20.D5B
21  21.D6B
22  22.D7B(MSB)
23  23.VDD
24  24.GND
25  25.VD
26  26.ENCODE
27  27.GND
28  28.AINB

## Footprint SSOP28-209MIL (pad centres in mm)
smd 0.32 x 1.5: 1 -4.225,-3.925; 2 -3.575,-3.925; 3 -2.925,-3.925; 4 -2.275,-3.925; 5 -1.625,-3.925; 6 -0.975,-3.925; 7 -0.325,-3.925; 8 0.325,-3.925; 9 0.975,-3.925; 10 1.625,-3.925; 11 2.275,-3.925; 12 2.925,-3.925; 13 3.575,-3.925; 14 4.225,-3.925; 15 4.225,3.925; 16 3.575,3.925; 17 2.925,3.925; 18 2.275,3.925; 19 1.625,3.925; 20 0.975,3.925; 21 0.325,3.925; 22 -0.325,3.925; 23 -0.975,3.925; 24 -1.625,3.925; 25 -2.275,3.925; 26 -2.925,3.925; 27 -3.575,3.925; 28 -4.225,3.925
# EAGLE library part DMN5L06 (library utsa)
DUAL N-CHANNEL ENHANCEMENT MODE FIELD EFFECT TRANSISTOR

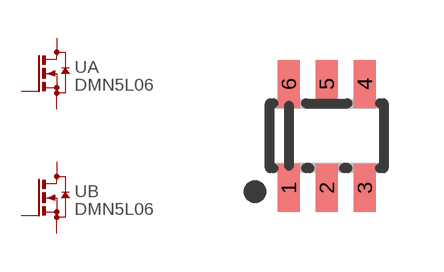
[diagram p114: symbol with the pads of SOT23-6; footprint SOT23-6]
Designator prefix -; gates A=N-MOS B=N-MOS

## DMN5L06DMK  [SOT23-6]
1  A:S  pas
2  A:G  pas
3  B:D  pas
4  B:S  pas
5  B:G  pas
6  A:D  pas

## Footprint SOT23-6 (pad centres in mm)
smd 0.55 x 1.2: 1 -0.95,-1.3; 2 0,-1.3; 3 0.95,-1.3; 4 0.95,1.3; 5 0,1.3; 6 -0.95,1.3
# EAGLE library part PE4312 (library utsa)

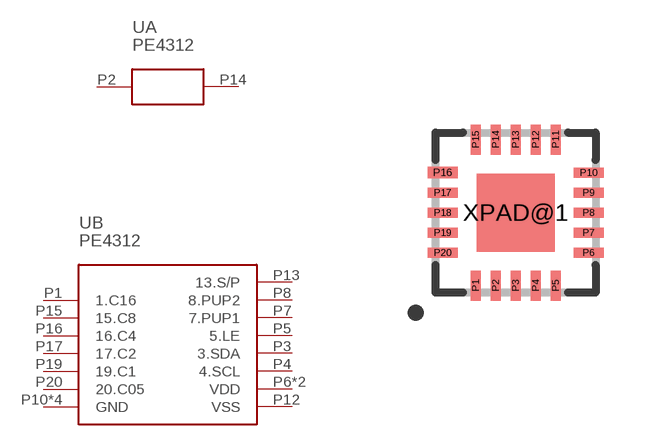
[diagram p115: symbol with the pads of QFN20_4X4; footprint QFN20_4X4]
Designator prefix -; gates A=PE4312 B=PE4312-CONTROL

## PE4312  [QFN20_4X4]
P1  B:1.C16
P2  A:2.RF1
P3  B:3.SDA
P4  B:4.SCL
P5  B:5.LE
P6  B:VDD
P7  B:7.PUP1
P8  B:8.PUP2
P9  B:VDD
P10  B:GND
P11  B:GND
P12  B:VSS
P13  B:13.S/P
P14  A:14.RF2
P15  B:15.C8
P16  B:16.C4
P17  B:17.C2
P18  B:GND
P19  B:19.C1
P20  B:20.C05
XPAD@1  B:GND

## Footprint QFN20_4X4 (pad centres in mm)
QFN 20 Body: 4 x 4 mm Pitch: 0.50 mm Based on: MAXIM's G2044-3
smd 0.25 x 0.75: P1 -1,-1.825; P2 -0.5,-1.825; P3 0,-1.825; P4 0.5,-1.825; P5 1,-1.825; P11 1,1.825; P12 0.5,1.825; P13 0,1.825; P14 -0.5,1.825; P15 -1,1.825
smd 0.75 x 0.25: P6 1.825,-1; P7 1.825,-0.5; P8 1.825,0; P9 1.825,0.5; P10 1.825,1; P17 -1.825,0.5; P18 -1.825,0; P19 -1.825,-0.5; P20 -1.825,-1
smd 0.75 x 0.28: P16 -1.825,1
smd 1.95 x 1.95: XPAD@1 0,0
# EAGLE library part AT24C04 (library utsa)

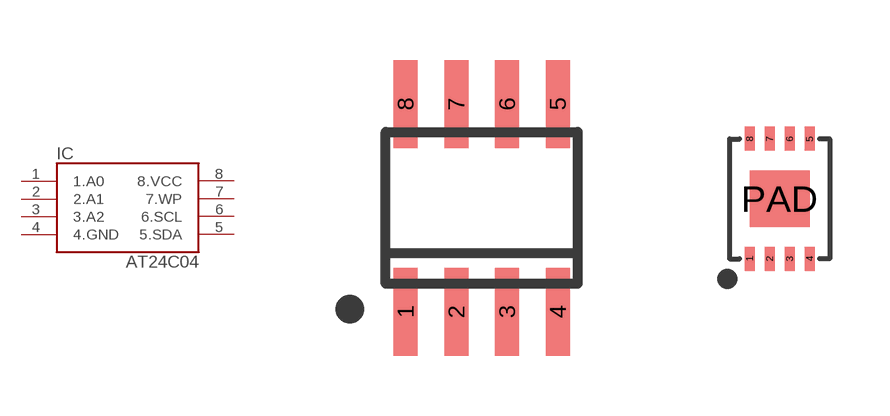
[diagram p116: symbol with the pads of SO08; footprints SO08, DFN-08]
Designator prefix IC

## AT24C04SO  [SO08]
1  1.A0
2  2.A1
3  3.A2
4  4.GND
5  5.SDA
6  6.SCL
7  7.WP
8  8.VCC

## AT24C04  [DFN-08]
Pads as for SO08

## Footprint SO08 (pad centres in mm)
SMALL OUTLINE INTEGRATED CIRCUIT body 3.9 mm/JEDEC MS-012AA
smd 0.6 x 2.2: 1 -1.905,-2.6; 2 -0.635,-2.6; 3 0.635,-2.6; 4 1.905,-2.6; 5 1.905,2.6; 6 0.635,2.6; 7 -0.635,2.6; 8 -1.905,2.6

## Footprint DFN-08 (pad centres in mm)
smd 0.25 x 0.6: 1 -0.75,-1.5; 2 -0.25,-1.5; 3 0.25,-1.5; 4 0.75,-1.5; 5 0.75,1.5; 6 0.25,1.5; 7 -0.25,1.5; 8 -0.75,1.5
smd 1.5 x 1.4: PAD 0,0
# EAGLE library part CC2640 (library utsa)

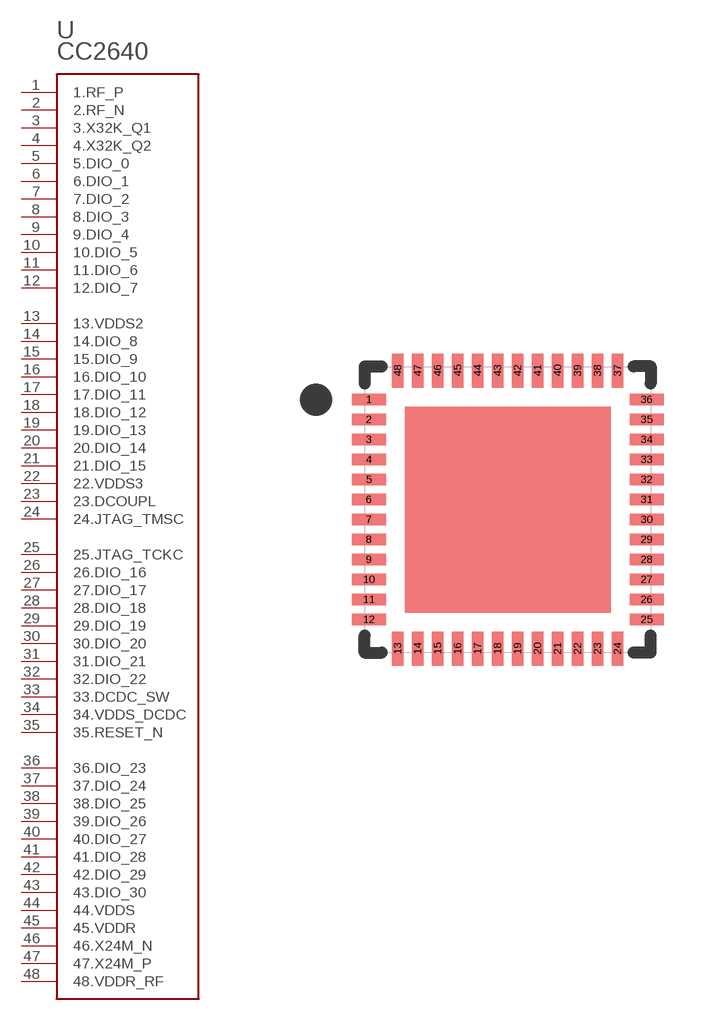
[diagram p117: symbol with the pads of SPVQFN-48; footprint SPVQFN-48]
Designator prefix -

## CC2640RGZ  [SPVQFN-48]
1  1.RF_P
2  2.RF_N
3  3.X32K_Q1
4  4.X32K_Q2
5  5.DIO_0
6  6.DIO_1
7  7.DIO_2
8  8.DIO_3
9  9.DIO_4
10  10.DIO_5
11  11.DIO_6
12  12.DIO_7
13  13.VDDS2
14  14.DIO_8
15  15.DIO_9
16  16.DIO_10
17  17.DIO_11
18  18.DIO_12
19  19.DIO_13
20  20.DIO_14
21  21.DIO_15
22  22.VDDS3
23  23.DCOUPL
24  24.JTAG_TMSC
25  25.JTAG_TCKC
26  26.DIO_16
27  27.DIO_17
28  28.DIO_18
29  29.DIO_19
30  30.DIO_20
31  31.DIO_21
32  32.DIO_22
33  33.DCDC_SW
34  34.VDDS_DCDC
35  35.RESET_N
36  36.DIO_23
37  37.DIO_24
38  38.DIO_25
39  39.DIO_26
40  40.DIO_27
41  41.DIO_28
42  42.DIO_29
43  43.DIO_30
44  44.VDDS
45  45.VDDR
46  46.X24M_N
47  47.X24M_P
48  48.VDDR_RF

## Footprint SPVQFN-48 (pad centres in mm)
smd 0.85 x 0.28: 1 -3.475,2.75; 2 -3.475,2.25; 3 -3.475,1.75; 4 -3.475,1.25; 5 -3.475,0.75; 6 -3.475,0.25; 7 -3.475,-0.25; 8 -3.475,-0.75; 9 -3.475,-1.25; 10 -3.475,-1.75; 11 -3.475,-2.25; 12 -3.475,-2.75; 25 3.475,-2.75; 26 3.475,-2.25; 27 3.475,-1.75; 28 3.475,-1.25; 29 3.475,-0.75; 30 3.475,-0.25; 31 3.475,0.25; 32 3.475,0.75; 33 3.475,1.25; 34 3.475,1.75; 35 3.475,2.25; 36 3.475,2.75
smd 0.28 x 0.85: 13 -2.75,-3.475; 14 -2.25,-3.475; 15 -1.75,-3.475; 16 -1.25,-3.475; 17 -0.75,-3.475; 18 -0.25,-3.475; 19 0.25,-3.475; 20 0.75,-3.475; 21 1.25,-3.475; 22 1.75,-3.475; 23 2.25,-3.475; 24 2.75,-3.475; 37 2.75,3.475; 38 2.25,3.475; 39 1.75,3.475; 40 1.25,3.475; 41 0.75,3.475; 42 0.25,3.475; 43 -0.25,3.475; 44 -0.75,3.475; 45 -1.25,3.475; 46 -1.75,3.475; 47 -2.25,3.475; 48 -2.75,3.475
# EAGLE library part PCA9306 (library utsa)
I2C Level shifter

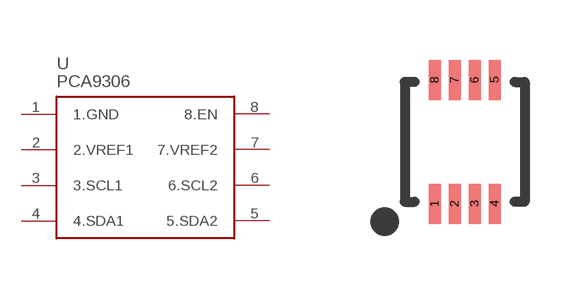
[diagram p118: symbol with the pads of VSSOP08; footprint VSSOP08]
Designator prefix -

## PCA9306DCU  [VSSOP08]
1  1.GND
2  2.VREF1
3  3.SCL1
4  4.SDA1
5  5.SDA2
6  6.SCL2
7  7.VREF2
8  8.EN

## Footprint VSSOP08 (pad centres in mm)
smd 0.3 x 1: 1 -0.75,-1.55; 2 -0.25,-1.55; 3 0.25,-1.55; 4 0.75,-1.55; 5 0.75,1.55; 6 0.25,1.55; 7 -0.25,1.55; 8 -0.75,1.55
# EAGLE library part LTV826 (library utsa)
OPTO COUPLER Source: LITEON, LTV816.pdf

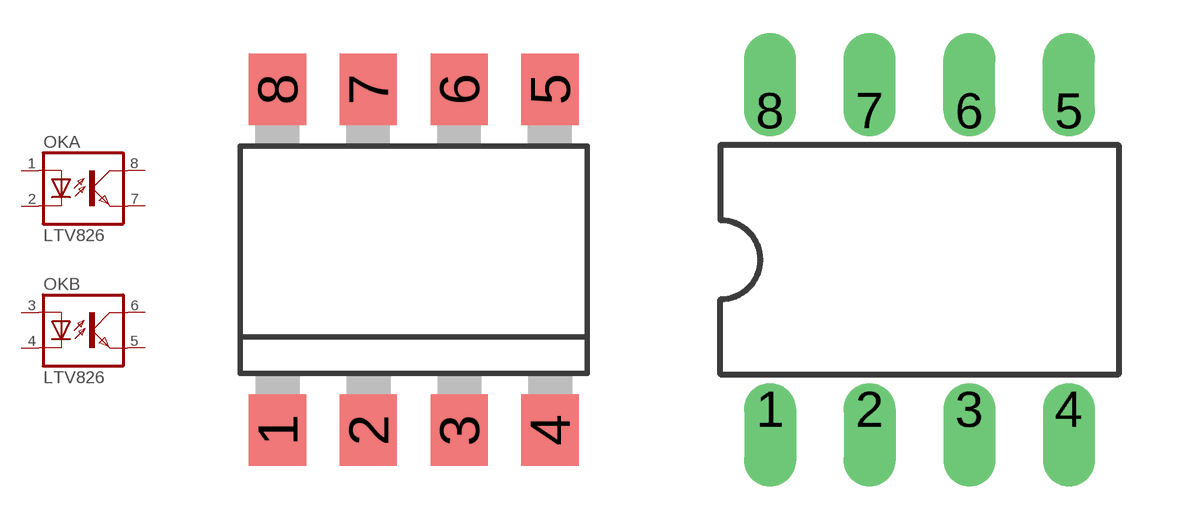
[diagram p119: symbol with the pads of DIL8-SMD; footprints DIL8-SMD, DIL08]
Designator prefix OK; gates A=OK B=OK

## LTV826S (OC_FARNELL: unknown; OC_NEWARK: unknown)  [DIL8-SMD]
1  A:A  pas
2  A:C  pas
3  B:A  pas
4  B:C  pas
5  B:EMIT  pas
6  B:COL  pas
7  A:EMIT  pas
8  A:COL  pas

## LTV826 (OC_FARNELL: unknown; OC_NEWARK: unknown)  [DIL08]
Pads as for DIL8-SMD

## Footprint DIL8-SMD (pad centres in mm)
Dual In Line SMD 8 pol. Source: LITE-ON ELECTRONICS, LTV816.pdf
smd 1.6 x 2: 1 -3.81,-4.77; 2 -1.27,-4.77; 3 1.27,-4.77; 4 3.81,-4.77; 5 3.81,4.77; 6 1.27,4.77; 7 -1.27,4.77; 8 -3.81,4.77

## Footprint DIL08 (pad centres in mm)
Dual In Line Package
drill 0.813 offset: 1 -3.81,-3.81; 2 -1.27,-3.81; 3 1.27,-3.81; 4 3.81,-3.81; 5 3.81,3.81; 6 1.27,3.81; 7 -1.27,3.81; 8 -3.81,3.81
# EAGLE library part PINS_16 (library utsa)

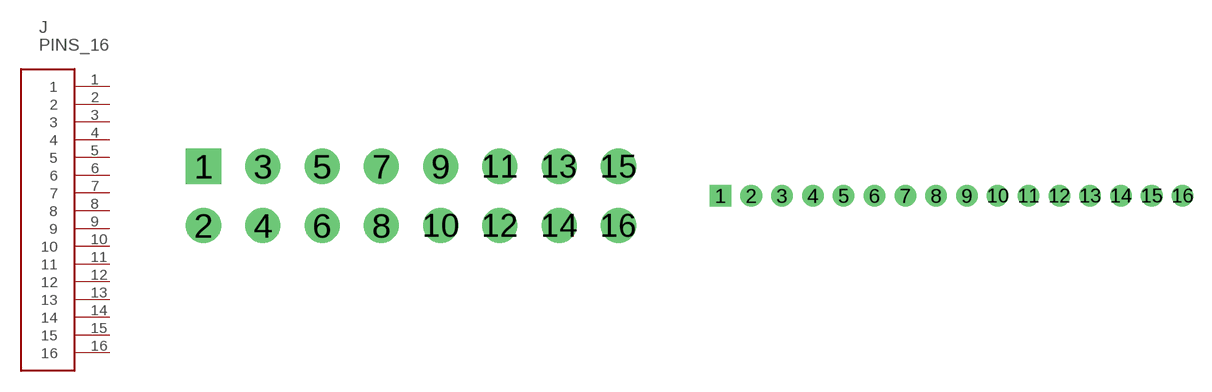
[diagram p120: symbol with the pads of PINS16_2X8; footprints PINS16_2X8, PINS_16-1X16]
Designator prefix J

## PINS_162X8  [PINS16_2X8]
1  1
2  2
3  3
4  4
5  5
6  6
7  7
8  8
9  9
10  10
11  11
12  12
13  13
14  14
15  15
16  16

## PINS_161X16  [PINS_16-1X16]
Pads as for PINS16_2X8

## Footprint PINS16_2X8 (pad centres in mm)
drill 1 square: 1 0,0
drill 1: 2 0,-2.54; 3 2.54,0; 4 2.54,-2.54; 5 5.08,0; 6 5.08,-2.54; 7 7.62,0; 8 7.62,-2.54; 9 10.16,0; 10 10.16,-2.54; 11 12.7,0; 12 12.7,-2.54; 13 15.24,0; 14 15.24,-2.54; 15 17.78,0; 16 17.78,-2.54

## Footprint PINS_16-1X16 (pad centres in mm)
drill 1.1 pad 1.778 square: 1 0,0
drill 1.1 pad 1.778: 2 2.54,0; 3 5.08,0; 4 7.62,0; 5 10.16,0; 6 12.7,0; 7 15.24,0; 8 17.78,0; 9 20.32,0; 10 22.86,0; 11 25.4,0; 12 27.94,0; 13 30.48,0; 14 33.02,0; 15 35.56,0; 16 38.1,0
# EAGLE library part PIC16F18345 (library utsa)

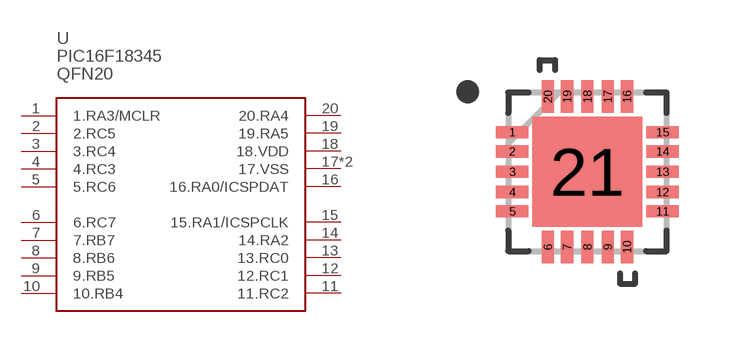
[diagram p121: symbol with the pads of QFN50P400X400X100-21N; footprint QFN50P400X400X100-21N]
Designator prefix -

## PIC16F18345  [QFN50P400X400X100-21N]
1  1.RA3/MCLR
2  2.RC5
3  3.RC4
4  4.RC3
5  5.RC6
6  6.RC7
7  7.RB7
8  8.RB6
9  9.RB5
10  10.RB4
11  11.RC2
12  12.RC1
13  13.RC0
14  14.RA2
15  15.RA1/ICSPCLK
16  16.RA0/ICSPDAT
17  17.VSS
18  18.VDD
19  19.RA5
20  20.RA4
21  17.VSS

## Footprint QFN50P400X400X100-21N (pad centres in mm)
smd 0.813 x 0.305: 1 -1.88,0.991; 2 -1.88,0.508; 3 -1.88,0; 4 -1.88,-0.508; 5 -1.88,-0.991; 11 1.88,-0.991; 12 1.88,-0.508; 13 1.88,0; 14 1.88,0.508; 15 1.88,0.991
smd 0.305 x 0.813: 6 -0.991,-1.88; 7 -0.508,-1.88; 8 0,-1.88; 9 0.508,-1.88; 10 0.991,-1.88; 16 0.991,1.88; 17 0.508,1.88; 18 0,1.88; 19 -0.508,1.88; 20 -0.991,1.88
smd 2.743 x 2.743: 21 0,0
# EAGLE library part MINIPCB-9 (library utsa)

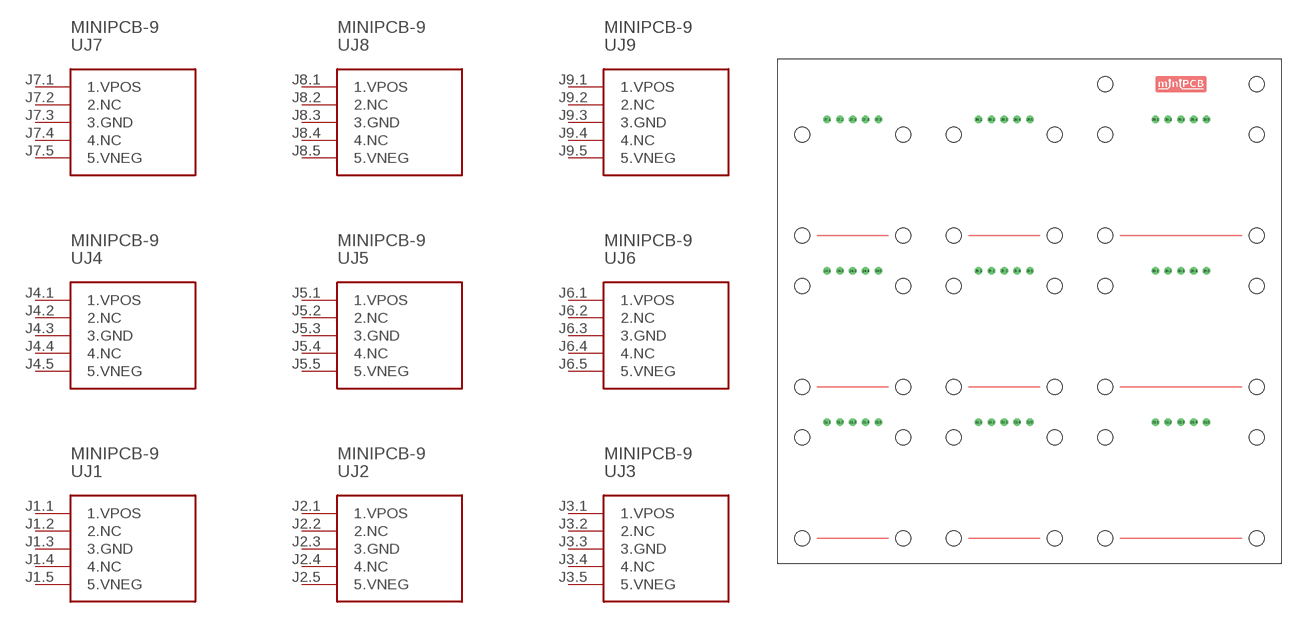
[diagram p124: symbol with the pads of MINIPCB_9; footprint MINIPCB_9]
Designator prefix -; gates J1=MINIPCB-5PIN J2=MINIPCB-5PIN J3=MINIPCB-5PIN J4=MINIPCB-5PIN J5=MINIPCB-5PIN J6=MINIPCB-5PIN J7=MINIPCB-5PIN J8=MINIPCB-5PIN J9=MINIPCB-5PIN

## MINIPCB-9  [MINIPCB_9]
J1.1  J1:1.VPOS
J1.2  J1:2.NC
J1.3  J1:3.GND
J1.4  J1:4.NC
J1.5  J1:5.VNEG
J2.1  J2:1.VPOS
J2.2  J2:2.NC
J2.3  J2:3.GND
J2.4  J2:4.NC
J2.5  J2:5.VNEG
J3.1  J3:1.VPOS
J3.2  J3:2.NC
J3.3  J3:3.GND
J3.4  J3:4.NC
J3.5  J3:5.VNEG
J4.1  J4:1.VPOS
J4.2  J4:2.NC
J4.3  J4:3.GND
J4.4  J4:4.NC
J4.5  J4:5.VNEG
J5.1  J5:1.VPOS
J5.2  J5:2.NC
J5.3  J5:3.GND
J5.4  J5:4.NC
J5.5  J5:5.VNEG
J6.1  J6:1.VPOS
J6.2  J6:2.NC
J6.3  J6:3.GND
J6.4  J6:4.NC
J6.5  J6:5.VNEG
J7.1  J7:1.VPOS
J7.2  J7:2.NC
J7.3  J7:3.GND
J7.4  J7:4.NC
J7.5  J7:5.VNEG
J8.1  J8:1.VPOS
J8.2  J8:2.NC
J8.3  J8:3.GND
J8.4  J8:4.NC
J8.5  J8:5.VNEG
J9.1  J9:1.VPOS
J9.2  J9:2.NC
J9.3  J9:3.GND
J9.4  J9:4.NC
J9.5  J9:5.VNEG

## Footprint MINIPCB_9 (pad centres in mm)
drill 1: J1.1 9.92,28; J1.2 12.46,28; J1.3 15,28; J1.4 17.54,28; J1.5 20.08,28; J2.1 39.92,28; J2.2 42.46,28; J2.3 45,28; J2.4 47.54,28; J2.5 50.08,28; J3.1 74.92,28; J3.2 77.46,28; J3.3 80,28; J3.4 82.54,28; J3.5 85.08,28; J4.1 9.92,58; J4.2 12.46,58; J4.3 15,58; J4.4 17.54,58; J4.5 20.08,58; J5.1 39.92,58; J5.2 42.46,58; J5.3 45,58; J5.4 47.54,58; J5.5 50.08,58; J6.1 74.92,58; J6.2 77.46,58; J6.3 80,58; J6.4 82.54,58; J6.5 85.08,58; J7.1 9.92,88; J7.2 12.46,88; J7.3 15,88; J7.4 17.54,88; J7.5 20.08,88; J8.1 39.92,88; J8.2 42.46,88; J8.3 45,88; J8.4 47.54,88; J8.5 50.08,88; J9.1 74.92,88; J9.2 77.46,88; J9.3 80,88; J9.4 82.54,88; J9.5 85.08,88
hole 2.9 at 95,95
hole 2.9 at 65,95
hole 2.9 at 5,85
hole 2.9 at 55,85
hole 2.9 at 65,85
hole 2.9 at 95,85
hole 2.9 at 5,65
hole 2.9 at 55,65
hole 2.9 at 65,65
hole 2.9 at 95,65
hole 2.9 at 5,55
hole 2.9 at 55,55
hole 2.9 at 65,55
hole 2.9 at 95,55
hole 2.9 at 5,5
hole 2.9 at 55,5
hole 2.9 at 65,5
hole 2.9 at 95,5
hole 2.9 at 25,5
hole 2.9 at 25,65
hole 2.9 at 35,65
hole 2.9 at 35,55
hole 2.9 at 25,55
hole 2.9 at 5,25
hole 2.9 at 25,25
hole 2.9 at 35,25
hole 2.9 at 55,25
hole 2.9 at 65,25
hole 2.9 at 95,25
hole 2.9 at 95,35
hole 2.9 at 65,35
hole 2.9 at 25,85
hole 2.9 at 35,85
hole 2.9 at 35,5
hole 2.9 at 5,35
hole 2.9 at 25,35
hole 2.9 at 35,35
hole 2.9 at 55,35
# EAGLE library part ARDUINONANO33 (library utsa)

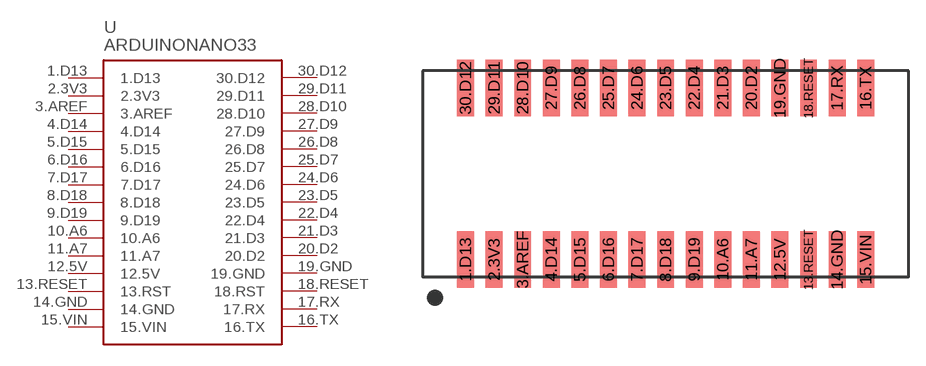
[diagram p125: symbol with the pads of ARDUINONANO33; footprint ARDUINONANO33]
Designator prefix -

## ARDUINONANO33  [ARDUINONANO33]
1.D13  1.D13
2.3V3  2.3V3
3.AREF  3.AREF
4.D14  4.D14
5.D15  5.D15
6.D16  6.D16
7.D17  7.D17
8.D18  8.D18
9.D19  9.D19
10.A6  10.A6
11.A7  11.A7
12.5V  12.5V
13.RESET  13.RST
14.GND  14.GND
15.VIN  15.VIN
16.TX  16.TX
17.RX  17.RX
18.RESET  18.RST
19.GND  19.GND
20.D2  20.D2
21.D3  21.D3
22.D4  22.D4
23.D5  23.D5
24.D6  24.D6
25.D7  25.D7
26.D8  26.D8
27.D9  27.D9
28.D10  28.D10
29.D11  29.D11
30.D12  30.D12

## Footprint ARDUINONANO33 (pad centres in mm)
smd 1.5 x 5: 1.D13 -17.78,-7.62; 2.3V3 -15.24,-7.62; 3.AREF -12.7,-7.62; 4.D14 -10.16,-7.62; 5.D15 -7.62,-7.62; 6.D16 -5.08,-7.62; 7.D17 -2.54,-7.62; 8.D18 0,-7.62; 9.D19 2.54,-7.62; 10.A6 5.08,-7.62; 11.A7 7.62,-7.62; 12.5V 10.16,-7.62; 13.RESET 12.7,-7.62; 14.GND 15.24,-7.62; 15.VIN 17.78,-7.62; 16.TX 17.78,7.62; 17.RX 15.24,7.62; 18.RESET 12.7,7.62; 19.GND 10.16,7.62; 20.D2 7.62,7.62; 21.D3 5.08,7.62; 22.D4 2.54,7.62; 23.D5 0,7.62; 24.D6 -2.54,7.62; 25.D7 -5.08,7.62; 26.D8 -7.62,7.62; 27.D9 -10.16,7.62; 28.D10 -12.7,7.62; 29.D11 -15.24,7.62; 30.D12 -17.78,7.62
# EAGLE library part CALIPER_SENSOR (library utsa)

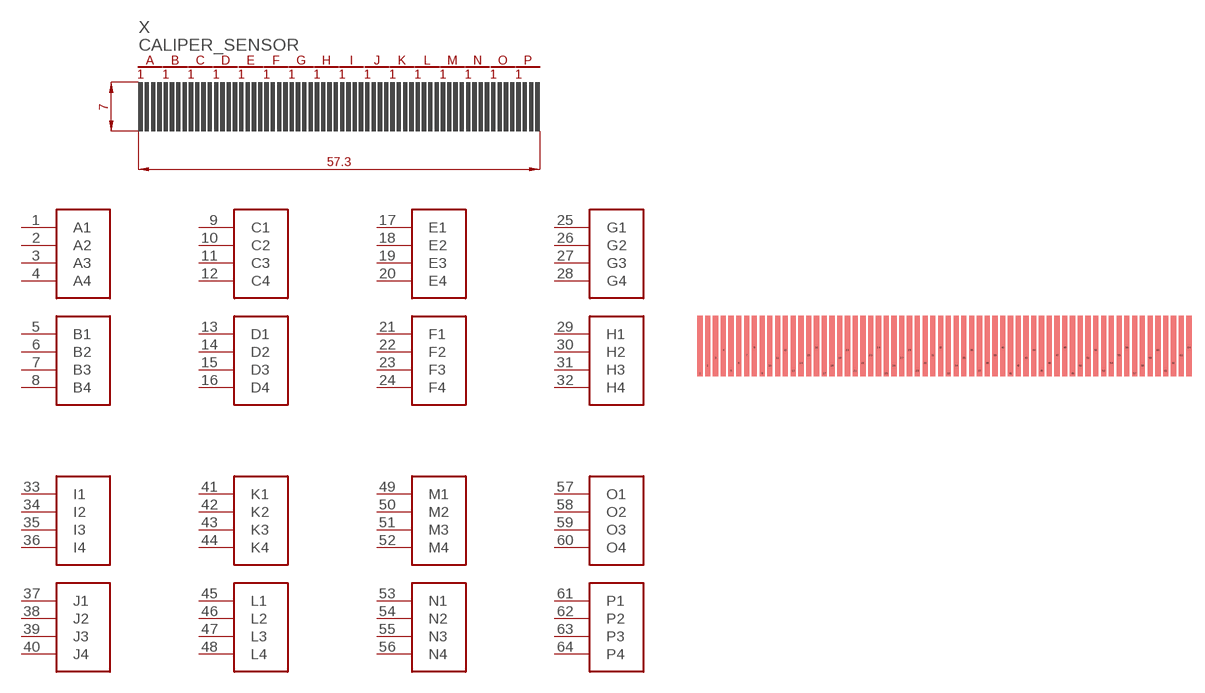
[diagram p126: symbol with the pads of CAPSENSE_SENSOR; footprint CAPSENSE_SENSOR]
Designator prefix X

## CALIPER_SENSOR  [CAPSENSE_SENSOR]
1  A1
2  A2
3  A3
4  A4
5  B1
6  B2
7  B3
8  B4
9  C1
10  C2
11  C3
12  C4
13  D1
14  D2
15  D3
16  D4
17  E1
18  E2
19  E3
20  E4
21  F1
22  F2
23  F3
24  F4
25  G1
26  G2
27  G3
28  G4
29  H1
30  H2
31  H3
32  H4
33  I1
34  I2
35  I3
36  I4
37  J1
38  J2
39  J3
40  J4
41  K1
42  K2
43  K3
44  K4
45  L1
46  L2
47  L3
48  L4
49  M1
50  M2
51  M3
52  M4
53  N1
54  N2
55  N3
56  N4
57  O1
58  O2
59  O3
60  O4
61  P1
62  P2
63  P3
64  P4

## Footprint CAPSENSE_SENSOR (pad centres in mm)
smd 0.3 x 0.3: 1 0.3,0.3; 2 1.2,1.2; 3 2.1,2.1; 4 3,3; 5 3.9,0.6; 6 4.8,1.5; 7 5.7,2.4; 8 6.6,3.3; 9 7.5,0.3; 10 8.4,1.2; 11 9.3,2.1; 12 10.2,3; 13 11.1,0.6; 14 12,1.5; 15 12.9,2.4; 16 13.8,3.3; 17 14.7,0.3; 18 15.6,1.2; 19 16.5,2.1; 20 17.4,3; 21 18.3,0.6; 22 19.2,1.5; 23 20.1,2.4; 24 21,3.3; 25 21.9,0.3; 26 22.8,1.2; 27 23.7,2.1; 28 24.6,3; 29 25.5,0.6; 30 26.4,1.5; 31 27.3,2.4; 32 28.2,3.3; 33 29.1,0.3; 34 30,1.2; 35 30.9,2.1; 36 31.8,3; 37 32.7,0.6; 38 33.6,1.5; 39 34.5,2.4; 40 35.4,3.3; 41 36.3,0.3; 42 37.2,1.2; 43 38.1,2.1; 44 39,3; 45 39.9,0.6; 46 40.8,1.5; 47 41.7,2.4; 48 42.6,3.3; 49 43.5,0.3; 50 44.4,1.2; 51 45.3,2.1; 52 46.2,3; 53 47.1,0.6; 54 48,1.5; 55 48.9,2.4; 56 49.8,3.3; 57 50.7,0.3; 58 51.6,1.2; 59 52.5,2.1; 60 53.4,3; 61 54.3,0.6; 62 55.2,1.5; 63 56.1,2.4; 64 57,3.3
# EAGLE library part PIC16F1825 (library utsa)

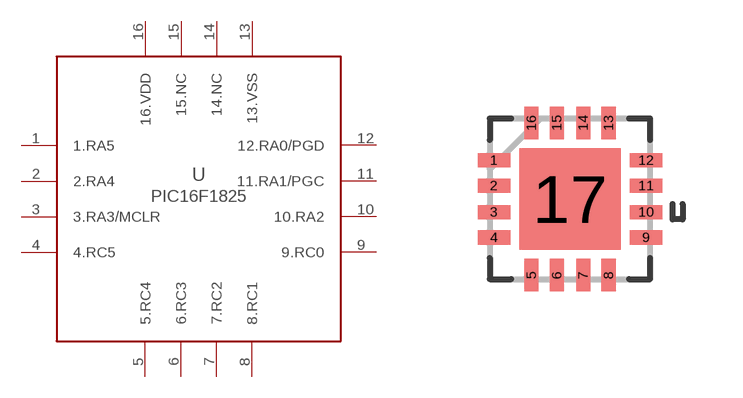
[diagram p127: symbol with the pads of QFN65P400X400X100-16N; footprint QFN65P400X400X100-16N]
Designator prefix U

## PIC16F1825/ML  [QFN65P400X400X100-16N]
1  1.RA5
2  2.RA4
3  3.RA3/MCLR
4  4.RC5
5  5.RC4
6  6.RC3
7  7.RC2
8  8.RC1
9  9.RC0
10  10.RA2
11  11.RA1/PGC
12  12.RA0/PGD
13  13.VSS
14  14.NC
15  15.NC
16  16.VDD

## Footprint QFN65P400X400X100-16N (pad centres in mm)
smd 0.813 x 0.356: 1 -1.905,0.965; 2 -1.905,0.33; 3 -1.905,-0.33; 4 -1.905,-0.965; 9 1.905,-0.965; 10 1.905,-0.33; 11 1.905,0.33; 12 1.905,0.965
smd 0.356 x 0.813: 5 -0.965,-1.905; 6 -0.33,-1.905; 7 0.33,-1.905; 8 0.965,-1.905; 13 0.965,1.905; 14 0.33,1.905; 15 -0.33,1.905; 16 -0.965,1.905
smd 2.54 x 2.54: 17 0,0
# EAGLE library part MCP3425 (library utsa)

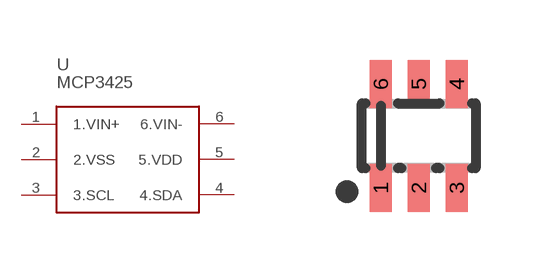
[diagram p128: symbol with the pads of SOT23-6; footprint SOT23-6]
Designator prefix U

## MCP3425-E  [SOT23-6]
1  1.VIN+
2  2.VSS
3  3.SCL
4  4.SDA
5  5.VDD
6  6.VIN-

## Footprint SOT23-6 (pad centres in mm)
smd 0.55 x 1.2: 1 -0.95,-1.3; 2 0,-1.3; 3 0.95,-1.3; 4 0.95,1.3; 5 0,1.3; 6 -0.95,1.3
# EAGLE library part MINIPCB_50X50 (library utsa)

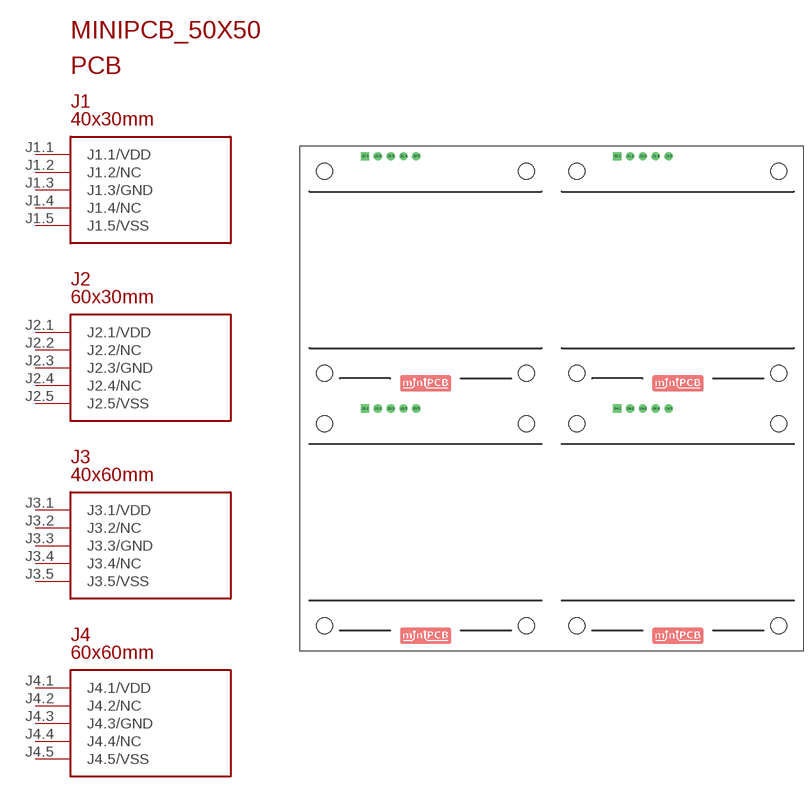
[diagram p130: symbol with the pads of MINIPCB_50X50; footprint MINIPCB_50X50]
Designator prefix PCB

## MINIPCB_50X50  [MINIPCB_50X50]
J1.1  J1.1/VDD
J1.2  J1.2/NC
J1.3  J1.3/GND
J1.4  J1.4/NC
J1.5  J1.5/VSS
J2.1  J2.1/VDD
J2.2  J2.2/NC
J2.3  J2.3/GND
J2.4  J2.4/NC
J2.5  J2.5/VSS
J3.1  J3.1/VDD
J3.2  J3.2/NC
J3.3  J3.3/GND
J3.4  J3.4/NC
J3.5  J3.5/VSS
J4.1  J4.1/VDD
J4.2  J4.2/NC
J4.3  J4.3/GND
J4.4  J4.4/NC
J4.5  J4.5/VSS

## Footprint MINIPCB_50X50 (pad centres in mm)
drill 1.1 square: J1.1 63,98; J2.1 13,98; J3.1 13,48; J4.1 63,48
drill 1.1: J1.2 65.54,98; J1.3 68.08,98; J1.4 70.62,98; J1.5 73.16,98; J2.2 15.54,98; J2.3 18.08,98; J2.4 20.62,98; J2.5 23.16,98; J3.2 15.54,48; J3.3 18.08,48; J3.4 20.62,48; J3.5 23.16,48; J4.2 65.54,48; J4.3 68.08,48; J4.4 70.62,48; J4.5 73.16,48
hole 3.2 at 5,95
hole 3.2 at 45,95
hole 3.2 at 5,55
hole 3.2 at 45,55
hole 3.2 at 55,55
hole 3.2 at 55,95
hole 3.2 at 95,95
hole 3.2 at 95,55
hole 3.2 at 95,45
hole 3.2 at 55,45
hole 3.2 at 45,45
hole 3.2 at 5,45
hole 3.2 at 5,5
hole 3.2 at 45,5
hole 3.2 at 55,5
hole 3.2 at 95,5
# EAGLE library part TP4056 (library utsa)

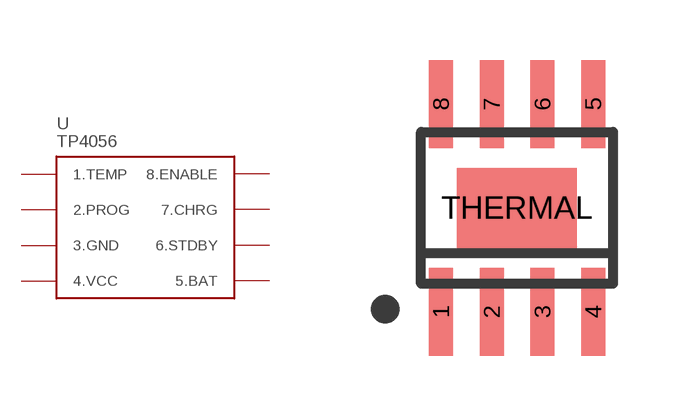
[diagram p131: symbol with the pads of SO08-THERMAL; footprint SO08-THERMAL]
Designator prefix U

## TP4056  [SO08-THERMAL]
1  1.TEMP
2  2.PROG
3  3.GND
4  4.VCC
5  5.BAT
6  6.STDBY
7  7.CHRG
8  8.ENABLE
THERMAL  3.GND

## Footprint SO08-THERMAL (pad centres in mm)
smd 0.6 x 2.2: 1 -1.905,-2.6; 2 -0.635,-2.6; 3 0.635,-2.6; 4 1.905,-2.6; 5 1.905,2.6; 6 0.635,2.6; 7 -0.635,2.6; 8 -1.905,2.6
smd 3 x 2: THERMAL 0,0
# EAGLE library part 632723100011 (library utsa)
USB 3.1 TYPE C RECEPTACLE - HORIZONTAL THT/SMT =>ConUSB31 632723X00011 Characteristics INSULATOR: LCP FLAMMABILITY RATING: UL94-V0 COLOR: BLACK CONTACT MATERIAL: BRASS CONTACT PLATING: GOLD OVERPd-Ni CONTACT AREA: 30μ’’ Pd-Ni+2μ’’ Gold QUALITY CLASS: 10 000 MATING CYCLES OPERATING TEMPERATURE:-25°C UP TO +105°C COMPLIANCE: LEAD FREE AND ROHS ELECTRICAL CURRENT RATING: 3 A MAX WORKING VOLTAGE: 5 VDC WITHSTANDING VOLTAGE: 100 VAC/MIN INSULATION RESISTANCE: >1000 MΩ CONTACT RESISTANCE: 30 mΩ MAX Details see: http://katalog.we-online.de/en/em/COM_3_1_THT_SMT_TYPE_C_RECEPTACLE_HORIZONTAL/632723100011 2015 (C) Wurth Elektronik

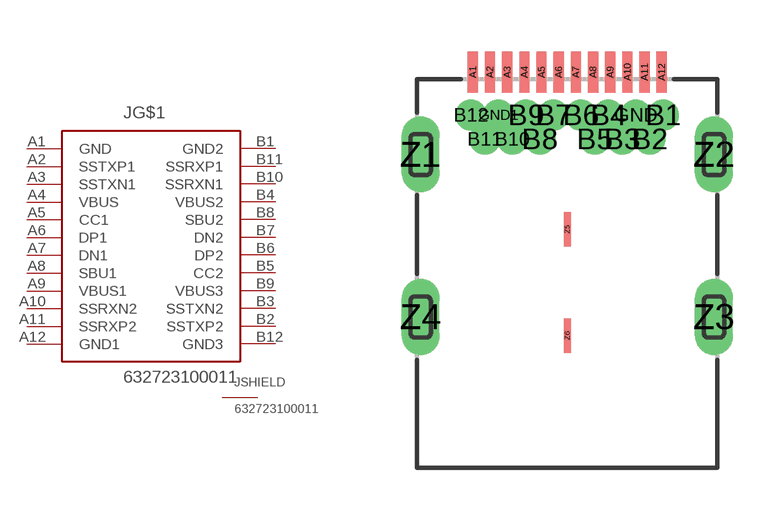
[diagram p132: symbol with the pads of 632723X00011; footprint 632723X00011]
Designator prefix J; gates G$1=632723X00011 SHIELD=SHIELD

## 632723100011  [632723X00011]
A1  G$1:GND
A2  G$1:SSTXP1
A3  G$1:SSTXN1
A4  G$1:VBUS
A5  G$1:CC1
A6  G$1:DP1
A7  G$1:DN1
A8  G$1:SBU1
A9  G$1:VBUS1
A10  G$1:SSRXN2
A11  G$1:SSRXP2
A12  G$1:GND1
B1  G$1:GND2
B2  G$1:SSTXP2
B3  G$1:SSTXN2
B4  G$1:VBUS2
B5  G$1:CC2
B6  G$1:DP2
B7  G$1:DN2
B8  G$1:SBU2
B9  G$1:VBUS3
B10  G$1:SSRXN1
B11  G$1:SSRXP1
B12  G$1:GND3
GND  SHIELD:SHIELD  pas
GND1  SHIELD:SHIELD  pas
Z1  SHIELD:SHIELD  pas
Z2  SHIELD:SHIELD  pas
Z3  SHIELD:SHIELD  pas
Z4  SHIELD:SHIELD  pas
Z5  SHIELD:SHIELD  pas
Z6  SHIELD:SHIELD  pas

## Footprint 632723X00011 (pad centres in mm)
smd 0.3 x 1.2: A1 -2.75,4.58; A2 -2.25,4.58; A3 -1.75,4.58; A4 -1.25,4.58; A5 -0.75,4.58; A6 -0.25,4.58; A7 0.25,4.58; A8 0.75,4.58; A9 1.25,4.58; A10 1.75,4.58; A11 2.25,4.58; A12 2.75,4.58
drill 0.4 pad 0.65: B1 2.8,3.33; B2 2.4,2.63; B3 1.6,2.63; B4 1.2,3.33; B5 0.8,2.63; B6 0.4,3.33; B7 -0.4,3.33; B8 -0.8,2.63; B9 -1.2,3.33; B10 -1.6,2.63; B11 -2.4,2.63; B12 -2.8,3.33; GND 2,3.33; GND1 -2,3.33
drill 0.6 pad 1 long: Z1 -4.27,2.18; Z2 4.27,2.18; Z3 4.27,-2.55; Z4 -4.27,-2.55
smd 0.2 x 1: Z5 0,0; Z6 0,-3.1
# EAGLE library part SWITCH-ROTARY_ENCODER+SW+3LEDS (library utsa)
PEL12T - 12 mm Encoder with Switch and Illuminated Shaft PEL12T-4xxxF-S1024

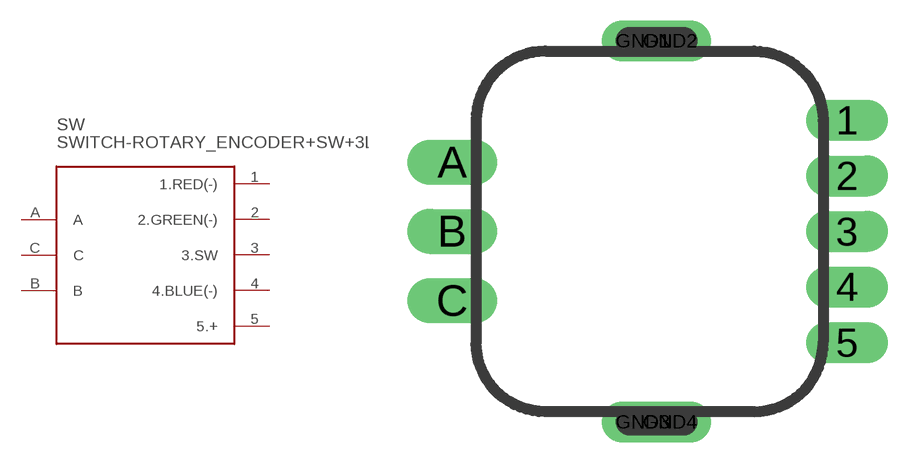
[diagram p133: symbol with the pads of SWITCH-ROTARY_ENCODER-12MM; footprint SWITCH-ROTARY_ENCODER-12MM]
Designator prefix SW

## SWITCH-ROTARY_ENCODER+SW+3LEDSPEL12T  [SWITCH-ROTARY_ENCODER-12MM]
1  1.RED(-)
2  2.GREEN(-)
3  3.SW
4  4.BLUE(-)
5  5.+
A  A
B  B
C  C

## Footprint SWITCH-ROTARY_ENCODER-12MM (pad centres in mm)
drill 1 long: 1 7,4.08; 2 7,2.04; 3 7,0; 4 7,-2.04; 5 7,-4.08; GND1 -0.5,7; GND2 0.5,7; GND3 -0.5,-7; GND4 0.5,-7
drill 1.1 long: A -7.5,2.54; B -7.5,0; C -7.5,-2.54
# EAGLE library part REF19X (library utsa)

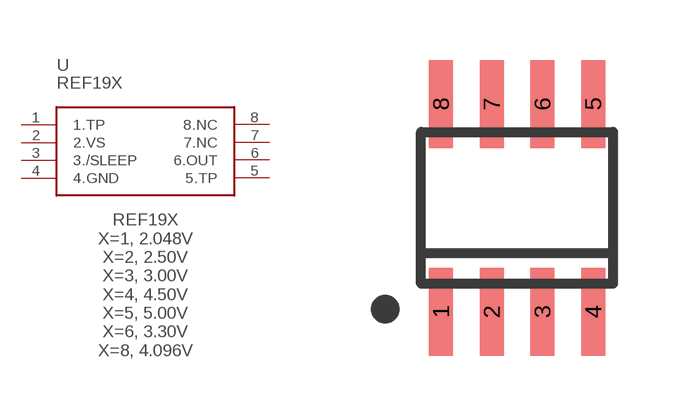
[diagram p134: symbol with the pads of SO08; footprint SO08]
Designator prefix U

## REF19XS  [SO08]
1  1.TP
2  2.VS
3  3./SLEEP
4  4.GND
5  5.TP
6  6.OUT
7  7.NC
8  8.NC

## Footprint SO08 (pad centres in mm)
SMALL OUTLINE INTEGRATED CIRCUIT body 3.9 mm/JEDEC MS-012AA
smd 0.6 x 2.2: 1 -1.905,-2.6; 2 -0.635,-2.6; 3 0.635,-2.6; 4 1.905,-2.6; 5 1.905,2.6; 6 0.635,2.6; 7 -0.635,2.6; 8 -1.905,2.6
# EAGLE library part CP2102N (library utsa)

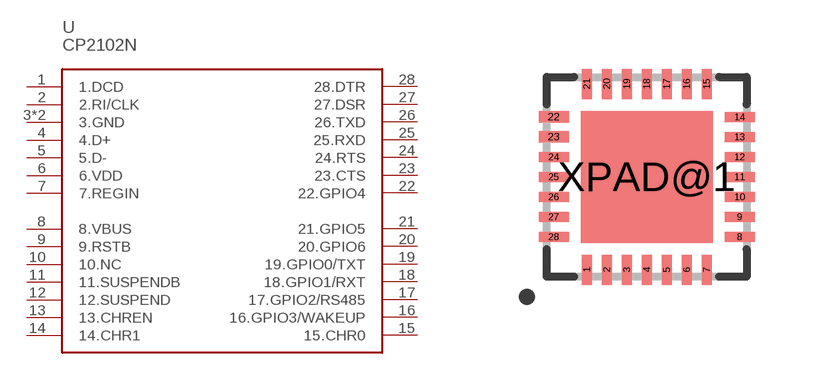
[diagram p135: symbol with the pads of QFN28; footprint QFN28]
Designator prefix U

## CP2102N-XXX-XQFN28  [QFN28]
1  1.DCD
2  2.RI/CLK
3  3.GND
4  4.D+
5  5.D-
6  6.VDD
7  7.REGIN
8  8.VBUS
9  9.RSTB
10  10.NC
11  11.SUSPENDB
12  12.SUSPEND
13  13.CHREN
14  14.CHR1
15  15.CHR0
16  16.GPIO3/WAKEUP
17  17.GPIO2/RS485
18  18.GPIO1/RXT
19  19.GPIO0/TXT
20  20.GPIO6
21  21.GPIO5
22  22.GPIO4
23  23.CTS
24  24.RTS
25  25.RXD
26  26.TXD
27  27.DSR
28  28.DTR
XPAD@1  3.GND

## Footprint QFN28 (pad centres in mm)
smd 0.25 x 0.75: 1 -1.5,-2.325; 2 -1,-2.325; 3 -0.5,-2.325; 4 0,-2.325; 5 0.5,-2.325; 6 1,-2.325; 7 1.5,-2.325; 15 1.5,2.325; 16 1,2.325; 17 0.5,2.325; 18 0,2.325; 19 -0.5,2.325; 20 -1,2.325; 21 -1.5,2.325
smd 0.75 x 0.25: 8 2.325,-1.5; 9 2.325,-1; 10 2.325,-0.5; 11 2.325,0; 12 2.325,0.5; 13 2.325,1; 14 2.325,1.5; 24 -2.325,0.5; 25 -2.325,0; 26 -2.325,-0.5; 27 -2.325,-1; 28 -2.325,-1.5
smd 0.75 x 0.28: 22 -2.325,1.5; 23 -2.325,1
smd 3.3 x 3.3: XPAD@1 0,0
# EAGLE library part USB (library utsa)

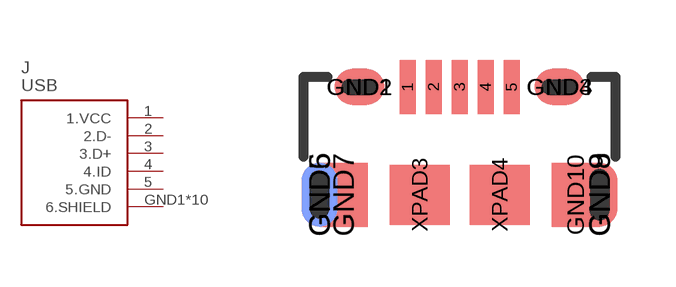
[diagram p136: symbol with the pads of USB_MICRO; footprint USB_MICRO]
Designator prefix J

## USB  [USB_MICRO]
1  1.VCC
2  2.D-
3  3.D+
4  4.ID
5  5.GND
GND1  6.SHIELD
GND2  6.SHIELD
GND3  6.SHIELD
GND4  6.SHIELD
GND5  6.SHIELD
GND6  6.SHIELD
GND7  6.SHIELD
GND8  6.SHIELD
GND9  6.SHIELD
GND10  6.SHIELD

## Footprint USB_MICRO (pad centres in mm)
smd 0.4 x 1.35: 1 -1.3,1.35; 2 -0.65,1.35; 3 0,1.35; 4 0.65,1.35; 5 1.3,1.35
smd 1.25 x 0.9: GND1 -2.5,1.35; GND4 2.5,1.35
smd 1.25 x 0.9 bottom: GND2 -2.5,1.35; GND3 2.5,1.35
smd 0.9 x 1.6: GND5 -3.5,-1.35; GND8 3.5,-1.35
smd 0.9 x 1.6 bottom: GND6 -3.5,-1.35; GND9 3.5,-1.35
smd 1.2 x 1.6: GND7 -2.9,-1.35; GND10 2.9,-1.35
smd 1.5 x 1.5: XPAD3 -1,-1.35; XPAD4 1,-1.35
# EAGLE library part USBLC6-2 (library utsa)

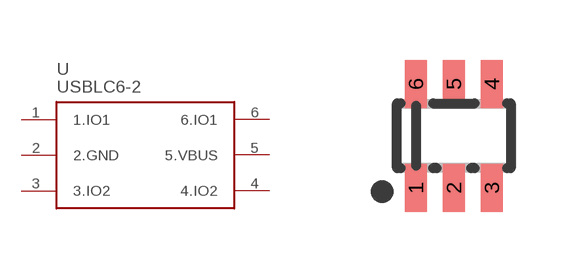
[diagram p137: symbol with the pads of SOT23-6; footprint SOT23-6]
Designator prefix U

## USBLC6-2  [SOT23-6]
1  1.IO1
2  2.GND
3  3.IO2
4  4.IO2
5  5.VBUS
6  6.IO1

## Footprint SOT23-6 (pad centres in mm)
smd 0.55 x 1.2: 1 -0.95,-1.3; 2 0,-1.3; 3 0.95,-1.3; 4 0.95,1.3; 5 0,1.3; 6 -0.95,1.3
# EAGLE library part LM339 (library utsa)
QUAD COMPARATOR

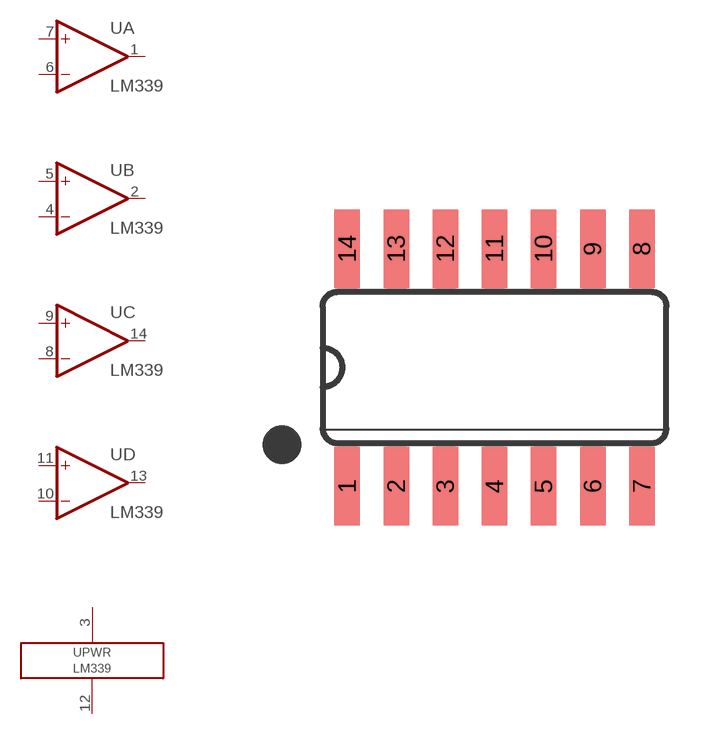
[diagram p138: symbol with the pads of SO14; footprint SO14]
Designator prefix U; gates A=OPAMP B=OPAMP C=OPAMP D=OPAMP PWR=PWR+-

## LM339-SO14  [SO14]
1  A:OUT  out
2  B:OUT  out
3  PWR:V+  pwr
4  B:-IN  in
5  B:+IN  in
6  A:-IN  in
7  A:+IN  in
8  C:-IN  in
9  C:+IN  in
10  D:-IN  in
11  D:+IN  in
12  PWR:V-  pwr
13  D:OUT  out
14  C:OUT  out

## Footprint SO14 (pad centres in mm)
Small Outline package 150 mil
smd 0.66 x 2.032: 1 -3.81,-3.073; 2 -2.54,-3.073; 3 -1.27,-3.073; 4 0,-3.073; 5 1.27,-3.073; 6 2.54,-3.073; 7 3.81,-3.073; 8 3.81,3.073; 9 2.54,3.073; 10 1.27,3.073; 11 0,3.073; 12 -1.27,3.073; 13 -2.54,3.073; 14 -3.81,3.073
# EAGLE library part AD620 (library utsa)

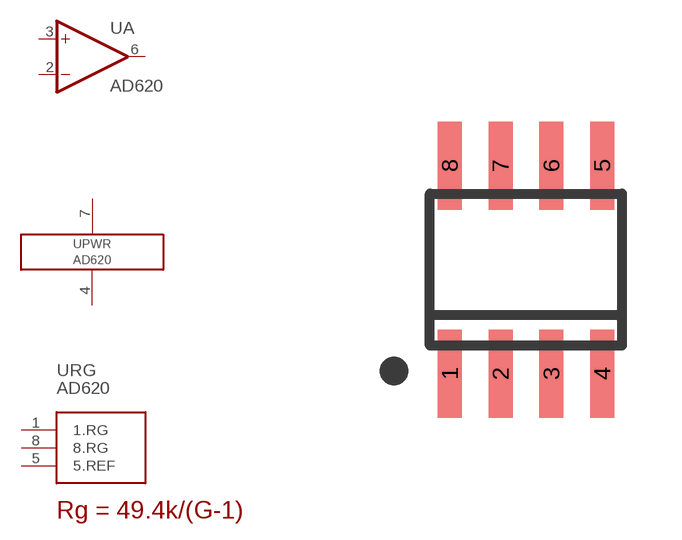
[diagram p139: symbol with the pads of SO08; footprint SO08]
Designator prefix -; gates A=OPAMP PWR=PWR+- RG=AD620RG

## AD620R  [SO08]
1  RG:1.RG
2  A:-IN  in
3  A:+IN  in
4  PWR:V-  pwr
5  RG:5.REF
6  A:OUT  out
7  PWR:V+  pwr
8  RG:8.RG

## Footprint SO08 (pad centres in mm)
SMALL OUTLINE INTEGRATED CIRCUIT body 3.9 mm/JEDEC MS-012AA
smd 0.6 x 2.2: 1 -1.905,-2.6; 2 -0.635,-2.6; 3 0.635,-2.6; 4 1.905,-2.6; 5 1.905,2.6; 6 0.635,2.6; 7 -0.635,2.6; 8 -1.905,2.6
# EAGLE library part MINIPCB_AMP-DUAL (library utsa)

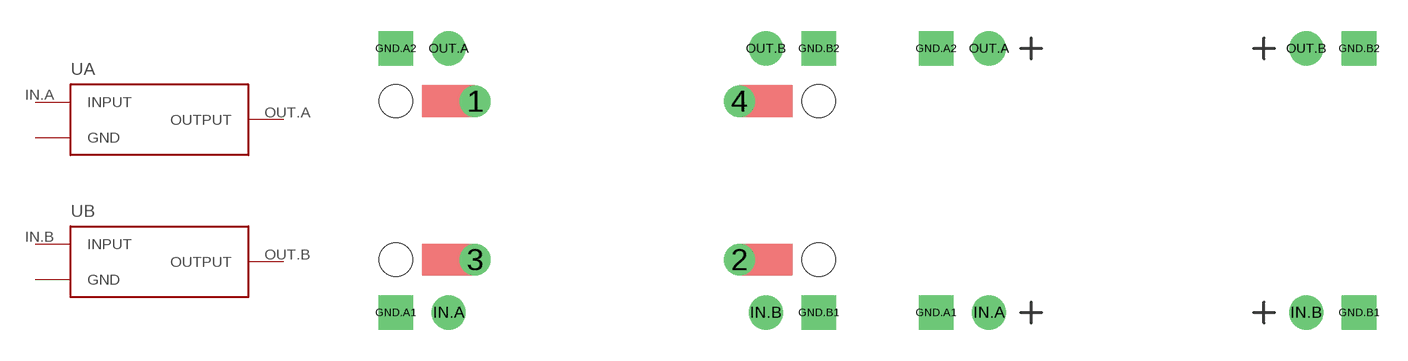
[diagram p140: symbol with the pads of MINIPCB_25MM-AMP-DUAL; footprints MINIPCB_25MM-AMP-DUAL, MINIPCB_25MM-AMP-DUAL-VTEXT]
Designator prefix -; gates A=MINIPCB_SYM-AMP B=MINIPCB_SYM-AMP

## MINIPCB_AMP-DUAL25  [MINIPCB_25MM-AMP-DUAL]
GND.A1  A:GND
GND.A2  A:GND
GND.B1  B:GND
GND.B2  B:GND
IN.A  A:INPUT
IN.B  B:INPUT
OUT.A  A:OUTPUT
OUT.B  B:OUTPUT

## MINIPCB_AMP-DUAL25-T  [MINIPCB_25MM-AMP-DUAL-VTEXT]
Pads as for MINIPCB_25MM-AMP-DUAL

## MINIPCB_AMP-DUAL50  [MINIPCB_50MM-AMP-DUAL]
Pads as for MINIPCB_25MM-AMP-DUAL

## Footprint MINIPCB_25MM-AMP-DUAL (pad centres in mm)
drill 1: 1 -6.35,3.81; 2 6.35,-3.81; 3 -6.35,-3.81; 4 6.35,3.81
drill 1.1 square: GND.A1 -10.16,-6.35; GND.A2 -10.16,6.35; GND.B1 10.16,-6.35; GND.B2 10.16,6.35
drill 1.1: IN.A -7.62,-6.35; IN.B 7.62,-6.35; OUT.A -7.62,6.35; OUT.B 7.62,6.35
hole 1.6 at 10.16,-3.81
hole 1.6 at -10.16,-3.81
hole 1.6 at -10.16,3.81
hole 1.6 at 10.16,3.81

## Footprint MINIPCB_25MM-AMP-DUAL-VTEXT (pad centres in mm)
drill 1.1 square: GND.A1 -10.16,-6.35; GND.A2 -10.16,6.35; GND.B1 10.16,-6.35; GND.B2 10.16,6.35
drill 1.1: IN.A -7.62,-6.35; IN.B 7.62,-6.35; OUT.A -7.62,6.35; OUT.B 7.62,6.35

## Footprint MINIPCB_50MM-AMP-DUAL (pad centres in mm)
drill 1.1 square: GND.A1 -21.59,-16.51; GND.A2 -21.59,16.51; GND.B1 21.59,-16.51; GND.B2 21.59,16.51
drill 1.1: IN.A -19.05,-16.51; IN.B 19.05,-16.51; OUT.A -19.05,16.51; OUT.B 19.05,16.51
drill 1: IN.A1 -6.35,-6.35; IN.B1 6.35,-6.35; OUT.A1 -6.35,6.35; OUT.B1 6.35,6.35
hole 1.6 at 10.16,-6.35
hole 1.6 at -10.16,-6.35
hole 1.6 at -10.16,6.35
hole 1.6 at 10.16,6.35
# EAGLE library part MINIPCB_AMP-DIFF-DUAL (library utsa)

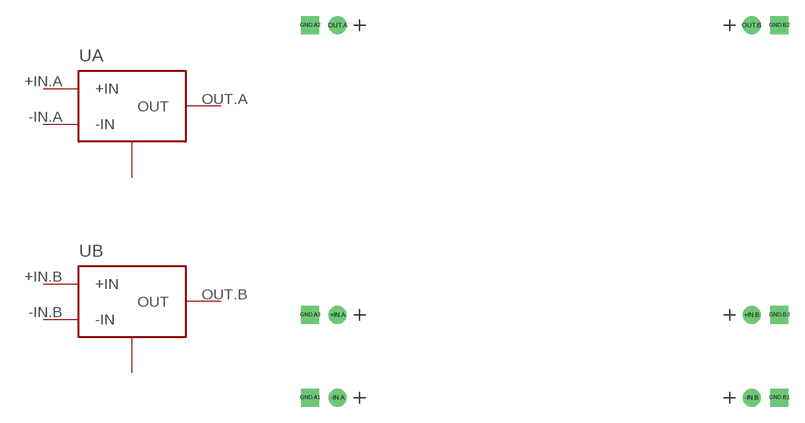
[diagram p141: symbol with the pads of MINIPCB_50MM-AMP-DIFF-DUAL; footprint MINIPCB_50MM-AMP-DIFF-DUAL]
Designator prefix -; gates A=MINIPCB_SYM-AMP-DIFF B=MINIPCB_SYM-AMP-DIFF

## MINIPCB_AMP-DIFF-DUAL50  [MINIPCB_50MM-AMP-DIFF-DUAL]
+IN.A  A:+IN
+IN.B  B:+IN
-IN.A  A:-IN
-IN.B  B:-IN
GND.A1  A:GND
GND.A2  A:GND
GND.A3  A:GND
GND.B1  B:GND
GND.B2  B:GND
GND.B3  B:GND
OUT.A  A:OUT
OUT.B  B:OUT

## Footprint MINIPCB_50MM-AMP-DIFF-DUAL (pad centres in mm)
drill 1.1: +IN.A -19.05,-9.525; +IN.B 19.05,-9.525; -IN.A -19.05,-17.145; -IN.B 19.05,-17.145; OUT.A -19.05,17.145; OUT.B 19.05,17.145
drill 1.1 square: GND.A1 -21.59,-17.145; GND.A2 -21.59,17.145; GND.A3 -21.59,-9.525; GND.B1 21.59,-17.145; GND.B2 21.59,17.145; GND.B3 21.59,-9.525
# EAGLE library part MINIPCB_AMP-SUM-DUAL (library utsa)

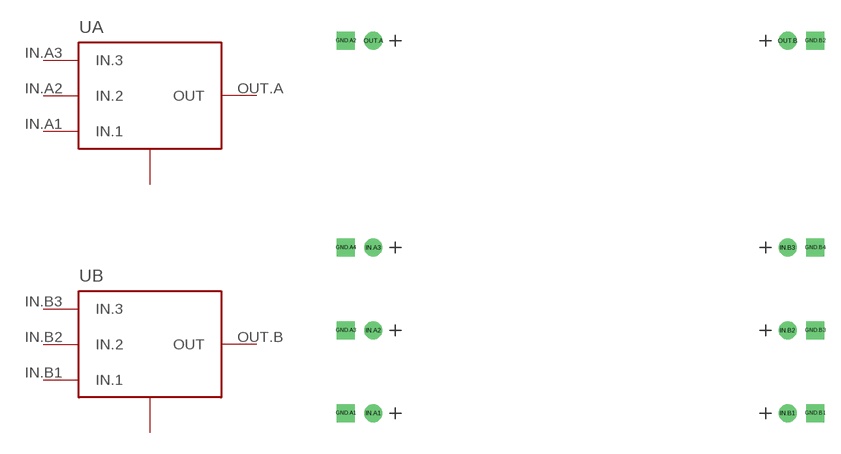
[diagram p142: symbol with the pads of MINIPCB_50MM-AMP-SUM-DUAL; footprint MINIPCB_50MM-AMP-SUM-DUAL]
Designator prefix -; gates A=MINIPCB_SYM-AMP-SUM B=MINIPCB_SYM-AMP-SUM

## MINIPCB_AMP-SUM-DUAL50  [MINIPCB_50MM-AMP-SUM-DUAL]
GND.A1  A:GND
GND.A2  A:GND
GND.A3  A:GND
GND.A4  A:GND
GND.B1  B:GND
GND.B2  B:GND
GND.B3  B:GND
GND.B4  B:GND
IN.A1  A:IN.1
IN.A2  A:IN.2
IN.A3  A:IN.3
IN.B1  B:IN.1
IN.B2  B:IN.2
IN.B3  B:IN.3
OUT.A  A:OUT
OUT.B  B:OUT

## Footprint MINIPCB_50MM-AMP-SUM-DUAL (pad centres in mm)
drill 1.1 square: GND.A1 -21.59,-17.145; GND.A2 -21.59,17.145; GND.A3 -21.59,-9.525; GND.A4 -21.59,-1.905; GND.B1 21.59,-17.145; GND.B2 21.59,17.145; GND.B3 21.59,-9.525; GND.B4 21.59,-1.905
drill 1.1: IN.A1 -19.05,-17.145; IN.A2 -19.05,-9.525; IN.A3 -19.05,-1.905; IN.B1 19.05,-17.145; IN.B2 19.05,-9.525; IN.B3 19.05,-1.905; OUT.A -19.05,17.145; OUT.B 19.05,17.145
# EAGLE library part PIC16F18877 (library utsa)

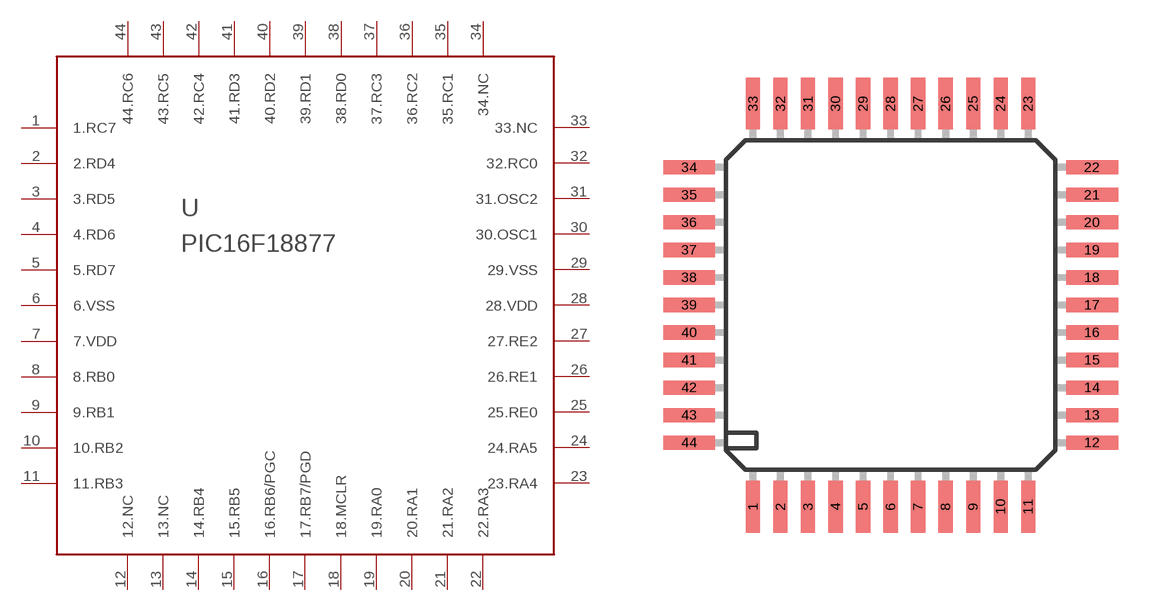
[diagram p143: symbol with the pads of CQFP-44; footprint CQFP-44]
Designator prefix -

## PIC16F18877PT  [CQFP-44]
1  1.RC7
2  2.RD4
3  3.RD5
4  4.RD6
5  5.RD7
6  6.VSS
7  7.VDD
8  8.RB0
9  9.RB1
10  10.RB2
11  11.RB3
12  12.NC
13  13.NC
14  14.RB4
15  15.RB5
16  16.RB6/PGC
17  17.RB7/PGD
18  18.MCLR
19  19.RA0
20  20.RA1
21  21.RA2
22  22.RA3
23  23.RA4
24  24.RA5
25  25.RE0
26  26.RE1
27  27.RE2
28  28.VDD
29  29.VSS
30  30.OSC1
31  31.OSC2
32  32.RC0
33  33.NC
34  34.NC
35  35.RC1
36  36.RC2
37  37.RC3
38  38.RD0
39  39.RD1
40  40.RD2
41  41.RD3
42  42.RC4
43  43.RC5
44  44.RC6

## Footprint CQFP-44 (pad centres in mm)
CERAMIC QUAD FLAT PACK
smd 0.65 x 2.4: 1 -6.35,-9.3; 2 -5.08,-9.3; 3 -3.81,-9.3; 4 -2.54,-9.3; 5 -1.27,-9.3; 6 0,-9.3; 7 1.27,-9.3; 8 2.54,-9.3; 9 3.81,-9.3; 10 5.08,-9.3; 11 6.35,-9.3; 23 6.35,9.3; 24 5.08,9.3; 25 3.81,9.3; 26 2.54,9.3; 27 1.27,9.3; 28 0,9.3; 29 -1.27,9.3; 30 -2.54,9.3; 31 -3.81,9.3; 32 -5.08,9.3; 33 -6.35,9.3
smd 2.4 x 0.65: 12 9.3,-6.35; 13 9.3,-5.08; 14 9.3,-3.81; 15 9.3,-2.54; 16 9.3,-1.27; 17 9.3,0; 18 9.3,1.27; 19 9.3,2.54; 20 9.3,3.81; 21 9.3,5.08; 22 9.3,6.35; 34 -9.3,6.35; 35 -9.3,5.08; 36 -9.3,3.81; 37 -9.3,2.54; 38 -9.3,1.27; 39 -9.3,0; 40 -9.3,-1.27; 41 -9.3,-2.54; 42 -9.3,-3.81; 43 -9.3,-5.08; 44 -9.3,-6.35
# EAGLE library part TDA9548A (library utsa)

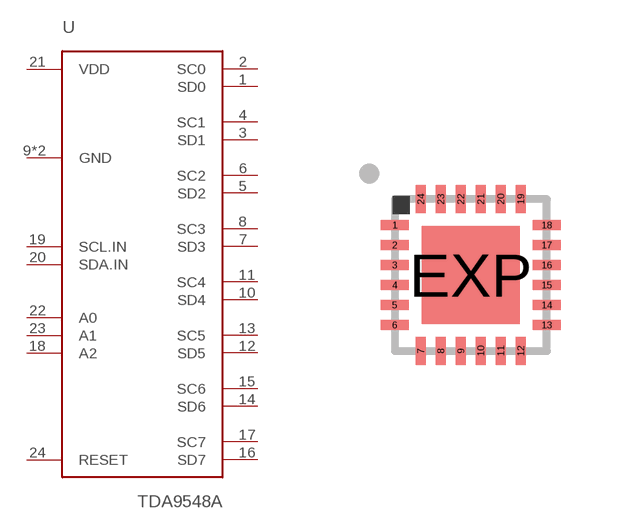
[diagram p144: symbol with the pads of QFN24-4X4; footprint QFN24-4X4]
Designator prefix U

## TDA9548A-RGE  [QFN24-4X4]
1  SD0
2  SC0
3  SD1
4  SC1
5  SD2
6  SC2
7  SD3
8  SC3
9  GND
10  SD4
11  SC4
12  SD5
13  SC5
14  SD6
15  SC6
16  SD7
17  SC7
18  A2
19  SCL.IN
20  SDA.IN
21  VDD
22  A0
23  A1
24  RESET
EXP  GND

## Footprint QFN24-4X4 (pad centres in mm)
UF Package 24-Lead (4mm × 4mm) Plastic QFN Source: http://cds.linear.com/docs/Datasheet/5598f.pdf
smd 0.7 x 0.25: 1 -1.9,1.25; 2 -1.9,0.75; 3 -1.9,0.25; 4 -1.9,-0.25; 5 -1.9,-0.75; 6 -1.9,-1.25; 13 1.9,-1.25; 14 1.9,-0.75; 15 1.9,-0.25; 16 1.9,0.25; 17 1.9,0.75; 18 1.9,1.25
smd 0.25 x 0.7: 7 -1.25,-1.9; 8 -0.75,-1.9; 9 -0.25,-1.9; 10 0.25,-1.9; 11 0.75,-1.9; 12 1.25,-1.9; 19 1.25,1.9; 20 0.75,1.9; 21 0.25,1.9; 22 -0.25,1.9; 23 -0.75,1.9; 24 -1.25,1.9
smd 2.45 x 2.45: EXP 0,0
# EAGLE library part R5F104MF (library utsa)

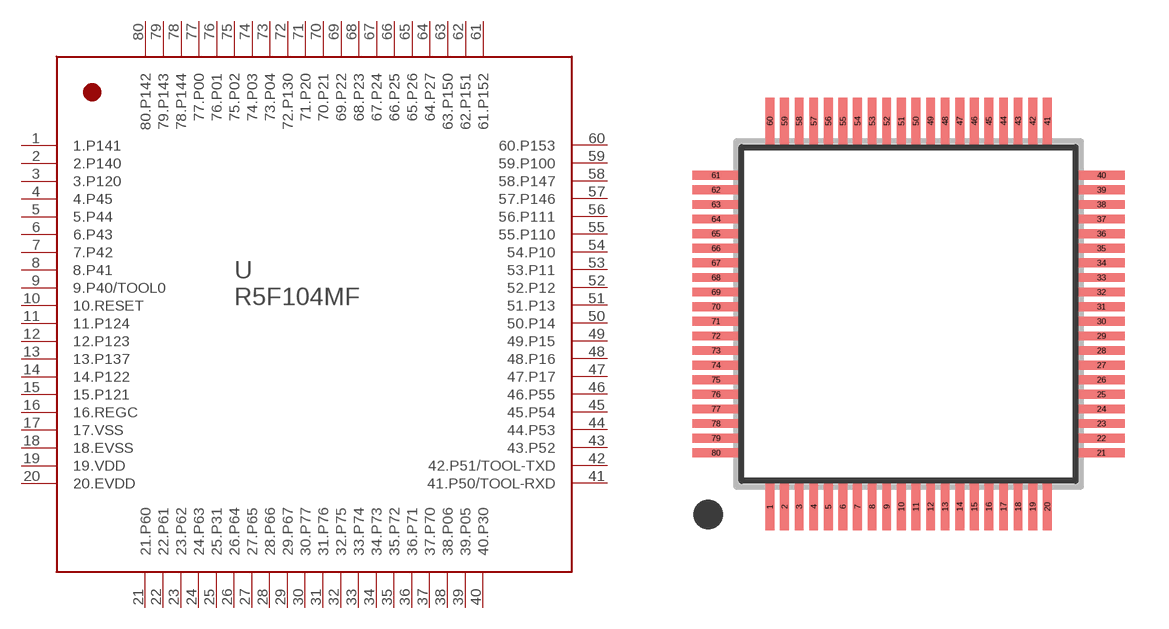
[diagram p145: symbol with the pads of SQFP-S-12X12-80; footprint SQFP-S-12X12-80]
Designator prefix U

## R5F104MF  [SQFP-S-12X12-80]
1  1.P141
2  2.P140
3  3.P120
4  4.P45
5  5.P44
6  6.P43
7  7.P42
8  8.P41
9  9.P40/TOOL0
10  10.RESET
11  11.P124
12  12.P123
13  13.P137
14  14.P122
15  15.P121
16  16.REGC
17  17.VSS
18  18.EVSS
19  19.VDD
20  20.EVDD
21  21.P60
22  22.P61
23  23.P62
24  24.P63
25  25.P31
26  26.P64
27  27.P65
28  28.P66
29  29.P67
30  30.P77
31  31.P76
32  32.P75
33  33.P74
34  34.P73
35  35.P72
36  36.P71
37  37.P70
38  38.P06
39  39.P05
40  40.P30
41  41.P50/TOOL-RXD
42  42.P51/TOOL-TXD
43  43.P52
44  44.P53
45  45.P54
46  46.P55
47  47.P17
48  48.P16
49  49.P15
50  50.P14
51  51.P13
52  52.P12
53  53.P11
54  54.P10
55  55.P110
56  56.P111
57  57.P146
58  58.P147
59  59.P100
60  60.P153
61  61.P152
62  62.P151
63  63.P150
64  64.P27
65  65.P26
66  66.P25
67  67.P24
68  68.P23
69  69.P22
70  70.P21
71  71.P20
72  72.P130
73  73.P04
74  74.P03
75  75.P02
76  76.P01
77  77.P00
78  78.P144
79  79.P143
80  80.P142

## Footprint SQFP-S-12X12-80 (pad centres in mm)
QFP80 shrink quad flat pack, square
smd 0.3 x 1.6: 1 -4.75,-6.6; 2 -4.25,-6.6; 3 -3.75,-6.6; 4 -3.25,-6.6; 5 -2.75,-6.6; 6 -2.25,-6.6; 7 -1.75,-6.6; 8 -1.25,-6.6; 9 -0.75,-6.6; 10 -0.25,-6.6; 11 0.25,-6.6; 12 0.75,-6.6; 13 1.25,-6.6; 14 1.75,-6.6; 15 2.25,-6.6; 16 2.75,-6.6; 17 3.25,-6.6; 18 3.75,-6.6; 19 4.25,-6.6; 20 4.75,-6.6; 41 4.75,6.6; 42 4.25,6.6; 43 3.75,6.6; 44 3.25,6.6; 45 2.75,6.6; 46 2.25,6.6; 47 1.75,6.6; 48 1.25,6.6; 49 0.75,6.6; 50 0.25,6.6; 51 -0.25,6.6; 52 -0.75,6.6; 53 -1.25,6.6; 54 -1.75,6.6; 55 -2.25,6.6; 56 -2.75,6.6; 57 -3.25,6.6; 58 -3.75,6.6; 59 -4.25,6.6; 60 -4.75,6.6
smd 1.6 x 0.3: 21 6.6,-4.75; 22 6.6,-4.25; 23 6.6,-3.75; 24 6.6,-3.25; 25 6.6,-2.75; 26 6.6,-2.25; 27 6.6,-1.75; 28 6.6,-1.25; 29 6.6,-0.75; 30 6.6,-0.25; 31 6.6,0.25; 32 6.6,0.75; 33 6.6,1.25; 34 6.6,1.75; 35 6.6,2.25; 36 6.6,2.75; 37 6.6,3.25; 38 6.6,3.75; 39 6.6,4.25; 40 6.6,4.75; 61 -6.6,4.75; 62 -6.6,4.25; 63 -6.6,3.75; 64 -6.6,3.25; 65 -6.6,2.75; 66 -6.6,2.25; 67 -6.6,1.75; 68 -6.6,1.25; 69 -6.6,0.75; 70 -6.6,0.25; 71 -6.6,-0.25; 72 -6.6,-0.75; 73 -6.6,-1.25; 74 -6.6,-1.75; 75 -6.6,-2.25; 76 -6.6,-2.75; 77 -6.6,-3.25; 78 -6.6,-3.75; 79 -6.6,-4.25; 80 -6.6,-4.75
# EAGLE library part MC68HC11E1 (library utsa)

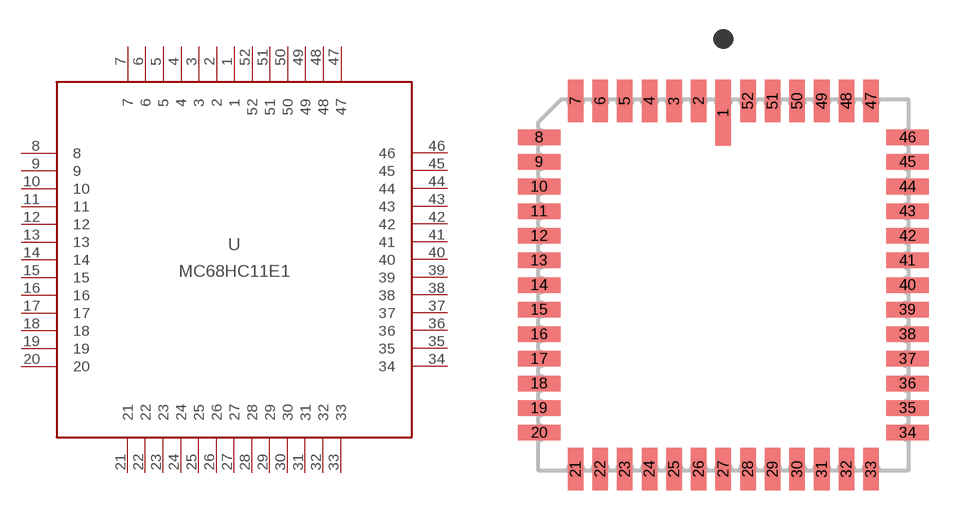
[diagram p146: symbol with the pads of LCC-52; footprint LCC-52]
Designator prefix U

## MC68HC11E1  [LCC-52]
1  1
2  2
3  3
4  4
5  5
6  6
7  7
8  8
9  9
10  10
11  11
12  12
13  13
14  14
15  15
16  16
17  17
18  18
19  19
20  20
21  21
22  22
23  23
24  24
25  25
26  26
27  27
28  28
29  29
30  30
31  31
32  32
33  33
34  34
35  35
36  36
37  37
38  38
39  39
40  40
41  41
42  42
43  43
44  44
45  45
46  46
47  47
48  48
49  49
50  50
51  51
52  52

## Footprint LCC-52 (pad centres in mm)
LEADLESS CERAMIC CHIP CARRIER
smd 0.8 x 3.4: 1 0,8.9
smd 0.8 x 2.2: 2 -1.27,9.5; 3 -2.54,9.5; 4 -3.81,9.5; 5 -5.08,9.5; 6 -6.35,9.5; 7 -7.62,9.5; 21 -7.62,-9.5; 22 -6.35,-9.5; 23 -5.08,-9.5; 24 -3.81,-9.5; 25 -2.54,-9.5; 26 -1.27,-9.5; 27 0,-9.5; 28 1.27,-9.5; 29 2.54,-9.5; 30 3.81,-9.5; 31 5.08,-9.5; 32 6.35,-9.5; 33 7.62,-9.5; 47 7.62,9.5; 48 6.35,9.5; 49 5.08,9.5; 50 3.81,9.5; 51 2.54,9.5; 52 1.27,9.5
smd 2.2 x 0.8: 8 -9.5,7.62; 9 -9.5,6.35; 10 -9.5,5.08; 11 -9.5,3.81; 12 -9.5,2.54; 13 -9.5,1.27; 14 -9.5,0; 15 -9.5,-1.27; 16 -9.5,-2.54; 17 -9.5,-3.81; 18 -9.5,-5.08; 19 -9.5,-6.35; 20 -9.5,-7.62; 34 9.5,-7.62; 35 9.5,-6.35; 36 9.5,-5.08; 37 9.5,-3.81; 38 9.5,-2.54; 39 9.5,-1.27; 40 9.5,0; 41 9.5,1.27; 42 9.5,2.54; 43 9.5,3.81; 44 9.5,5.08; 45 9.5,6.35; 46 9.5,7.62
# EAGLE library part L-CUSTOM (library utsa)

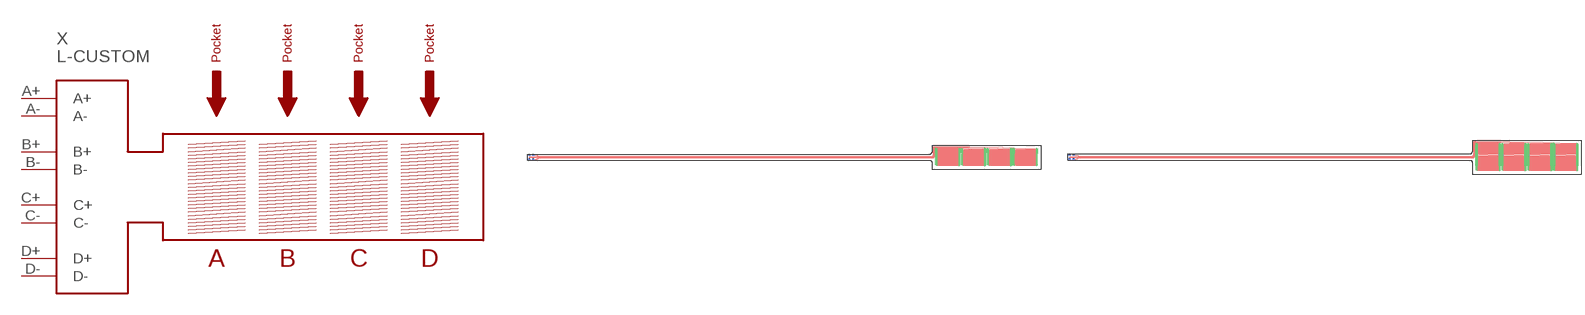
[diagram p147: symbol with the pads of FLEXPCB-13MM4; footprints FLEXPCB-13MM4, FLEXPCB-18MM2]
Designator prefix X

## L-CUSTOM12.0-200MM  [FLEXPCB-13MM4]
A+  A+  pas
A-  A-  pas
B+  B+  pas
B-  B-  pas
C+  C+  pas
C-  C-  pas
D+  D+  pas
D-  D-  pas

## L-CUSTOM16.8-200MM  [FLEXPCB-18MM2]
Pads as for FLEXPCB-13MM4

## L-CUSTOM21.6-200MM  [FLEXPCB-23MM0]
Pads as for FLEXPCB-13MM4

## L-CUSTOM12.0-20MM  [FLEXPCB-13MM4-SHORT]
Pads as for FLEXPCB-13MM4

## L-CUSTOM16.8-20MM  [FLEXPCB-18MM2-SHORT]
Pads as for FLEXPCB-13MM4

## L-CUSTOM21.6-20MM  [FLEXPCB-23MM0-SHORT]
Pads as for FLEXPCB-13MM4

## L-CUSTOM12.0-100MM  [FLEXPCB-13MM4-100]
Pads as for FLEXPCB-13MM4

## L-CUSTOM16.8-100MM  [FLEXPCB-18MM2-100]
Pads as for FLEXPCB-13MM4

## L-CUSTOM21.6-100MM  [FLEXPCB-23MM0-100]
Pads as for FLEXPCB-13MM4

## L-CUSTOM12.0-0MM  [FLEXPCB-13MM4-0]
Pads as for FLEXPCB-13MM4

## L-CUSTOM16.8-0MM  [FLEXPCB-18MM2-0]
Pads as for FLEXPCB-13MM4

## L-CUSTOM21.6-0MM  [FLEXPCB-23MM0-0]
Pads as for FLEXPCB-13MM4

## Footprint FLEXPCB-13MM4 (pad centres in mm)
drill 0.11 pad 0.2: 1 201.9,4.25; 2 202.4,4; 3 201.9,3.75; 4 202.4,3.5; 5 201.9,3.25; 6 202.4,3; 7 201.9,2.75; 8 202.4,2.5; 9 201.9,2.25; 10 202.4,2; 11 201.9,1.75; 12 202.4,1.5; 13 201.9,1.25; 14 202.4,1; 15 201.9,0.75; 16 202.4,0.5; 17 201.9,0.25; 18 202.4,0; 19 201.9,-0.25; 20 202.4,-0.5; 21 201.9,-0.75; 22 202.4,-1; 23 201.9,-1.25; 24 202.4,-1.5; 25 201.9,-1.75; 26 202.4,-2; 27 201.9,-2.25; 28 202.4,-2.5; 29 201.9,-2.75; 30 202.4,-3; 31 201.9,-3.25; 32 202.4,-3.5; 33 201.9,-3.75; 34 202.4,-4; 35 215.2,4; 36 215.2,3.5; 37 215.2,3; 38 215.2,2.5; 39 215.2,2; 40 215.2,1.5; 41 215.2,1; 42 215.2,0.5; 43 215.2,0; 44 215.2,-0.5; 45 215.2,-1; 46 215.2,-1.5; 47 215.2,-2; 48 215.2,-2.5; 49 215.2,-3; 50 215.2,-3.5; 51 215.2,-4; 52 214.7,4.25; 53 214.7,3.75; 54 214.7,3.25; 55 214.7,2.75; 56 214.7,2.25; 57 214.7,1.75; 58 214.7,1.25; 59 214.7,0.75; 60 214.7,0.25; 61 214.7,-0.25; 62 214.7,-0.75; 63 214.7,-1.25; 64 214.7,-1.75; 65 214.7,-2.25; 66 214.7,-2.75; 67 214.7,-3.25; 68 214.7,-3.75; 69 228,4; 70 228,3.5; 71 228,3; 72 228,2.5; 73 228,2; 74 228,1.5; 75 228,1; 76 228,0.5; 77 228,0; 78 228,-0.5; 79 228,-1; 80 228,-1.5; 81 228,-2; 82 228,-2.5; 83 228,-3; 84 228,-3.5; 85 228,-4; 86 227.5,4.25; 87 227.5,3.75; 88 227.5,3.25; 89 227.5,2.75; 90 227.5,2.25; 91 227.5,1.75; 92 227.5,1.25; 93 227.5,0.75; 94 227.5,0.25; 95 227.5,-0.25; 96 227.5,-0.75; 97 227.5,-1.25; 98 227.5,-1.75; 99 227.5,-2.25; 100 227.5,-2.75; 101 227.5,-3.25; 102 227.5,-3.75; 103 240.8,4; 104 240.8,3.5; 105 240.8,3; 106 240.8,2.5; 107 240.8,2; 108 240.8,1.5; 109 240.8,1; 110 240.8,0.5; 111 240.8,0; 112 240.8,-0.5; 113 240.8,-1; 114 240.8,-1.5; 115 240.8,-2; 116 240.8,-2.5; 117 240.8,-3; 118 240.8,-3.5; 119 240.8,-4; 120 240.3,4.25; 121 240.3,3.75; 122 240.3,3.25; 123 240.3,2.75; 124 240.3,2.25; 125 240.3,1.75; 126 240.3,1.25; 127 240.3,0.75; 128 240.3,0.25; 129 240.3,-0.25; 130 240.3,-0.75; 131 240.3,-1.25; 132 240.3,-1.75; 133 240.3,-2.25; 134 240.3,-2.75; 135 240.3,-3.25; 136 240.3,-3.75; IN 213.4,4.25; IN1 226.2,4.25; IN2 239,4.25; IN3 251.8,4.25; P$1 226.7,4; P$2 226.7,3.5; P$3 226.7,3; P$4 226.7,2.5; P$5 226.7,2; P$6 226.7,1.5; P$7 226.7,1; P$8 226.7,0.5; P$9 226.7,0; P$10 226.7,-0.5; P$11 226.7,-1; P$12 226.7,-1.5; P$13 226.7,-2; P$14 226.7,-2.5; P$15 226.7,-3; P$16 226.7,-3.5; P$17 226.7,-4; P$18 226.2,3.75; P$19 226.2,3.25; P$20 226.2,2.75; P$21 226.2,2.25; P$22 226.2,1.75; P$23 226.2,1.25; P$24 226.2,0.75; P$25 226.2,0.25; P$26 226.2,-0.25; P$27 226.2,-0.75; P$28 226.2,-1.25; P$29 226.2,-1.75; P$30 226.2,-2.25; P$31 226.2,-2.75; P$32 226.2,-3.25; P$33 226.2,-3.75; P$34 226.2,-4.25; P$35 239.5,4; P$36 239.5,3.5; P$37 239.5,3; P$38 239.5,2.5; P$39 239.5,2; P$40 239.5,1.5; P$41 239.5,1; P$42 239.5,0.5; P$43 239.5,0; P$44 239.5,-0.5; P$45 239.5,-1; P$46 239.5,-1.5; P$47 239.5,-2; P$48 239.5,-2.5; P$49 213.9,4; P$50 213.9,3.5; P$51 213.9,3; P$52 213.9,2.5; P$53 213.9,2; P$54 213.9,1.5; P$55 213.9,1; P$56 213.9,0.5; P$57 213.9,0; P$58 213.9,-0.5; P$59 213.9,-1; P$60 213.9,-1.5; P$61 213.9,-2; P$62 213.9,-2.5; P$63 213.9,-3; P$64 213.9,-3.5; P$65 213.9,-4; P$66 239.5,-3; P$67 239.5,-3.5; P$68 239.5,-4; P$69 239,3.75; P$70 239,3.25; P$71 239,2.75; P$72 213.4,3.75; P$73 213.4,3.25; P$74 213.4,2.75; P$75 213.4,2.25; P$76 213.4,1.75; P$77 213.4,1.25; P$78 213.4,0.75; P$79 213.4,0.25; P$80 213.4,-0.25; P$81 213.4,-0.75; P$82 213.4,-1.25; P$83 213.4,-1.75; P$84 213.4,-2.25; P$85 213.4,-2.75; P$86 213.4,-3.25; P$87 213.4,-3.75; P$88 213.4,-4.25; P$89 239,2.25; P$90 239,1.75; P$91 239,1.25; P$92 239,0.75; P$93 239,0.25; P$94 239,-0.25; P$95 239,-0.75; P$96 239,-1.25; P$97 239,-1.75; P$98 239,-2.25; P$99 239,-2.75; P$100 239,-3.25; P$101 239,-3.75; P$102 239,-4.25; P$103 252.3,4; P$104 252.3,3.5; P$105 252.3,3; P$106 252.3,2.5; P$107 252.3,2; P$108 252.3,1.5; P$109 252.3,1; P$110 252.3,0.5; P$111 252.3,0; P$112 252.3,-0.5; P$113 252.3,-1; P$114 252.3,-1.5; P$115 252.3,-2; P$116 252.3,-2.5; P$117 252.3,-3; P$118 252.3,-3.5; P$119 252.3,-4; P$120 251.8,3.75; P$121 251.8,3.25; P$122 251.8,2.75; P$123 251.8,2.25; P$124 251.8,1.75; P$125 251.8,1.25; P$126 251.8,0.75; P$127 251.8,0.25; P$128 251.8,-0.25; P$129 251.8,-0.75; P$130 251.8,-1.25; P$131 251.8,-1.75; P$132 251.8,-2.25; P$133 251.8,-2.75; P$134 251.8,-3.25; P$135 251.8,-3.75; P$136 251.8,-4.25
smd 1.27 x 0.635: A+ 3,-1; B+ 1,-1; C+ 1,1; D+ 3,1
smd 1.27 x 0.635 bottom: A- 3,1; B- 1,1; C- 1,-1; D- 3,-1

## Footprint FLEXPCB-18MM2 (pad centres in mm)
drill 0.11 pad 0.2: 1 201.9,6.75; 2 202.4,6.5; 3 201.9,3.75; 4 202.4,3.5; 5 201.9,3.25; 6 202.4,3; 7 201.9,2.75; 8 202.4,2.5; 9 201.9,2.25; 10 202.4,2; 11 201.9,1.75; 12 202.4,1.5; 13 201.9,1.25; 14 202.4,1; 15 201.9,0.75; 16 202.4,0.5; 17 201.9,0.25; 18 202.4,0; 19 201.9,-0.25; 20 202.4,-0.5; 21 201.9,-0.75; 22 202.4,-1; 23 201.9,-1.25; 24 202.4,-1.5; 25 201.9,-1.75; 26 202.4,-2; 27 201.9,-2.25; 28 202.4,-2.5; 29 201.9,-2.75; 30 202.4,-3; 31 201.9,-3.25; 32 202.4,-6; 33 201.9,-6.25; 34 202.4,-6.5; 35 215.2,6.5; 36 215.2,3.5; 37 215.2,3; 38 215.2,2.5; 39 215.2,2; 40 215.2,1.5; 41 215.2,1; 42 215.2,0.5; 43 215.2,0; 44 215.2,-0.5; 45 215.2,-1; 46 215.2,-1.5; 47 215.2,-2; 48 215.2,-2.5; 49 215.2,-3; 50 215.2,-6; 51 215.2,-6.5; 52 214.7,6.75; 53 214.7,3.75; 54 214.7,3.25; 55 214.7,2.75; 56 214.7,2.25; 57 214.7,1.75; 58 214.7,1.25; 59 214.7,0.75; 60 214.7,0.25; 61 214.7,-0.25; 62 214.7,-0.75; 63 214.7,-1.25; 64 214.7,-1.75; 65 214.7,-2.25; 66 214.7,-2.75; 67 214.7,-3.25; 68 214.7,-6.25; 69 228,6.5; 70 228,3.5; 71 228,3; 72 228,2.5; 73 228,2; 74 228,1.5; 75 228,1; 76 228,0.5; 77 228,0; 78 228,-0.5; 79 228,-1; 80 228,-1.5; 81 228,-2; 82 228,-2.5; 83 228,-3; 84 228,-6; 85 228,-6.5; 86 227.5,6.75; 87 227.5,3.75; 88 227.5,3.25; 89 227.5,2.75; 90 227.5,2.25; 91 227.5,1.75; 92 227.5,1.25; 93 227.5,0.75; 94 227.5,0.25; 95 227.5,-0.25; 96 227.5,-0.75; 97 227.5,-1.25; 98 227.5,-1.75; 99 227.5,-2.25; 100 227.5,-2.75; 101 227.5,-3.25; 102 227.5,-6.25; 103 240.8,6.5; 104 240.8,3.5; 105 240.8,3; 106 240.8,2.5; 107 240.8,2; 108 240.8,1.5; 109 240.8,1; 110 240.8,0.5; 111 240.8,0; 112 240.8,-0.5; 113 240.8,-1; 114 240.8,-1.5; 115 240.8,-2; 116 240.8,-2.5; 117 240.8,-3; 118 240.8,-6; 119 240.8,-6.5; 120 240.3,6.75; 121 240.3,3.75; 122 240.3,3.25; 123 240.3,2.75; 124 240.3,2.25; 125 240.3,1.75; 126 240.3,1.25; 127 240.3,0.75; 128 240.3,0.25; 129 240.3,-0.25; 130 240.3,-0.75; 131 240.3,-1.25; 132 240.3,-1.75; 133 240.3,-2.25; 134 240.3,-2.75; 135 240.3,-3.25; 136 240.3,-6.25; 137 202.4,4; 138 201.9,4.25; 139 202.4,4.5; 140 201.9,4.75; 141 202.4,5; 142 201.9,5.25; 143 202.4,5.5; 144 201.9,5.75; 145 202.4,6; 146 201.9,6.25; 147 215.2,4; 148 214.7,4.25; 149 215.2,4.5; 150 214.7,4.75; 151 215.2,5; 152 214.7,5.25; 153 215.2,5.5; 154 214.7,5.75; 155 215.2,6; 156 214.7,6.25; 157 228,4; 158 227.5,4.25; 159 228,4.5; 160 227.5,4.75; 161 228,5; 162 227.5,5.25; 163 228,5.5; 164 227.5,5.75; 165 228,6; 166 227.5,6.25; 167 240.8,4; 168 240.3,4.25; 169 240.8,4.5; 170 240.3,4.75; 171 240.8,5; 172 240.3,5.25; 173 240.8,5.5; 174 240.3,5.75; 175 240.8,6; 176 240.3,6.25; 177 202.4,-4; 178 202.4,-4.5; 179 202.4,-5; 180 202.4,-5.5; 181 201.9,-3.75; 182 201.9,-4.25; 183 201.9,-4.75; 184 201.9,-5.25; 185 201.9,-5.75; 186 215.2,-4; 187 215.2,-4.5; 188 215.2,-5; 189 215.2,-5.5; 190 214.7,-3.75; 191 214.7,-4.25; 192 214.7,-4.75; 193 214.7,-5.25; 194 214.7,-5.75; 195 228,-4; 196 228,-4.5; 197 228,-5; 198 228,-5.5; 199 227.5,-3.75; 200 227.5,-4.25; 201 227.5,-4.75; 202 227.5,-5.25; 203 227.5,-5.75; 204 240.8,-4; 205 240.8,-4.5; 206 240.8,-5; 207 240.8,-5.5; 208 240.3,-3.75; 209 240.3,-4.25; 210 240.3,-4.75; 211 240.3,-5.25; 212 240.3,-5.75; 213 202.4,-3.5; 214 215.2,-3.5; 215 228,-3.5; 216 240.8,-3.5; IN 213.4,6.75; IN1 226.2,6.75; IN2 239,6.75; IN3 251.8,6.75; P$1 226.7,6.5; P$2 226.7,3.5; P$3 226.7,3; P$4 226.7,2.5; P$5 226.7,2; P$6 226.7,1.5; P$7 226.7,1; P$8 226.7,0.5; P$9 226.7,0; P$10 226.7,-0.5; P$11 226.7,-1; P$12 226.7,-1.5; P$13 226.7,-2; P$14 226.7,-2.5; P$15 226.7,-3; P$16 226.7,-6; P$17 226.7,-6.5; P$18 226.2,3.75; P$19 226.2,3.25; P$20 226.2,2.75; P$21 226.2,2.25; P$22 226.2,1.75; P$23 226.2,1.25; P$24 226.2,0.75; P$25 226.2,0.25; P$26 226.2,-0.25; P$27 226.2,-0.75; P$28 226.2,-1.25; P$29 226.2,-1.75; P$30 226.2,-2.25; P$31 226.2,-2.75; P$32 226.2,-3.25; P$33 226.2,-6.25; P$34 226.2,-6.75; P$35 239.5,6.5; P$36 239.5,3.5; P$37 239.5,3; P$38 239.5,2.5; P$39 239.5,2; P$40 239.5,1.5; P$41 239.5,1; P$42 239.5,0.5; P$43 239.5,0; P$44 239.5,-0.5; P$45 239.5,-1; P$46 239.5,-1.5; P$47 239.5,-2; P$48 239.5,-2.5; P$49 213.9,6.5; P$50 213.9,3.5; P$51 213.9,3; P$52 213.9,2.5; P$53 213.9,2; P$54 213.9,1.5; P$55 213.9,1; P$56 213.9,0.5; P$57 213.9,0; P$58 213.9,-0.5; P$59 213.9,-1; P$60 213.9,-1.5; P$61 213.9,-2; P$62 213.9,-2.5; P$63 213.9,-3; P$64 213.9,-6; P$65 213.9,-6.5; P$66 239.5,-3; P$67 239.5,-6; P$68 239.5,-6.5; P$69 239,3.75; P$70 239,3.25; P$71 239,2.75; P$72 213.4,3.75; P$73 213.4,3.25; P$74 213.4,2.75; P$75 213.4,2.25; P$76 213.4,1.75; P$77 213.4,1.25; P$78 213.4,0.75; P$79 213.4,0.25; P$80 213.4,-0.25; P$81 213.4,-0.75; P$82 213.4,-1.25; P$83 213.4,-1.75; P$84 213.4,-2.25; P$85 213.4,-2.75; P$86 213.4,-3.25; P$87 213.4,-6.25; P$88 213.4,-6.75; P$89 239,2.25; P$90 239,1.75; P$91 239,1.25; P$92 239,0.75; P$93 239,0.25; P$94 239,-0.25; P$95 239,-0.75; P$96 239,-1.25; P$97 239,-1.75; P$98 239,-2.25; P$99 239,-2.75; P$100 239,-3.25; P$101 239,-6.25; P$102 239,-6.75; P$103 252.3,6.5; P$104 252.3,3.5; P$105 252.3,3; P$106 252.3,2.5; P$107 252.3,2; P$108 252.3,1.5; P$109 252.3,1; P$110 252.3,0.5; P$111 252.3,0; P$112 252.3,-0.5; P$113 252.3,-1; P$114 252.3,-1.5; P$115 252.3,-2; P$116 252.3,-2.5; P$117 252.3,-3; P$118 252.3,-6; P$119 252.3,-6.5; P$120 251.8,3.75; P$121 251.8,3.25; P$122 251.8,2.75; P$123 251.8,2.25; P$124 251.8,1.75; P$125 251.8,1.25; P$126 251.8,0.75; P$127 251.8,0.25; P$128 251.8,-0.25; P$129 251.8,-0.75; P$130 251.8,-1.25; P$131 251.8,-1.75; P$132 251.8,-2.25; P$133 251.8,-2.75; P$134 251.8,-3.25; P$135 251.8,-6.25; P$136 251.8,-6.75; P$137 213.4,4.25; P$138 213.4,4.75; P$139 213.4,5.25; P$140 213.4,5.75; P$141 213.4,6.25; P$142 213.9,6; P$143 213.9,5.5; P$144 213.9,5; P$145 213.9,4.5; P$146 213.9,4; P$147 226.2,4.25; P$148 226.2,4.75; P$149 226.2,5.25; P$150 226.2,5.75; P$151 226.2,6.25; P$152 226.7,6; P$153 226.7,5.5; P$154 226.7,5; P$155 226.7,4.5; P$156 226.7,4; P$157 239,4.25; P$158 239,4.75; P$159 239,5.25; P$160 239,5.75; P$161 239,6.25; P$162 239.5,6; P$163 239.5,5.5; P$164 239.5,5; P$165 239.5,4.5; P$166 239.5,4; P$167 251.8,4.25; P$168 251.8,4.75; P$169 251.8,5.25; P$170 251.8,5.75; P$171 251.8,6.25; P$172 252.3,6; P$173 252.3,5.5; P$174 252.3,5; P$175 252.3,4.5; P$176 252.3,4; P$177 213.9,-4; P$178 213.9,-4.5; P$179 213.9,-5; P$180 213.9,-5.5; P$181 213.4,-3.75; P$182 213.4,-4.25; P$183 213.4,-4.75; P$184 213.4,-5.25; P$185 213.4,-5.75; P$186 226.7,-4; P$187 226.7,-4.5; P$188 226.7,-5; P$189 226.7,-5.5; P$190 226.2,-3.75; P$191 226.2,-4.25; P$192 226.2,-4.75; P$193 226.2,-5.25; P$194 226.2,-5.75; P$195 239.5,-4; P$196 239.5,-4.5; P$197 239.5,-5; P$198 239.5,-5.5; P$199 239,-3.75; P$200 239,-4.25; P$201 239,-4.75; P$202 239,-5.25; P$203 239,-5.75; P$204 252.3,-4; P$205 252.3,-4.5; P$206 252.3,-5; P$207 252.3,-5.5; P$208 251.8,-3.75; P$209 251.8,-4.25; P$210 251.8,-4.75; P$211 251.8,-5.25; P$212 251.8,-5.75; P$213 213.9,-3.5; P$214 226.7,-3.5; P$215 239.5,-3.5; P$216 252.3,-3.5
smd 1.27 x 0.635: A+ 3,-1; B+ 1,-1; C+ 1,1; D+ 3,1
smd 1.27 x 0.635 bottom: A- 3,1; B- 1,1; C- 1,-1; D- 3,-1

## Footprint FLEXPCB-23MM0 (pad centres in mm)
drill 0.11 pad 0.2: 1 201.9,9.25; 2 202.4,9; 3 201.9,8.75; 4 202.4,8.5; 5 201.9,8.25; 6 202.4,8; 7 201.9,7.75; 8 202.4,2.5; 9 201.9,2.25; 10 202.4,2; 11 201.9,1.75; 12 202.4,1.5; 13 201.9,1.25; 14 202.4,1; 15 201.9,0.75; 16 202.4,0.5; 17 201.9,0.25; 18 202.4,0; 19 201.9,-0.25; 20 202.4,-0.5; 21 201.9,-0.75; 22 202.4,-1; 23 201.9,-1.25; 24 202.4,-1.5; 25 201.9,-1.75; 26 202.4,-2; 27 201.9,-2.25; 28 202.4,-2.5; 29 201.9,-7.75; 30 202.4,-8; 31 201.9,-8.25; 32 202.4,-8.5; 33 201.9,-8.75; 34 202.4,-9; 35 215.2,9; 36 215.2,8.5; 37 215.2,8; 38 215.2,4; 39 214.7,4.25; 40 214.7,3.75; 41 228,4; 42 227.5,4.25; 43 227.5,3.75; 44 240.8,4; 45 240.3,4.25; 46 240.3,3.75; 47 215.2,3.5; 48 215.2,3; 49 215.2,-8; 50 215.2,-8.5; 51 215.2,-9; 52 214.7,9.25; 53 214.7,8.75; 54 214.7,8.25; 55 214.7,7.75; 56 215.2,2.5; 57 215.2,2; 58 215.2,1.5; 59 215.2,1; 60 214.7,3.25; 61 214.7,2.75; 62 214.7,2.25; 63 214.7,1.75; 64 214.7,1.25; 65 228,3.5; 66 214.7,-7.75; 67 214.7,-8.25; 68 214.7,-8.75; 69 228,9; 70 228,8.5; 71 228,8; 72 228,3; 73 228,2.5; 74 228,2; 75 228,1.5; 76 228,1; 77 227.5,3.25; 78 227.5,2.75; 79 227.5,2.25; 80 227.5,1.75; 81 227.5,1.25; 82 240.8,3.5; 83 228,-8; 84 228,-8.5; 85 228,-9; 86 227.5,9.25; 87 227.5,8.75; 88 227.5,8.25; 89 227.5,7.75; 90 240.8,3; 91 240.8,2.5; 92 240.8,2; 93 240.8,1.5; 94 240.8,1; 95 240.3,3.25; 96 240.3,2.75; 97 240.3,2.25; 98 240.3,1.75; 99 240.3,1.25; 100 227.5,-7.75; 101 227.5,-8.25; 102 227.5,-8.75; 103 240.8,9; 104 240.8,8.5; 105 240.8,8; 106 215.2,0; 107 214.7,0.25; 108 214.7,-0.25; 109 228,0; 110 227.5,0.25; 111 227.5,-0.25; 112 240.8,0; 113 240.3,0.25; 114 240.3,-0.25; 115 215.2,-0.5; 116 215.2,-1; 117 240.8,-8; 118 240.8,-8.5; 119 240.8,-9; 120 240.3,9.25; 121 240.3,8.75; 122 240.3,8.25; 123 240.3,7.75; 124 215.2,-1.5; 125 215.2,-2; 126 215.2,-2.5; 127 215.2,-3; 128 214.7,-0.75; 129 214.7,-1.25; 130 214.7,-1.75; 131 214.7,-2.25; 132 214.7,-2.75; 133 228,-0.5; 134 240.3,-7.75; 135 240.3,-8.25; 136 240.3,-8.75; 137 202.4,7.5; 138 202.4,7; 139 202.4,6.5; 140 202.4,6; 141 202.4,5.5; 142 202.4,5; 143 201.9,7.25; 144 201.9,6.75; 145 201.9,6.25; 146 201.9,5.75; 147 201.9,5.25; 148 215.2,7.5; 149 215.2,7; 150 215.2,6.5; 151 215.2,6; 152 215.2,5.5; 153 215.2,5; 154 214.7,7.25; 155 214.7,6.75; 156 214.7,6.25; 157 214.7,5.75; 158 214.7,5.25; 159 228,7.5; 160 228,7; 161 228,6.5; 162 228,6; 163 228,5.5; 164 228,5; 165 227.5,7.25; 166 227.5,6.75; 167 227.5,6.25; 168 227.5,5.75; 169 227.5,5.25; 170 240.8,7.5; 171 240.8,7; 172 240.8,6.5; 173 240.8,6; 174 240.8,5.5; 175 240.8,5; 176 240.3,7.25; 177 240.3,6.75; 178 240.3,6.25; 179 240.3,5.75; 180 240.3,5.25; 181 202.4,4.5; 182 201.9,4.75; 183 202.4,3.5; 184 201.9,3.75; 185 202.4,4; 186 201.9,4.25; 187 201.9,3.25; 188 201.9,2.75; 189 202.4,3; 190 202.4,-3; 191 202.4,-3.5; 192 202.4,-4; 193 202.4,-4.5; 194 202.4,-5; 195 202.4,-5.5; 196 202.4,-6; 197 202.4,-6.5; 198 202.4,-7; 199 201.9,-2.75; 200 201.9,-3.25; 201 201.9,-3.75; 202 201.9,-4.25; 203 201.9,-4.75; 204 201.9,-5.25; 205 201.9,-5.75; 206 201.9,-6.25; 207 201.9,-6.75; 208 202.4,-7.5; 209 201.9,-7.25; 210 228,-1; 211 228,-1.5; 212 228,-2; 213 228,-2.5; 214 228,-3; 215 227.5,-0.75; 216 227.5,-1.25; 217 227.5,-1.75; 218 227.5,-2.25; 219 227.5,-2.75; 220 240.8,-0.5; 221 240.8,-1; 222 240.8,-1.5; 223 240.8,-2; 224 240.8,-2.5; 225 240.8,-3; 226 240.3,-0.75; 227 240.3,-1.25; 228 240.3,-1.75; 229 240.3,-2.25; 230 240.3,-2.75; 231 215.2,-4; 232 214.7,-3.75; 233 214.7,-4.25; 234 228,-4; 235 227.5,-3.75; 236 227.5,-4.25; 237 240.8,-4; 238 240.3,-3.75; 239 240.3,-4.25; 240 215.2,-4.5; 241 215.2,-5; 242 215.2,-5.5; 243 215.2,-6; 244 215.2,-6.5; 245 215.2,-7; 246 214.7,-4.75; 247 214.7,-5.25; 248 214.7,-5.75; 249 214.7,-6.25; 250 214.7,-6.75; 251 228,-4.5; 252 228,-5; 253 228,-5.5; 254 228,-6; 255 228,-6.5; 256 228,-7; 257 227.5,-4.75; 258 227.5,-5.25; 259 227.5,-5.75; 260 227.5,-6.25; 261 227.5,-6.75; 262 240.8,-4.5; 263 240.8,-5; 264 240.8,-5.5; 265 240.8,-6; 266 240.8,-6.5; 267 240.8,-7; 268 240.3,-4.75; 269 240.3,-5.25; 270 240.3,-5.75; 271 240.3,-6.25; 272 240.3,-6.75; 273 215.2,4.5; 274 214.7,4.75; 275 215.2,0.5; 276 214.7,0.75; 277 215.2,-3.5; 278 214.7,-3.25; 279 215.2,-7.5; 280 214.7,-7.25; 281 228,4.5; 282 227.5,4.75; 283 228,0.5; 284 227.5,0.75; 285 228,-3.5; 286 227.5,-3.25; 287 228,-7.5; 288 227.5,-7.25; 289 240.8,4.5; 290 240.3,4.75; 291 240.8,0.5; 292 240.3,0.75; 293 240.8,-3.5; 294 240.3,-3.25; 295 240.8,-7.5; 296 240.3,-7.25; IN 213.4,9.25; IN1 226.2,9.25; IN2 239,9.25; IN3 251.8,9.25; P$1 226.7,9; P$2 226.7,8.5; P$3 226.7,8; P$4 226.7,4; P$5 226.2,4.25; P$6 226.2,3.75; P$7 239.5,4; P$8 239,4.25; P$9 239,3.75; P$10 252.3,4; P$11 251.8,4.25; P$12 251.8,3.75; P$13 226.7,3.5; P$14 226.7,3; P$15 226.7,-8; P$16 226.7,-8.5; P$17 226.7,-9; P$18 226.2,8.75; P$19 226.2,8.25; P$20 226.2,7.75; P$21 226.7,2.5; P$22 226.7,2; P$23 226.7,1.5; P$24 226.7,1; P$25 226.2,3.25; P$26 226.2,2.75; P$27 226.2,2.25; P$28 226.2,1.75; P$29 226.2,1.25; P$30 239.5,3.5; P$31 226.2,-7.75; P$32 226.2,-8.25; P$33 226.2,-8.75; P$34 226.2,-9.25; P$35 239.5,9; P$36 239.5,8.5; P$37 239.5,8; P$38 239.5,3; P$39 239.5,2.5; P$40 239.5,2; P$41 239.5,1.5; P$42 239.5,1; P$43 239,3.25; P$44 239,2.75; P$45 239,2.25; P$46 239,1.75; P$47 239,1.25; P$48 252.3,3.5; P$49 213.9,9; P$50 213.9,8.5; P$51 213.9,8; P$52 213.9,2.5; P$53 213.9,2; P$54 213.9,1.5; P$55 213.9,1; P$56 213.9,0.5; P$57 213.9,0; P$58 213.9,-0.5; P$59 213.9,-1; P$60 213.9,-1.5; P$61 213.9,-2; P$62 213.9,-2.5; P$63 213.9,-8; P$64 213.9,-8.5; P$65 213.9,-9; P$66 239.5,-8; P$67 239.5,-8.5; P$68 239.5,-9; P$69 239,8.75; P$70 239,8.25; P$71 239,7.75; P$72 213.4,8.75; P$73 213.4,8.25; P$74 213.4,7.75; P$75 213.4,2.25; P$76 213.4,1.75; P$77 213.4,1.25; P$78 213.4,0.75; P$79 213.4,0.25; P$80 213.4,-0.25; P$81 213.4,-0.75; P$82 213.4,-1.25; P$83 213.4,-1.75; P$84 213.4,-2.25; P$85 213.4,-7.75; P$86 213.4,-8.25; P$87 213.4,-8.75; P$88 213.4,-9.25; P$89 252.3,3; P$90 252.3,2.5; P$91 252.3,2; P$92 252.3,1.5; P$93 252.3,1; P$94 251.8,3.25; P$95 251.8,2.75; P$96 251.8,2.25; P$97 251.8,1.75; P$98 251.8,1.25; P$99 239,-7.75; P$100 239,-8.25; P$101 239,-8.75; P$102 239,-9.25; P$103 252.3,9; P$104 252.3,8.5; P$105 252.3,8; P$106 226.7,0; P$107 226.2,0.25; P$108 226.2,-0.25; P$109 239.5,0; P$110 239,0.25; P$111 239,-0.25; P$112 252.3,0; P$113 251.8,0.25; P$114 251.8,-0.25; P$115 226.7,-0.5; P$116 226.7,-1; P$117 252.3,-8; P$118 252.3,-8.5; P$119 252.3,-9; P$120 251.8,8.75; P$121 251.8,8.25; P$122 251.8,7.75; P$123 226.7,-1.5; P$124 226.7,-2; P$125 226.7,-2.5; P$126 226.7,-3; P$127 226.2,-0.75; P$128 226.2,-1.25; P$129 226.2,-1.75; P$130 226.2,-2.25; P$131 226.2,-2.75; P$132 239.5,-0.5; P$133 251.8,-7.75; P$134 251.8,-8.25; P$135 251.8,-8.75; P$136 251.8,-9.25; P$137 213.9,7.5; P$138 213.9,7; P$139 213.9,6.5; P$140 213.9,6; P$141 213.9,5.5; P$142 213.9,5; P$143 213.4,7.25; P$144 213.4,6.75; P$145 213.4,6.25; P$146 213.4,5.75; P$147 213.4,5.25; P$148 226.7,7.5; P$149 226.7,7; P$150 226.7,6.5; P$151 226.7,6; P$152 226.7,5.5; P$153 226.7,5; P$154 226.2,7.25; P$155 226.2,6.75; P$156 226.2,6.25; P$157 226.2,5.75; P$158 226.2,5.25; P$159 239.5,7.5; P$160 239.5,7; P$161 239.5,6.5; P$162 239.5,6; P$163 239.5,5.5; P$164 239.5,5; P$165 239,7.25; P$166 239,6.75; P$167 239,6.25; P$168 239,5.75; P$169 239,5.25; P$170 252.3,7.5; P$171 252.3,7; P$172 252.3,6.5; P$173 252.3,6; P$174 252.3,5.5; P$175 252.3,5; P$176 251.8,7.25; P$177 251.8,6.75; P$178 251.8,6.25; P$179 251.8,5.75; P$180 251.8,5.25; P$181 213.9,4.5; P$182 213.4,4.75; P$183 213.9,3.5; P$184 213.4,3.75; P$185 213.9,4; P$186 213.9,3; P$187 213.4,4.25; P$188 213.4,3.25; P$189 213.4,2.75; P$190 213.9,-3; P$191 213.9,-3.5; P$192 213.9,-4; P$193 213.9,-4.5; P$194 213.9,-5; P$195 213.9,-5.5; P$196 213.9,-6; P$197 213.9,-6.5; P$198 213.9,-7; P$199 213.4,-2.75; P$200 213.4,-3.25; P$201 213.4,-3.75; P$202 213.4,-4.25; P$203 213.4,-4.75; P$204 213.4,-5.25; P$205 213.4,-5.75; P$206 213.4,-6.25; P$207 213.4,-6.75; P$208 213.9,-7.5; P$209 213.4,-7.25; P$210 239.5,-1; P$211 239.5,-1.5; P$212 239.5,-2; P$213 239.5,-2.5; P$214 239.5,-3; P$215 239,-0.75; P$216 239,-1.25; P$217 239,-1.75; P$218 239,-2.25; P$219 239,-2.75; P$220 252.3,-0.5; P$221 252.3,-1; P$222 252.3,-1.5; P$223 252.3,-2; P$224 252.3,-2.5; P$225 252.3,-3; P$226 251.8,-0.75; P$227 251.8,-1.25; P$228 251.8,-1.75; P$229 251.8,-2.25; P$230 251.8,-2.75; P$231 226.7,-4; P$232 226.2,-3.75; P$233 226.2,-4.25; P$234 239.5,-4; P$235 239,-3.75; P$236 239,-4.25; P$237 252.3,-4; P$238 251.8,-3.75; P$239 251.8,-4.25; P$240 226.7,-4.5; P$241 226.7,-5; P$242 226.7,-5.5; P$243 226.7,-6; P$244 226.7,-6.5; P$245 226.7,-7; P$246 226.2,-4.75; P$247 226.2,-5.25; P$248 226.2,-5.75; P$249 226.2,-6.25; P$250 226.2,-6.75; P$251 239.5,-4.5; P$252 239.5,-5; P$253 239.5,-5.5; P$254 239.5,-6; P$255 239.5,-6.5; P$256 239.5,-7; P$257 239,-4.75; P$258 239,-5.25; P$259 239,-5.75; P$260 239,-6.25; P$261 239,-6.75; P$262 252.3,-4.5; P$263 252.3,-5; P$264 252.3,-5.5; P$265 252.3,-6; P$266 252.3,-6.5; P$267 252.3,-7; P$268 251.8,-4.75; P$269 251.8,-5.25; P$270 251.8,-5.75; P$271 251.8,-6.25; P$272 251.8,-6.75; P$273 226.2,-7.25; P$274 226.7,-7.5; P$275 226.7,-3.5; P$276 226.2,-3.25; P$277 226.7,0.5; P$278 226.2,0.75; P$279 226.7,4.5; P$280 226.2,4.75; P$281 239.5,4.5; P$282 239,4.75; P$283 239.5,0.5; P$284 239,0.75; P$285 239.5,-3.5; P$286 239,-3.25; P$287 239.5,-7.5; P$288 239,-7.25; P$289 252.3,-7.5; P$290 251.8,-7.25; P$291 252.3,-3.5; P$292 251.8,-3.25; P$293 252.3,0.5; P$294 251.8,0.75; P$295 252.3,4.5; P$296 251.8,4.75
smd 1.27 x 0.635: A+ 3,-1; B+ 1,-1; C+ 1,1; D+ 3,1
smd 1.27 x 0.635 bottom: A- 3,1; B- 1,1; C- 1,-1; D- 3,-1

## Footprint FLEXPCB-13MM4-SHORT (pad centres in mm)
drill 0.11 pad 0.2: 1 21.9,4.25; 2 22.4,4; 3 21.9,3.75; 4 22.4,3.5; 5 21.9,3.25; 6 22.4,3; 7 21.9,2.75; 8 22.4,2.5; 9 21.9,2.25; 10 22.4,2; 11 21.9,1.75; 12 22.4,1.5; 13 21.9,1.25; 14 22.4,1; 15 21.9,0.75; 16 22.4,0.5; 17 21.9,0.25; 18 22.4,0; 19 21.9,-0.25; 20 22.4,-0.5; 21 21.9,-0.75; 22 22.4,-1; 23 21.9,-1.25; 24 22.4,-1.5; 25 21.9,-1.75; 26 22.4,-2; 27 21.9,-2.25; 28 22.4,-2.5; 29 21.9,-2.75; 30 22.4,-3; 31 21.9,-3.25; 32 22.4,-3.5; 33 21.9,-3.75; 34 22.4,-4; 35 35.2,4; 36 35.2,3.5; 37 35.2,3; 38 35.2,2.5; 39 35.2,2; 40 35.2,1.5; 41 35.2,1; 42 35.2,0.5; 43 35.2,0; 44 35.2,-0.5; 45 35.2,-1; 46 35.2,-1.5; 47 35.2,-2; 48 35.2,-2.5; 49 35.2,-3; 50 35.2,-3.5; 51 35.2,-4; 52 34.7,4.25; 53 34.7,3.75; 54 34.7,3.25; 55 34.7,2.75; 56 34.7,2.25; 57 34.7,1.75; 58 34.7,1.25; 59 34.7,0.75; 60 34.7,0.25; 61 34.7,-0.25; 62 34.7,-0.75; 63 34.7,-1.25; 64 34.7,-1.75; 65 34.7,-2.25; 66 34.7,-2.75; 67 34.7,-3.25; 68 34.7,-3.75; 69 48,4; 70 48,3.5; 71 48,3; 72 48,2.5; 73 48,2; 74 48,1.5; 75 48,1; 76 48,0.5; 77 48,0; 78 48,-0.5; 79 48,-1; 80 48,-1.5; 81 48,-2; 82 48,-2.5; 83 48,-3; 84 48,-3.5; 85 48,-4; 86 47.5,4.25; 87 47.5,3.75; 88 47.5,3.25; 89 47.5,2.75; 90 47.5,2.25; 91 47.5,1.75; 92 47.5,1.25; 93 47.5,0.75; 94 47.5,0.25; 95 47.5,-0.25; 96 47.5,-0.75; 97 47.5,-1.25; 98 47.5,-1.75; 99 47.5,-2.25; 100 47.5,-2.75; 101 47.5,-3.25; 102 47.5,-3.75; 103 60.8,4; 104 60.8,3.5; 105 60.8,3; 106 60.8,2.5; 107 60.8,2; 108 60.8,1.5; 109 60.8,1; 110 60.8,0.5; 111 60.8,0; 112 60.8,-0.5; 113 60.8,-1; 114 60.8,-1.5; 115 60.8,-2; 116 60.8,-2.5; 117 60.8,-3; 118 60.8,-3.5; 119 60.8,-4; 120 60.3,4.25; 121 60.3,3.75; 122 60.3,3.25; 123 60.3,2.75; 124 60.3,2.25; 125 60.3,1.75; 126 60.3,1.25; 127 60.3,0.75; 128 60.3,0.25; 129 60.3,-0.25; 130 60.3,-0.75; 131 60.3,-1.25; 132 60.3,-1.75; 133 60.3,-2.25; 134 60.3,-2.75; 135 60.3,-3.25; 136 60.3,-3.75; IN 33.4,4.25; IN1 46.2,4.25; IN2 59,4.25; IN3 71.8,4.25; P$1 46.7,4; P$2 46.7,3.5; P$3 46.7,3; P$4 46.7,2.5; P$5 46.7,2; P$6 46.7,1.5; P$7 46.7,1; P$8 46.7,0.5; P$9 46.7,0; P$10 46.7,-0.5; P$11 46.7,-1; P$12 46.7,-1.5; P$13 46.7,-2; P$14 46.7,-2.5; P$15 46.7,-3; P$16 46.7,-3.5; P$17 46.7,-4; P$18 46.2,3.75; P$19 46.2,3.25; P$20 46.2,2.75; P$21 46.2,2.25; P$22 46.2,1.75; P$23 46.2,1.25; P$24 46.2,0.75; P$25 46.2,0.25; P$26 46.2,-0.25; P$27 46.2,-0.75; P$28 46.2,-1.25; P$29 46.2,-1.75; P$30 46.2,-2.25; P$31 46.2,-2.75; P$32 46.2,-3.25; P$33 46.2,-3.75; P$34 46.2,-4.25; P$35 59.5,4; P$36 59.5,3.5; P$37 59.5,3; P$38 59.5,2.5; P$39 59.5,2; P$40 59.5,1.5; P$41 59.5,1; P$42 59.5,0.5; P$43 59.5,0; P$44 59.5,-0.5; P$45 59.5,-1; P$46 59.5,-1.5; P$47 59.5,-2; P$48 59.5,-2.5; P$49 33.9,4; P$50 33.9,3.5; P$51 33.9,3; P$52 33.9,2.5; P$53 33.9,2; P$54 33.9,1.5; P$55 33.9,1; P$56 33.9,0.5; P$57 33.9,0; P$58 33.9,-0.5; P$59 33.9,-1; P$60 33.9,-1.5; P$61 33.9,-2; P$62 33.9,-2.5; P$63 33.9,-3; P$64 33.9,-3.5; P$65 33.9,-4; P$66 59.5,-3; P$67 59.5,-3.5; P$68 59.5,-4; P$69 59,3.75; P$70 59,3.25; P$71 59,2.75; P$72 33.4,3.75; P$73 33.4,3.25; P$74 33.4,2.75; P$75 33.4,2.25; P$76 33.4,1.75; P$77 33.4,1.25; P$78 33.4,0.75; P$79 33.4,0.25; P$80 33.4,-0.25; P$81 33.4,-0.75; P$82 33.4,-1.25; P$83 33.4,-1.75; P$84 33.4,-2.25; P$85 33.4,-2.75; P$86 33.4,-3.25; P$87 33.4,-3.75; P$88 33.4,-4.25; P$89 59,2.25; P$90 59,1.75; P$91 59,1.25; P$92 59,0.75; P$93 59,0.25; P$94 59,-0.25; P$95 59,-0.75; P$96 59,-1.25; P$97 59,-1.75; P$98 59,-2.25; P$99 59,-2.75; P$100 59,-3.25; P$101 59,-3.75; P$102 59,-4.25; P$103 72.3,4; P$104 72.3,3.5; P$105 72.3,3; P$106 72.3,2.5; P$107 72.3,2; P$108 72.3,1.5; P$109 72.3,1; P$110 72.3,0.5; P$111 72.3,0; P$112 72.3,-0.5; P$113 72.3,-1; P$114 72.3,-1.5; P$115 72.3,-2; P$116 72.3,-2.5; P$117 72.3,-3; P$118 72.3,-3.5; P$119 72.3,-4; P$120 71.8,3.75; P$121 71.8,3.25; P$122 71.8,2.75; P$123 71.8,2.25; P$124 71.8,1.75; P$125 71.8,1.25; P$126 71.8,0.75; P$127 71.8,0.25; P$128 71.8,-0.25; P$129 71.8,-0.75; P$130 71.8,-1.25; P$131 71.8,-1.75; P$132 71.8,-2.25; P$133 71.8,-2.75; P$134 71.8,-3.25; P$135 71.8,-3.75; P$136 71.8,-4.25
smd 1.27 x 0.635: A+ 3,-1; B+ 1,-1; C+ 1,1; D+ 3,1
smd 1.27 x 0.635 bottom: A- 3,1; B- 1,1; C- 1,-1; D- 3,-1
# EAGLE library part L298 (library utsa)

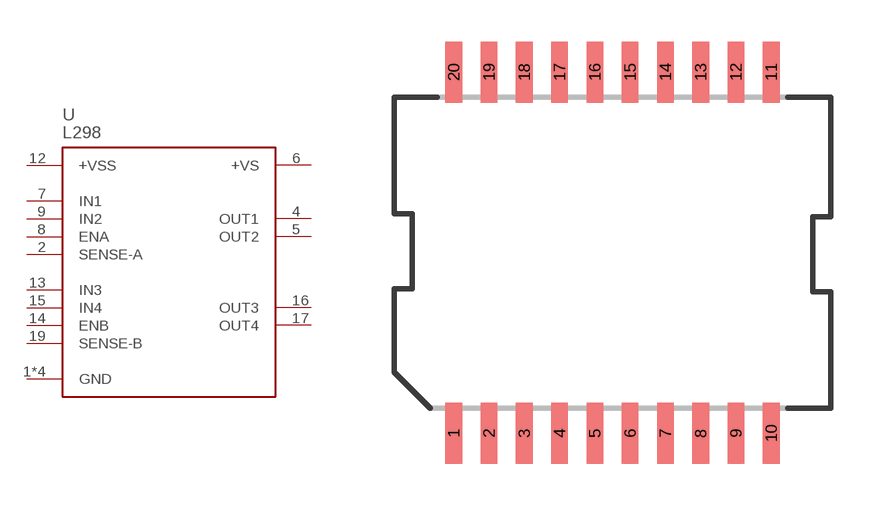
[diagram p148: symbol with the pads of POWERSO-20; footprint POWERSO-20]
Designator prefix U

## L298P  [POWERSO-20]
1  GND
2  SENSE-A
4  OUT1
5  OUT2
6  +VS
7  IN1
8  ENA
9  IN2
10  GND
11  GND
12  +VSS
13  IN3
14  ENB
15  IN4
16  OUT3
17  OUT4
19  SENSE-B
20  GND

## Footprint POWERSO-20 (pad centres in mm)
Power Small Outline
smd 0.6 x 2.2: 1 -5.715,-6.5; 2 -4.445,-6.5; 3 -3.175,-6.5; 4 -1.905,-6.5; 5 -0.635,-6.5; 6 0.635,-6.5; 7 1.905,-6.5; 8 3.175,-6.5; 9 4.445,-6.5; 10 5.715,-6.5; 11 5.715,6.5; 12 4.445,6.5; 13 3.175,6.5; 14 1.905,6.5; 15 0.635,6.5; 16 -0.635,6.5; 17 -1.905,6.5; 18 -3.175,6.5; 19 -4.445,6.5; 20 -5.715,6.5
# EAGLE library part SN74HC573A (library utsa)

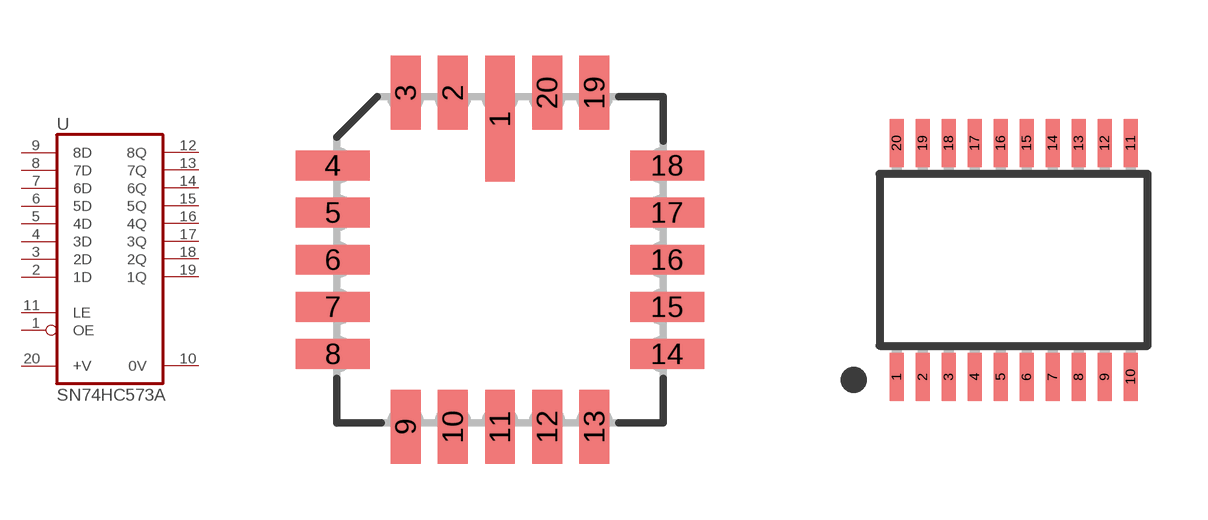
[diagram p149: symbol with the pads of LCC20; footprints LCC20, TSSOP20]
Designator prefix U

## SN74HC573AFK  [LCC20]
1  OE  in
2  1D  in
3  2D  in
4  3D  in
5  4D  in
6  5D  in
7  6D  in
8  7D  in
9  8D  in
10  0V
11  LE  in
12  8Q  hiz
13  7Q  hiz
14  6Q  hiz
15  5Q  hiz
16  4Q  hiz
17  3Q  hiz
18  2Q  hiz
19  1Q  hiz
20  +V

## SN74HC573APW  [TSSOP20]
Pads as for LCC20

## Footprint LCC20 (pad centres in mm)
Leadless Chip Carrier Ceramic Package
smd 0.8 x 3.4: 1 0,3.8
smd 0.8 x 2: 2 -1.27,4.5; 3 -2.54,4.5; 9 -2.54,-4.5; 10 -1.27,-4.5; 11 0,-4.5; 12 1.27,-4.5; 13 2.54,-4.5; 19 2.54,4.5; 20 1.27,4.5
smd 2 x 0.8: 4 -4.5,2.54; 5 -4.5,1.27; 6 -4.5,0; 7 -4.5,-1.27; 8 -4.5,-2.54; 14 4.5,-2.54; 15 4.5,-1.27; 16 4.5,0; 17 4.5,1.27; 18 4.5,2.54

## Footprint TSSOP20 (pad centres in mm)
smd 0.35 x 1.2: 1 -2.925,-2.925; 2 -2.275,-2.925; 3 -1.625,-2.925; 4 -0.975,-2.925; 5 -0.325,-2.925; 6 0.325,-2.925; 7 0.975,-2.925; 8 1.625,-2.925; 9 2.275,-2.925; 10 2.925,-2.925; 11 2.925,2.925; 12 2.275,2.925; 13 1.625,2.925; 14 0.975,2.925; 15 0.325,2.925; 16 -0.325,2.925; 17 -0.975,2.925; 18 -1.625,2.925; 19 -2.275,2.925; 20 -2.925,2.925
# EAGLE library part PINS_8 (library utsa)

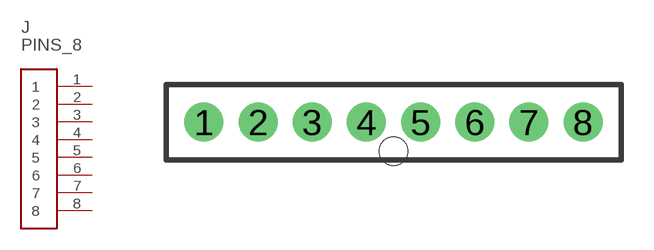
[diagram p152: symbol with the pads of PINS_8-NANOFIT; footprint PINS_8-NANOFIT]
Designator prefix J

## PINS_8105309-1108  [PINS_8-NANOFIT]
1  1
2  2
3  3
4  4
5  5
6  6
7  7
8  8

## Footprint PINS_8-NANOFIT (pad centres in mm)
drill 1.2: 1 -8.75,0; 2 -6.25,0; 3 -3.75,0; 4 -1.25,0; 5 1.25,0; 6 3.75,0; 7 6.25,0; 8 8.75,0
hole 1.3 at 0,-1.34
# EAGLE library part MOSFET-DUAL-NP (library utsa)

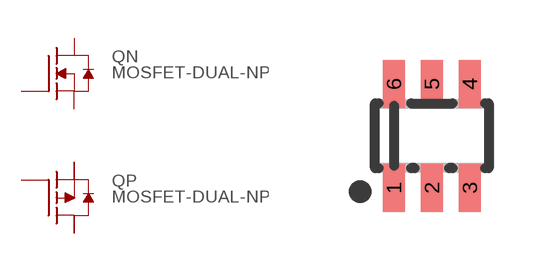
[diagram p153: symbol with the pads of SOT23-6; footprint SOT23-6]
Designator prefix Q; gates N=MOSFET-N P=MOSFET-P

## MOSFET-DUAL-NPDMC1028UVT  [SOT23-6]
1  N:G  pas
2  P:S  pas
3  P:G  pas
4  P:D  pas
5  N:S  pas
6  N:D  pas

## Footprint SOT23-6 (pad centres in mm)
smd 0.55 x 1.2: 1 -0.95,-1.3; 2 0,-1.3; 3 0.95,-1.3; 4 0.95,1.3; 5 0,1.3; 6 -0.95,1.3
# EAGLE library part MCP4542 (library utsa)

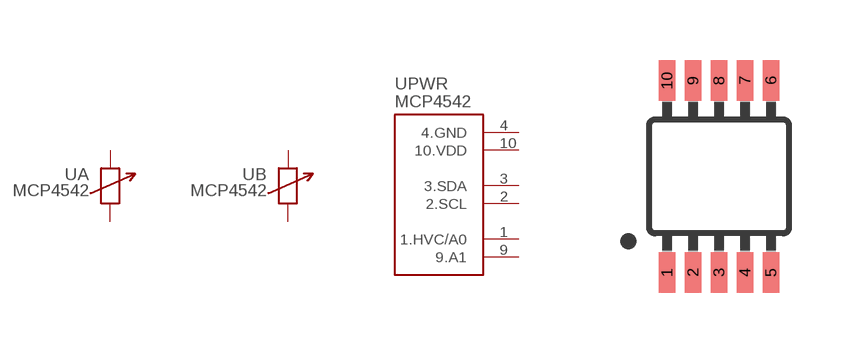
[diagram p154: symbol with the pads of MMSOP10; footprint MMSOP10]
Designator prefix U; gates A=POT_REHOSTAT B=POT_REHOSTAT PWR=MCP4542

## MCP4542T  [MMSOP10]
1  PWR:1.HVC/A0
2  PWR:2.SCL
3  PWR:3.SDA
4  PWR:4.GND
5  B:B
6  B:W
7  A:W
8  A:B
9  PWR:9.A1
10  PWR:10.VDD

## Footprint MMSOP10 (pad centres in mm)
smd 0.41 x 1.02: 1 -1.3,-2.4; 2 -0.65,-2.4; 3 0,-2.4; 4 0.65,-2.4; 5 1.3,-2.4; 6 1.3,2.4; 7 0.65,2.4; 8 0,2.4; 9 -0.65,2.4; 10 -1.3,2.4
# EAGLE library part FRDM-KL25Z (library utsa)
For creating FRDM-KL25Z shields Check prices

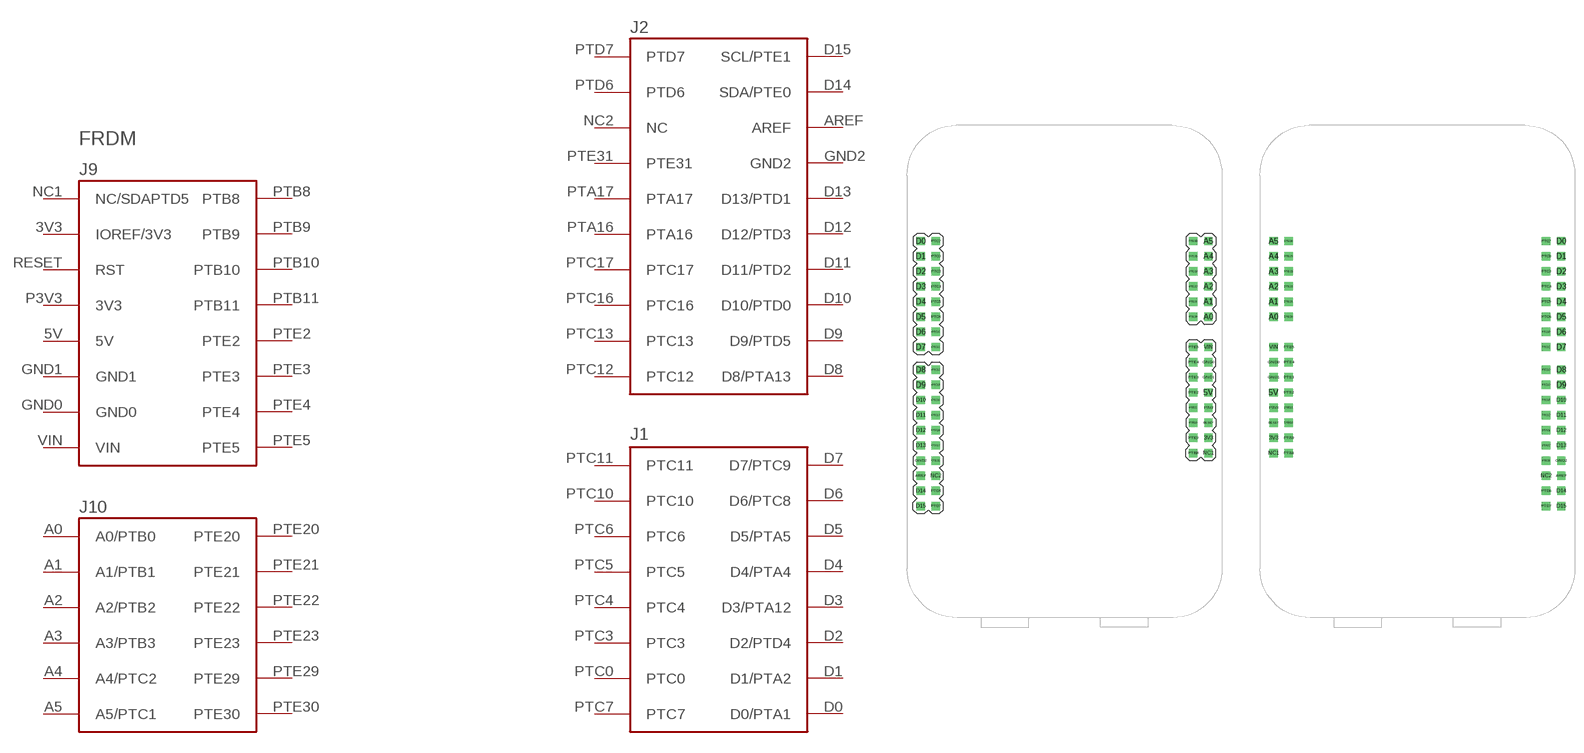
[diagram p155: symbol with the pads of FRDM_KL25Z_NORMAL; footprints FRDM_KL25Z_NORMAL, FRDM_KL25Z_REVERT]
Designator prefix FRDM

## FRDM-KL25ZNORMAL (AVAILABILITY: In Stock; DESCRIPTION: KL1x, KL2x, mbed-Enabled Development Freedom Kinetis ARM® Cortex®-M0+ MCU 32-Bit Embedded Evaluation Board; MF: NXP USA; MP: FRDM-KL25Z; PACKAGE: 0805 Freescale Semiconductor; PRICE: None; PURCHASE-URL: https://pricing.snapeda.com/search/part/FRDM-KL25Z/?ref=eda)  [FRDM_KL25Z_NORMAL]
3V3  IOREF/3V3
5V  5V
A0  A0/PTB0
A1  A1/PTB1
A2  A2/PTB2
A3  A3/PTB3
A4  A4/PTC2
A5  A5/PTC1
AREF  AREF
D0  D0/PTA1
D1  D1/PTA2
D2  D2/PTD4
D3  D3/PTA12
D4  D4/PTA4
D5  D5/PTA5
D6  D6/PTC8
D7  D7/PTC9
D8  D8/PTA13
D9  D9/PTD5
D10  D10/PTD0
D11  D11/PTD2
D12  D12/PTD3
D13  D13/PTD1
D14  SDA/PTE0
D15  SCL/PTE1
GND0  GND0
GND1  GND1
GND2  GND2
NC1  NC/SDAPTD5
NC2  NC
P3V3  3V3
PTA16  PTA16
PTA17  PTA17
PTB8  PTB8
PTB9  PTB9
PTB10  PTB10
PTB11  PTB11
PTC0  PTC0
PTC3  PTC3
PTC4  PTC4
PTC5  PTC5
PTC6  PTC6
PTC7  PTC7
PTC10  PTC10
PTC11  PTC11
PTC12  PTC12
PTC13  PTC13
PTC16  PTC16
PTC17  PTC17
PTD6  PTD6
PTD7  PTD7
PTE2  PTE2
PTE3  PTE3
PTE4  PTE4
PTE5  PTE5
PTE20  PTE20
PTE21  PTE21
PTE22  PTE22
PTE23  PTE23
PTE29  PTE29
PTE30  PTE30
PTE31  PTE31
RESET  RST
VIN  VIN

## FRDM-KL25ZREVERT (AVAILABILITY: In Stock; DESCRIPTION: KL1x, KL2x, mbed-Enabled Development Freedom Kinetis ARM® Cortex®-M0+ MCU 32-Bit Embedded Evaluation Board; MF: NXP USA; MP: FRDM-KL25Z; PACKAGE: 0805 Freescale Semiconductor; PRICE: None; PURCHASE-URL: https://pricing.snapeda.com/search/part/FRDM-KL25Z/?ref=eda)  [FRDM_KL25Z_REVERT]
Pads as for FRDM_KL25Z_NORMAL

## Footprint FRDM_KL25Z_NORMAL (pad centres in mm)
drill 0.9 square: 3V3 24.13,-15.24; 5V 24.13,-7.62; A0 24.13,5.08; A1 24.13,7.62; A2 24.13,10.16; A3 24.13,12.7; A4 24.13,15.24; A5 24.13,17.78; AREF -24.13,-21.59; D0 -24.13,17.78; D1 -24.13,15.24; D2 -24.13,12.7; D3 -24.13,10.16; D4 -24.13,7.62; D5 -24.13,5.08; D6 -24.13,2.54; D7 -24.13,0; D8 -24.13,-3.81; D9 -24.13,-6.35; D10 -24.13,-8.89; D11 -24.13,-11.43; D12 -24.13,-13.97; D13 -24.13,-16.51; D14 -24.13,-24.13; D15 -24.13,-26.67; GND0 24.13,-2.54; GND1 24.13,-5.08; GND2 -24.13,-19.05; NC1 24.13,-17.78; NC2 -21.59,-21.59; P3V3 24.13,-10.16; PTA16 -21.59,-13.97; PTA17 -21.59,-16.51; PTB8 21.59,-17.78; PTB9 21.59,-15.24; PTB10 21.59,-12.7; PTB11 21.59,-10.16; PTC0 -21.59,15.24; PTC3 -21.59,12.7; PTC4 -21.59,10.16; PTC5 -21.59,7.62; PTC6 -21.59,5.08; PTC7 -21.59,17.78; PTC10 -21.59,2.54; PTC11 -21.59,0; PTC12 -21.59,-3.81; PTC13 -21.59,-6.35; PTC16 -21.59,-8.89; PTC17 -21.59,-11.43; PTD6 -21.59,-24.13; PTD7 -21.59,-26.67; PTE2 21.59,-7.62; PTE3 21.59,-5.08; PTE4 21.59,-2.54; PTE5 21.59,0; PTE20 21.59,5.08; PTE21 21.59,7.62; PTE22 21.59,10.16; PTE23 21.59,12.7; PTE29 21.59,15.24; PTE30 21.59,17.78; PTE31 -21.59,-19.05; RESET 24.13,-12.7; VIN 24.13,0

## Footprint FRDM_KL25Z_REVERT (pad centres in mm)
drill 0.9 square: 3V3 -24.13,-15.24; 5V -24.13,-7.62; A0 -24.13,5.08; A1 -24.13,7.62; A2 -24.13,10.16; A3 -24.13,12.7; A4 -24.13,15.24; A5 -24.13,17.78; AREF 24.13,-21.59; D0 24.13,17.78; D1 24.13,15.24; D2 24.13,12.7; D3 24.13,10.16; D4 24.13,7.62; D5 24.13,5.08; D6 24.13,2.54; D7 24.13,0; D8 24.13,-3.81; D9 24.13,-6.35; D10 24.13,-8.89; D11 24.13,-11.43; D12 24.13,-13.97; D13 24.13,-16.51; D14 24.13,-24.13; D15 24.13,-26.67; GND0 -24.13,-2.54; GND1 -24.13,-5.08; GND2 24.13,-19.05; NC1 -24.13,-17.78; NC2 21.59,-21.59; P3V3 -24.13,-10.16; PTA16 21.59,-13.97; PTA17 21.59,-16.51; PTB8 -21.59,-17.78; PTB9 -21.59,-15.24; PTB10 -21.59,-12.7; PTB11 -21.59,-10.16; PTC0 21.59,15.24; PTC3 21.59,12.7; PTC4 21.59,10.16; PTC5 21.59,7.62; PTC6 21.59,5.08; PTC7 21.59,17.78; PTC10 21.59,2.54; PTC11 21.59,0; PTC12 21.59,-3.81; PTC13 21.59,-6.35; PTC16 21.59,-8.89; PTC17 21.59,-11.43; PTD6 21.59,-24.13; PTD7 21.59,-26.67; PTE2 -21.59,-7.62; PTE3 -21.59,-5.08; PTE4 -21.59,-2.54; PTE5 -21.59,0; PTE20 -21.59,5.08; PTE21 -21.59,7.62; PTE22 -21.59,10.16; PTE23 -21.59,12.7; PTE29 -21.59,15.24; PTE30 -21.59,17.78; PTE31 21.59,-19.05; RESET -24.13,-12.7; VIN -24.13,0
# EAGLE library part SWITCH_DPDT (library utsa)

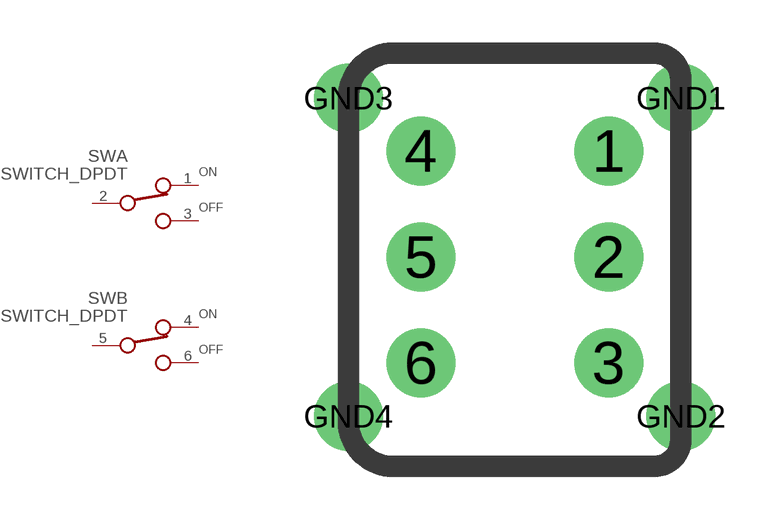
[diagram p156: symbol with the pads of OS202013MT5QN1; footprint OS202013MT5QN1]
Designator prefix SW; gates A=SWITCH_DPDT B=SWITCH_DPDT

## SWITCH_DPDT  [OS202013MT5QN1]
1  A:ON
2  A:IN
3  A:OFF
4  B:ON
5  B:IN
6  B:OFF

## Footprint OS202013MT5QN1 (pad centres in mm)
drill 1.3: 1 2.653,3.001; 2 2.653,0.004; 3 2.653,-2.993; 4 -2.655,3.001; 5 -2.655,0.004; 6 -2.655,-2.993; GND1 4.698,4.5; GND2 4.698,-4.492; GND3 -4.7,4.5; GND4 -4.7,-4.492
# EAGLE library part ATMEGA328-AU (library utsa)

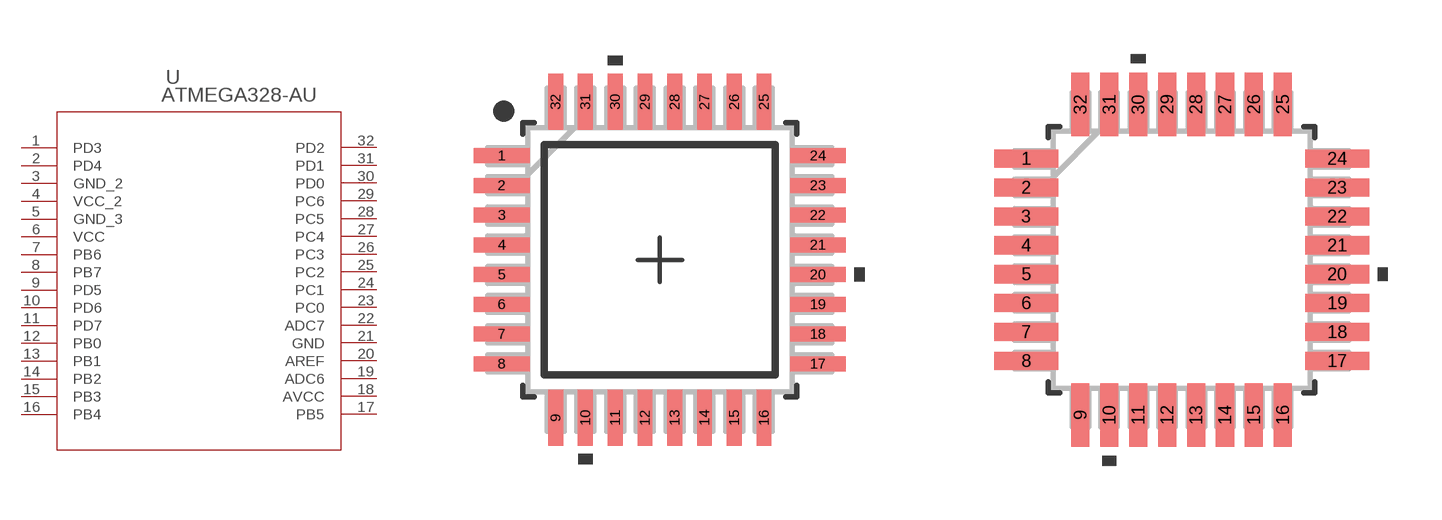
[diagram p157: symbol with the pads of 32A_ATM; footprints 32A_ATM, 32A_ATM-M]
Designator prefix U

## ATMEGA328-AU (COPYRIGHT: Copyright (C) 2021 Ultra Librarian. All rights reserved.; MANUFACTURER_PART_NUMBER: ATMEGA328-AU; MFR_NAME: Microchip)  [32A_ATM]
1  PD3
2  PD4
3  GND_2  pwr
4  VCC_2  pwr
5  GND_3  pwr
6  VCC  pwr
7  PB6
8  PB7
9  PD5
10  PD6
11  PD7
12  PB0
13  PB1
14  PB2
15  PB3
16  PB4
17  PB5
18  AVCC  pwr
19  ADC6  pas
20  AREF  pas
21  GND  pwr
22  ADC7  pas
23  PC0
24  PC1
25  PC2
26  PC3
27  PC4
28  PC5
29  PC6
30  PD0
31  PD1
32  PD2

## ATMEGA328-AU32A_ATM-M (COPYRIGHT: Copyright (C) 2021 Ultra Librarian. All rights reserved.; MANUFACTURER_PART_NUMBER: ATMEGA328-AU; MFR_NAME: Microchip)  [32A_ATM-M]
Pads as for 32A_ATM

## ATMEGA328-AU32A_ATM-L (COPYRIGHT: Copyright (C) 2021 Ultra Librarian. All rights reserved.; MANUFACTURER_PART_NUMBER: ATMEGA328-AU; MFR_NAME: Microchip)  [32A_ATM-L]
Pads as for 32A_ATM

## Footprint 32A_ATM (pad centres in mm)
smd 1.5 x 0.4: 1 -4.25,2.8; 2 -4.25,2; 3 -4.25,1.2; 4 -4.25,0.4; 5 -4.25,-0.4; 6 -4.25,-1.2; 7 -4.25,-2; 8 -4.25,-2.8; 17 4.25,-2.8; 18 4.25,-2; 19 4.25,-1.2; 20 4.25,-0.4; 21 4.25,0.4; 22 4.25,1.2; 23 4.25,2; 24 4.25,2.8
smd 0.4 x 1.5: 9 -2.8,-4.25; 10 -2,-4.25; 11 -1.2,-4.25; 12 -0.4,-4.25; 13 0.4,-4.25; 14 1.2,-4.25; 15 2,-4.25; 16 2.8,-4.25; 25 2.8,4.25; 26 2,4.25; 27 1.2,4.25; 28 0.4,4.25; 29 -0.4,4.25; 30 -1.2,4.25; 31 -2,4.25; 32 -2.8,4.25

## Footprint 32A_ATM-M (pad centres in mm)
smd 1.766 x 0.501: 1 -4.301,2.8; 2 -4.301,2; 3 -4.301,1.2; 4 -4.301,0.4; 5 -4.301,-0.4; 6 -4.301,-1.2; 7 -4.301,-2; 8 -4.301,-2.8; 17 4.301,-2.8; 18 4.301,-2; 19 4.301,-1.2; 20 4.301,-0.4; 21 4.301,0.4; 22 4.301,1.2; 23 4.301,2; 24 4.301,2.8
smd 0.501 x 1.766: 9 -2.8,-4.301; 10 -2,-4.301; 11 -1.2,-4.301; 12 -0.4,-4.301; 13 0.4,-4.301; 14 1.2,-4.301; 15 2,-4.301; 16 2.8,-4.301; 25 2.8,4.301; 26 2,4.301; 27 1.2,4.301; 28 0.4,4.301; 29 -0.4,4.301; 30 -1.2,4.301; 31 -2,4.301; 32 -2.8,4.301

## Footprint 32A_ATM-L (pad centres in mm)
smd 1.156 x 0.45: 1 -4.199,2.8; 2 -4.199,2; 3 -4.199,1.2; 4 -4.199,0.4; 5 -4.199,-0.4; 6 -4.199,-1.2; 7 -4.199,-2; 8 -4.199,-2.8; 17 4.199,-2.8; 18 4.199,-2; 19 4.199,-1.2; 20 4.199,-0.4; 21 4.199,0.4; 22 4.199,1.2; 23 4.199,2; 24 4.199,2.8
smd 0.45 x 1.156: 9 -2.8,-4.199; 10 -2,-4.199; 11 -1.2,-4.199; 12 -0.4,-4.199; 13 0.4,-4.199; 14 1.2,-4.199; 15 2,-4.199; 16 2.8,-4.199; 25 2.8,4.199; 26 2,4.199; 27 1.2,4.199; 28 0.4,4.199; 29 -0.4,4.199; 30 -1.2,4.199; 31 -2,4.199; 32 -2.8,4.199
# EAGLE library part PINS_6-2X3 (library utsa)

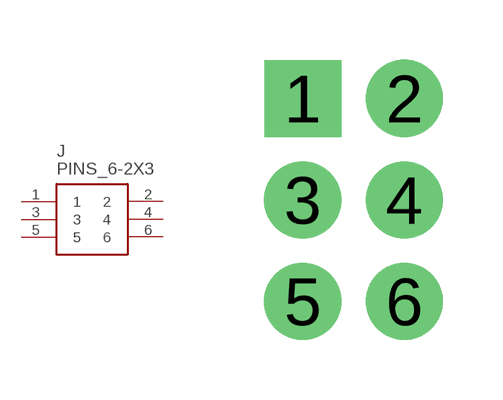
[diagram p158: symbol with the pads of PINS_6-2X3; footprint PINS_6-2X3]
Designator prefix J

## PINS_6-2X3  [PINS_6-2X3]
1  1
2  2
3  3
4  4
5  5
6  6

## Footprint PINS_6-2X3 (pad centres in mm)
drill 1.1 pad 1.93 square: 1 0,0
drill 1.1 pad 1.93: 2 2.54,0; 3 0,-2.54; 4 2.54,-2.54; 5 0,-5.08; 6 2.54,-5.08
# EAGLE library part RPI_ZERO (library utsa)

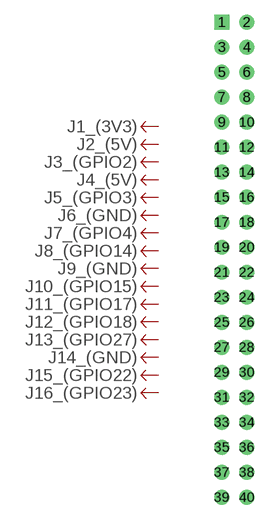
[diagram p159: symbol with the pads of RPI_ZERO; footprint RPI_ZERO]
Designator prefix J; gates 1_(3V3)=MINIPCB_SIGNAL_1 2_(5V)=MINIPCB_SIGNAL_1 3_(GPIO2)=MINIPCB_SIGNAL_1 4_(5V)=MINIPCB_SIGNAL_1 5_(GPIO3)=MINIPCB_SIGNAL_1 6_(GND)=MINIPCB_SIGNAL_1 7_(GPIO4)=MINIPCB_SIGNAL_1 8_(GPIO14)=MINIPCB_SIGNAL_1 9_(GND)=MINIPCB_SIGNAL_1 10_(GPIO15)=MINIPCB_SIGNAL_1 11_(GPIO17)=MINIPCB_SIGNAL_1 12_(GPIO18)=MINIPCB_SIGNAL_1 13_(GPIO27)=MINIPCB_SIGNAL_1 14_(GND)=MINIPCB_SIGNAL_1 15_(GPIO22)=MINIPCB_SIGNAL_1 16_(GPIO23)=MINIPCB_SIGNAL_1 17_(3V3)=MINIPCB_SIGNAL_1 18_(GPIO24)=MINIPCB_SIGNAL_1 19_(GPIO10)=MINIPCB_SIGNAL_1 20_(GND)=MINIPCB_SIGNAL_1 22_(GPIO25)=MINIPCB_SIGNAL_1 21_(GPIO9)=MINIPCB_SIGNAL_1 23_(GPIO11)=MINIPCB_SIGNAL_1 24_(GPIO8)=MINIPCB_SIGNAL_1 25_(GND)=MINIPCB_SIGNAL_1 26_(GPIO7)=MINIPCB_SIGNAL_1 28_(SCL)=MINIPCB_SIGNAL_1 27_(SDA)=MINIPCB_SIGNAL_1 29_(GPIO5)=MINIPCB_SIGNAL_1 30_(GND)=MINIPCB_SIGNAL_1 31_(GPIO6)=MINIPCB_SIGNAL_1 32_(GPIO12)=MINIPCB_SIGNAL_1 33_(GPIO13)=MINIPCB_SIGNAL_1 34_(GND)=MINIPCB_SIGNAL_1 35_(GPIO19)=MINIPCB_SIGNAL_1 36_(GPIO16)=MINIPCB_SIGNAL_1 37_(GPIO26)=MINIPCB_SIGNAL_1 39_(GND)=MINIPCB_SIGNAL_1 38_(GPIO20)=MINIPCB_SIGNAL_1 40_(GPIO21)=MINIPCB_SIGNAL_1 G$1=RPI-ZERO G$2=RPI-ZERO-PINMAP

## RPI_ZERO  [RPI_ZERO]
1  1_(3V3):1
2  2_(5V):1
3  3_(GPIO2):1
4  4_(5V):1
5  5_(GPIO3):1
6  6_(GND):1
7  7_(GPIO4):1
8  8_(GPIO14):1
9  9_(GND):1
10  10_(GPIO15):1
11  11_(GPIO17):1
12  12_(GPIO18):1
13  13_(GPIO27):1
14  14_(GND):1
15  15_(GPIO22):1
16  16_(GPIO23):1
17  17_(3V3):1
18  18_(GPIO24):1
19  19_(GPIO10):1
20  20_(GND):1
21  21_(GPIO9):1
22  22_(GPIO25):1
23  23_(GPIO11):1
24  24_(GPIO8):1
25  25_(GND):1
26  26_(GPIO7):1
27  27_(SDA):1
28  28_(SCL):1
29  29_(GPIO5):1
30  30_(GND):1
31  31_(GPIO6):1
32  32_(GPIO12):1
33  33_(GPIO13):1
34  34_(GND):1
35  35_(GPIO19):1
36  36_(GPIO16):1
37  37_(GPIO26):1
38  38_(GPIO20):1
39  39_(GND):1
40  40_(GPIO21):1

## Footprint RPI_ZERO (pad centres in mm)
drill 1 square: 1 0,0
drill 1: 2 2.54,0; 3 0,-2.54; 4 2.54,-2.54; 5 0,-5.08; 6 2.54,-5.08; 7 0,-7.62; 8 2.54,-7.62; 9 0,-10.16; 10 2.54,-10.16; 11 0,-12.7; 12 2.54,-12.7; 13 0,-15.24; 14 2.54,-15.24; 15 0,-17.78; 16 2.54,-17.78; 17 0,-20.32; 18 2.54,-20.32; 19 0,-22.86; 20 2.54,-22.86; 21 0,-25.4; 22 2.54,-25.4; 23 0,-27.94; 24 2.54,-27.94; 25 0,-30.48; 26 2.54,-30.48; 27 0,-33.02; 28 2.54,-33.02; 29 0,-35.56; 30 2.54,-35.56; 31 0,-38.1; 32 2.54,-38.1; 33 0,-40.64; 34 2.54,-40.64; 35 0,-43.18; 36 2.54,-43.18; 37 0,-45.72; 38 2.54,-45.72; 39 0,-48.26; 40 2.54,-48.26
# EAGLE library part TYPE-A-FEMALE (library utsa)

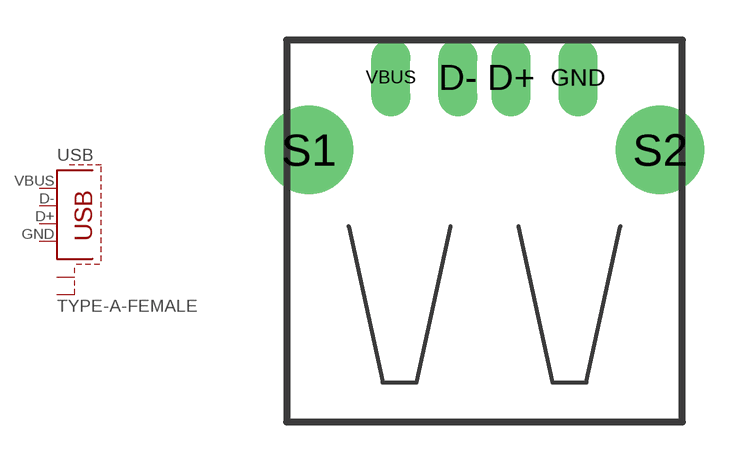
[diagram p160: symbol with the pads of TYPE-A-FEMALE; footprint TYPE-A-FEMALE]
Designator prefix USB

## TYPE-A-FEMALE (OC_FARNELL: unknown; OC_NEWARK: unknown)  [TYPE-A-FEMALE]
D+  D+  pas
D-  D-  pas
GND  GND  pas
S1  S1  pas
S2  S2  pas
VBUS  VCC  pas

## Footprint TYPE-A-FEMALE (pad centres in mm)
USB connector with shield
drill 0.95 long: D+ 1,2.71; D- -1,2.71; GND 3.5,2.71; VBUS -3.5,2.71
drill 2.3 pad 2.9: S1 -6.57,0; S2 6.57,0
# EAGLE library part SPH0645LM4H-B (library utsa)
Mic Mems Digital I2s Omni -26db

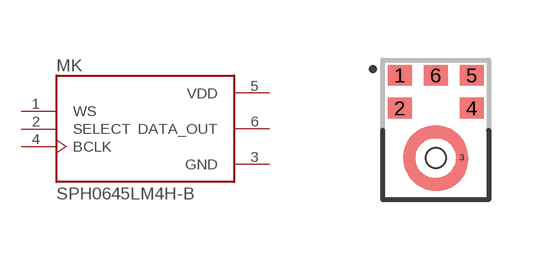
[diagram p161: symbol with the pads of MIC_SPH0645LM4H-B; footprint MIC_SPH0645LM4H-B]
Designator prefix MK

## SPH0645LM4H-B (DESCRIPTION: 20 Hz ~ 10 kHz Digital, I²S Microphone MEMS (Silicon) 1.62 V ~ 3.6 V Omnidirectional (-26dB ±3dB @ 94dB SPL) Solder Pads; DIGI-KEY_PART_NUMBER: 423-1405-2-ND; MF: Knowles; MP: SPH0645LM4H-B; PACKAGE: None; PURCHASE-URL: https://pricing.snapeda.com/search/part/SPH0645LM4H-B/?ref=eda)  [MIC_SPH0645LM4H-B]
1  WS  in
2  SELECT  in
3  GND  pwr
4  BCLK  in
5  VDD  pwr
6  DATA_OUT  out

## Footprint MIC_SPH0645LM4H-B (pad centres in mm)
smd 0.6 x 0.522: 1 -0.9,2.074; 2 -0.9,1.252; 4 0.9,1.252; 5 0.9,2.074; 6 0,2.074
smd 0.1 x 0.1: 3 0.65,0.02
hole 0.5 at 0,0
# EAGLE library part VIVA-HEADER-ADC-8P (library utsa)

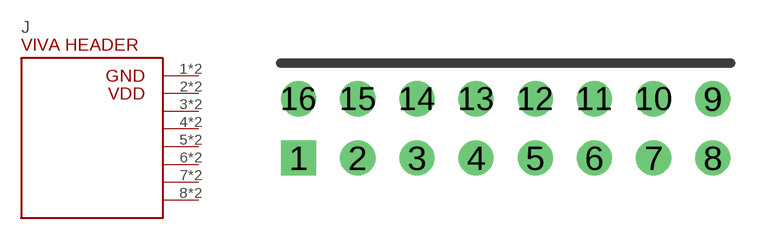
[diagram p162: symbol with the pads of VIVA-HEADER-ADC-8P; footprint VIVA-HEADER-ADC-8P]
Designator prefix J

## VIVA-HEADER-ADC-8P (P3: P3 TEXT; P4: P4 TEXT; P5: P5 TEXT; P6: P6 TEXT; P7: P7 TEXT; P8: P8 TEXT)  [VIVA-HEADER-ADC-8P]
1  1.GND
2  2.VDD
3  3.ADC0
4  4.ADC1
5  5.ADC2
6  6.ADC3
7  7.ADC4
8  8.ADC5
9  8.ADC5
10  7.ADC4
11  6.ADC3
12  5.ADC2
13  4.ADC1
14  3.ADC0
15  2.VDD
16  1.GND

## Footprint VIVA-HEADER-ADC-8P (pad centres in mm)
drill 1 square: 1 0,0
drill 1: 2 2.54,0; 3 5.08,0; 4 7.62,0; 5 10.16,0; 6 12.7,0; 7 15.24,0; 8 17.78,0; 9 17.78,2.54; 10 15.24,2.54; 11 12.7,2.54; 12 10.16,2.54; 13 7.62,2.54; 14 5.08,2.54; 15 2.54,2.54; 16 0,2.54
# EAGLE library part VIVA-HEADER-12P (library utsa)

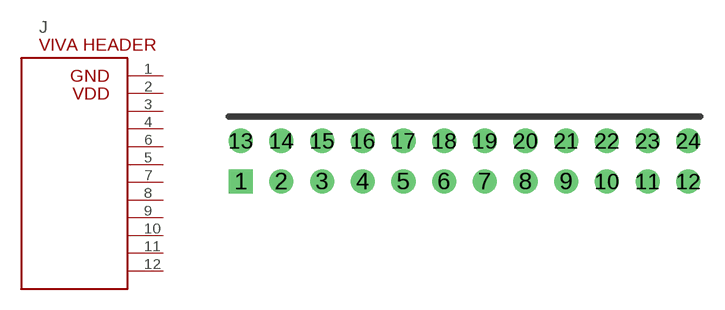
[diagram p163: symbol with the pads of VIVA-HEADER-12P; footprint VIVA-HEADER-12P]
Designator prefix J

## VIVA-HEADER-12P (P10: P10 TEXT; P11: P11 TEXT; P12: P12 TEXT; P3: P3 TEXT; P4: P4 TEXT; P5: P5 TEXT; P6: P6 TEXT; P7: P7 TEXT; P8: P8 TEXT; P9: P9 TEXT)  [VIVA-HEADER-12P]
1  1.GND
2  2.VDD
3  3.ADC0
4  4.ADC1
5  5.ADC1
6  5.ADC2
7  5.ADC3
8  5.ADC4
9  5.ADC5
10  5.ADC6
11  5.ADC7
12  5.ADC8

## Footprint VIVA-HEADER-12P (pad centres in mm)
drill 1 square: 1 0,0
drill 1: 2 2.54,0; 3 5.08,0; 4 7.62,0; 5 10.16,0; 6 12.7,0; 7 15.24,0; 8 17.78,0; 9 20.32,0; 10 22.86,0; 11 25.4,0; 12 27.94,0; 13 0,2.54; 14 2.54,2.54; 15 5.08,2.54; 16 7.62,2.54; 17 10.16,2.54; 18 12.7,2.54; 19 15.24,2.54; 20 17.78,2.54; 21 20.32,2.54; 22 22.86,2.54; 23 25.4,2.54; 24 27.94,2.54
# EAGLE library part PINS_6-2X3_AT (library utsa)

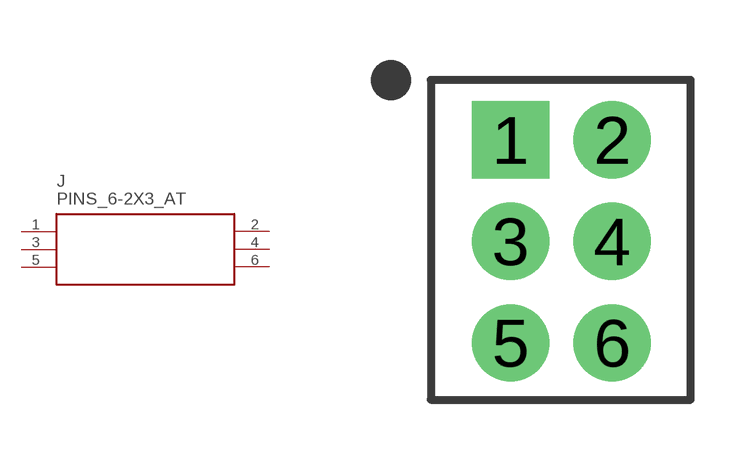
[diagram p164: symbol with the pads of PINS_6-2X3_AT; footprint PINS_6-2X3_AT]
Designator prefix J

## PINS_6-2X3_AT (P1: P1 NAME; P2: P2 NAME; P3: P3 NAME; P4: P4 NAME; P5: P5 NAME; P6: P6 NAME)  [PINS_6-2X3_AT]
1  1
2  2
3  3
4  4
5  5
6  6

## Footprint PINS_6-2X3_AT (pad centres in mm)
drill 1.1 pad 1.93 square: 1 0,0
drill 1.1 pad 1.93: 2 2.54,0; 3 0,-2.54; 4 2.54,-2.54; 5 0,-5.08; 6 2.54,-5.08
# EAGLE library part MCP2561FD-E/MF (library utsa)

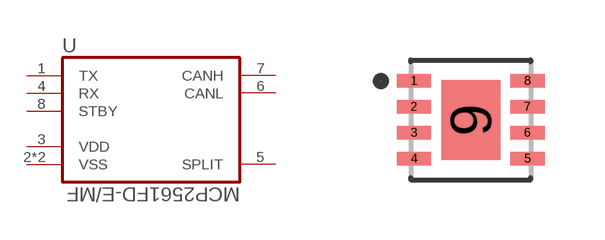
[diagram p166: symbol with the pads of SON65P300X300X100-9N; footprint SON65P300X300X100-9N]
Designator prefix U

## MCP2561FD-E/MF  [SON65P300X300X100-9N]
1  TX
2  VSS  pas
3  VDD  pwr
4  RX  in
5  SPLIT  pas
6  CANL  in
7  CANH
8  STBY  pwr
9  VSS  pas

## Footprint SON65P300X300X100-9N (pad centres in mm)
smd 0.87 x 0.32: 1 -1.42,0.975; 2 -1.42,0.325; 3 -1.42,-0.325; 4 -1.42,-0.975; 5 1.42,-0.975; 6 1.42,-0.325; 7 1.42,0.325; 8 1.42,0.975
smd 1.47 x 2: 9 0,0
